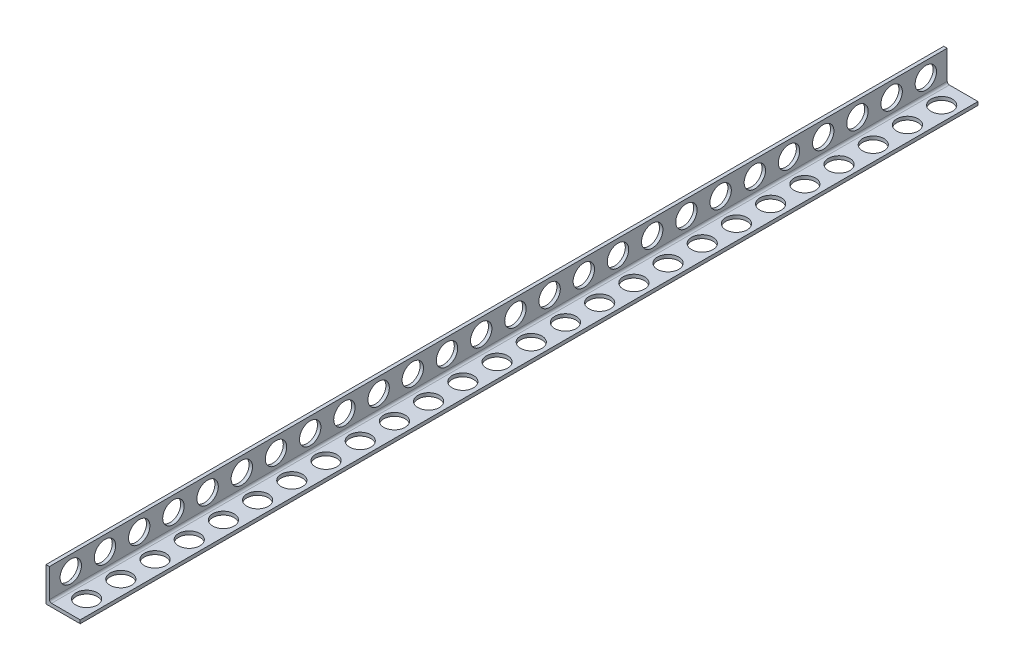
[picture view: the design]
ISO-10303-21;
HEADER;
FILE_DESCRIPTION(('STEP AP214'),'2;1');
FILE_NAME('part.step','',(''),(''),'','','');
FILE_SCHEMA(('AUTOMOTIVE_DESIGN { 1 0 10303 214 1 1 1 1 }'));
ENDSEC;
DATA;
#1=APPLICATION_CONTEXT('core data for automotive mechanical design processes');
#2=APPLICATION_PROTOCOL_DEFINITION('international standard','automotive_design',2000,#1);
#3=PRODUCT_CONTEXT('',#1,'mechanical');
#4=PRODUCT('Part','Part','',(#3));
#5=PRODUCT_RELATED_PRODUCT_CATEGORY('part','',(#4));
#6=PRODUCT_DEFINITION_FORMATION('','',#4);
#7=PRODUCT_DEFINITION_CONTEXT('part definition',#1,'design');
#8=PRODUCT_DEFINITION('design','',#6,#7);
#9=PRODUCT_DEFINITION_SHAPE('','',#8);
#10=(LENGTH_UNIT() NAMED_UNIT(*) SI_UNIT(.MILLI.,.METRE.));
#11=(NAMED_UNIT(*) PLANE_ANGLE_UNIT() SI_UNIT($,.RADIAN.));
#12=(NAMED_UNIT(*) SI_UNIT($,.STERADIAN.) SOLID_ANGLE_UNIT());
#13=UNCERTAINTY_MEASURE_WITH_UNIT(LENGTH_MEASURE(1.E-05),#10,'distance_accuracy_value','');
#14=(GEOMETRIC_REPRESENTATION_CONTEXT(3) GLOBAL_UNCERTAINTY_ASSIGNED_CONTEXT((#13)) GLOBAL_UNIT_ASSIGNED_CONTEXT((#10,
#11,#12)) REPRESENTATION_CONTEXT('',''));
#15=CARTESIAN_POINT('',(0.,0.,0.));
#16=DIRECTION('',(0.,0.,1.));
#17=DIRECTION('',(1.,0.,0.));
#18=AXIS2_PLACEMENT_3D('',#15,#16,#17);
#19=CARTESIAN_POINT('',(-40.,80.,2100.));
#20=DIRECTION('',(1.,0.,0.));
#21=DIRECTION('',(0.,1.,0.));
#22=AXIS2_PLACEMENT_3D('',#19,#20,#21);
#23=PLANE('',#22);
#24=CARTESIAN_POINT('',(-40.,45.,130.));
#25=DIRECTION('',(-1.,0.,0.));
#26=DIRECTION('',(0.,-1.,0.));
#27=AXIS2_PLACEMENT_3D('',#24,#25,#26);
#28=CIRCLE('',#27,25.);
#29=CARTESIAN_POINT('',(-40.,20.,130.));
#30=VERTEX_POINT('',#29);
#31=EDGE_CURVE('E457',#30,#30,#28,.T.);
#32=ORIENTED_EDGE('',*,*,#31,.F.);
#33=EDGE_LOOP('',(#32));
#34=FACE_BOUND('',#33,.T.);
#35=CARTESIAN_POINT('',(-40.,45.,50.));
#36=DIRECTION('',(-1.,0.,0.));
#37=DIRECTION('',(0.,-1.,0.));
#38=AXIS2_PLACEMENT_3D('',#35,#36,#37);
#39=CIRCLE('',#38,25.);
#40=CARTESIAN_POINT('',(-40.,20.,50.));
#41=VERTEX_POINT('',#40);
#42=EDGE_CURVE('E135',#41,#41,#39,.T.);
#43=ORIENTED_EDGE('',*,*,#42,.F.);
#44=EDGE_LOOP('',(#43));
#45=FACE_BOUND('',#44,.T.);
#46=DIRECTION('',(0.,-1.,0.));
#47=VECTOR('',#46,1.);
#48=CARTESIAN_POINT('',(-40.,80.,0.));
#49=LINE('',#48,#47);
#50=CARTESIAN_POINT('',(-40.,80.,0.));
#51=VERTEX_POINT('',#50);
#52=CARTESIAN_POINT('',(-40.,0.,0.));
#53=VERTEX_POINT('',#52);
#54=EDGE_CURVE('E118',#51,#53,#49,.T.);
#55=ORIENTED_EDGE('',*,*,#54,.T.);
#56=DIRECTION('',(0.,0.,-1.));
#57=VECTOR('',#56,1.);
#58=CARTESIAN_POINT('',(-40.,0.,2100.));
#59=LINE('',#58,#57);
#60=CARTESIAN_POINT('',(-40.,0.,2100.));
#61=VERTEX_POINT('',#60);
#62=EDGE_CURVE('E98',#61,#53,#59,.T.);
#63=ORIENTED_EDGE('',*,*,#62,.F.);
#64=DIRECTION('',(0.,-1.,0.));
#65=VECTOR('',#64,1.);
#66=CARTESIAN_POINT('',(-40.,80.,2100.));
#67=LINE('',#66,#65);
#68=CARTESIAN_POINT('',(-40.,80.,2100.));
#69=VERTEX_POINT('',#68);
#70=EDGE_CURVE('E105',#69,#61,#67,.T.);
#71=ORIENTED_EDGE('',*,*,#70,.F.);
#72=DIRECTION('',(0.,0.,-1.));
#73=VECTOR('',#72,1.);
#74=CARTESIAN_POINT('',(-40.,80.,2100.));
#75=LINE('',#74,#73);
#76=EDGE_CURVE('E433',#69,#51,#75,.T.);
#77=ORIENTED_EDGE('',*,*,#76,.T.);
#78=EDGE_LOOP('',(#55,#63,#71,#77));
#79=FACE_BOUND('',#78,.T.);
#80=CARTESIAN_POINT('',(-40.,45.,210.));
#81=DIRECTION('',(-1.,0.,0.));
#82=DIRECTION('',(0.,-1.,0.));
#83=AXIS2_PLACEMENT_3D('',#80,#81,#82);
#84=CIRCLE('',#83,25.);
#85=CARTESIAN_POINT('',(-40.,20.,210.));
#86=VERTEX_POINT('',#85);
#87=EDGE_CURVE('E131',#86,#86,#84,.T.);
#88=ORIENTED_EDGE('',*,*,#87,.F.);
#89=EDGE_LOOP('',(#88));
#90=FACE_BOUND('',#89,.T.);
#91=CARTESIAN_POINT('',(-40.,45.,290.));
#92=DIRECTION('',(-1.,0.,0.));
#93=DIRECTION('',(0.,-1.,0.));
#94=AXIS2_PLACEMENT_3D('',#91,#92,#93);
#95=CIRCLE('',#94,25.);
#96=CARTESIAN_POINT('',(-40.,20.,290.));
#97=VERTEX_POINT('',#96);
#98=EDGE_CURVE('E141',#97,#97,#95,.T.);
#99=ORIENTED_EDGE('',*,*,#98,.F.);
#100=EDGE_LOOP('',(#99));
#101=FACE_BOUND('',#100,.T.);
#102=CARTESIAN_POINT('',(-40.,45.,370.));
#103=DIRECTION('',(-1.,0.,0.));
#104=DIRECTION('',(0.,-1.,0.));
#105=AXIS2_PLACEMENT_3D('',#102,#103,#104);
#106=CIRCLE('',#105,25.);
#107=CARTESIAN_POINT('',(-40.,20.,370.));
#108=VERTEX_POINT('',#107);
#109=EDGE_CURVE('E147',#108,#108,#106,.T.);
#110=ORIENTED_EDGE('',*,*,#109,.F.);
#111=EDGE_LOOP('',(#110));
#112=FACE_BOUND('',#111,.T.);
#113=CARTESIAN_POINT('',(-40.,45.,450.));
#114=DIRECTION('',(-1.,0.,0.));
#115=DIRECTION('',(0.,-1.,0.));
#116=AXIS2_PLACEMENT_3D('',#113,#114,#115);
#117=CIRCLE('',#116,25.);
#118=CARTESIAN_POINT('',(-40.,20.,450.));
#119=VERTEX_POINT('',#118);
#120=EDGE_CURVE('E153',#119,#119,#117,.T.);
#121=ORIENTED_EDGE('',*,*,#120,.F.);
#122=EDGE_LOOP('',(#121));
#123=FACE_BOUND('',#122,.T.);
#124=CARTESIAN_POINT('',(-40.,45.,530.));
#125=DIRECTION('',(-1.,0.,0.));
#126=DIRECTION('',(0.,-1.,0.));
#127=AXIS2_PLACEMENT_3D('',#124,#125,#126);
#128=CIRCLE('',#127,25.);
#129=CARTESIAN_POINT('',(-40.,20.,530.));
#130=VERTEX_POINT('',#129);
#131=EDGE_CURVE('E159',#130,#130,#128,.T.);
#132=ORIENTED_EDGE('',*,*,#131,.F.);
#133=EDGE_LOOP('',(#132));
#134=FACE_BOUND('',#133,.T.);
#135=CARTESIAN_POINT('',(-40.,45.,610.));
#136=DIRECTION('',(-1.,0.,0.));
#137=DIRECTION('',(0.,-1.,0.));
#138=AXIS2_PLACEMENT_3D('',#135,#136,#137);
#139=CIRCLE('',#138,25.);
#140=CARTESIAN_POINT('',(-40.,20.,610.));
#141=VERTEX_POINT('',#140);
#142=EDGE_CURVE('E165',#141,#141,#139,.T.);
#143=ORIENTED_EDGE('',*,*,#142,.F.);
#144=EDGE_LOOP('',(#143));
#145=FACE_BOUND('',#144,.T.);
#146=CARTESIAN_POINT('',(-40.,45.,690.));
#147=DIRECTION('',(-1.,0.,0.));
#148=DIRECTION('',(0.,-1.,0.));
#149=AXIS2_PLACEMENT_3D('',#146,#147,#148);
#150=CIRCLE('',#149,25.);
#151=CARTESIAN_POINT('',(-40.,20.,690.));
#152=VERTEX_POINT('',#151);
#153=EDGE_CURVE('E171',#152,#152,#150,.T.);
#154=ORIENTED_EDGE('',*,*,#153,.F.);
#155=EDGE_LOOP('',(#154));
#156=FACE_BOUND('',#155,.T.);
#157=CARTESIAN_POINT('',(-40.,45.,770.));
#158=DIRECTION('',(-1.,0.,0.));
#159=DIRECTION('',(0.,-1.,0.));
#160=AXIS2_PLACEMENT_3D('',#157,#158,#159);
#161=CIRCLE('',#160,25.);
#162=CARTESIAN_POINT('',(-40.,20.,770.));
#163=VERTEX_POINT('',#162);
#164=EDGE_CURVE('E177',#163,#163,#161,.T.);
#165=ORIENTED_EDGE('',*,*,#164,.F.);
#166=EDGE_LOOP('',(#165));
#167=FACE_BOUND('',#166,.T.);
#168=CARTESIAN_POINT('',(-40.,45.,850.));
#169=DIRECTION('',(-1.,0.,0.));
#170=DIRECTION('',(0.,-1.,0.));
#171=AXIS2_PLACEMENT_3D('',#168,#169,#170);
#172=CIRCLE('',#171,25.);
#173=CARTESIAN_POINT('',(-40.,20.,850.));
#174=VERTEX_POINT('',#173);
#175=EDGE_CURVE('E183',#174,#174,#172,.T.);
#176=ORIENTED_EDGE('',*,*,#175,.F.);
#177=EDGE_LOOP('',(#176));
#178=FACE_BOUND('',#177,.T.);
#179=CARTESIAN_POINT('',(-40.,45.,930.));
#180=DIRECTION('',(-1.,0.,0.));
#181=DIRECTION('',(0.,-1.,0.));
#182=AXIS2_PLACEMENT_3D('',#179,#180,#181);
#183=CIRCLE('',#182,25.);
#184=CARTESIAN_POINT('',(-40.,20.,930.));
#185=VERTEX_POINT('',#184);
#186=EDGE_CURVE('E189',#185,#185,#183,.T.);
#187=ORIENTED_EDGE('',*,*,#186,.F.);
#188=EDGE_LOOP('',(#187));
#189=FACE_BOUND('',#188,.T.);
#190=CARTESIAN_POINT('',(-40.,45.,1010.));
#191=DIRECTION('',(-1.,0.,0.));
#192=DIRECTION('',(0.,-1.,0.));
#193=AXIS2_PLACEMENT_3D('',#190,#191,#192);
#194=CIRCLE('',#193,25.);
#195=CARTESIAN_POINT('',(-40.,20.,1010.));
#196=VERTEX_POINT('',#195);
#197=EDGE_CURVE('E195',#196,#196,#194,.T.);
#198=ORIENTED_EDGE('',*,*,#197,.F.);
#199=EDGE_LOOP('',(#198));
#200=FACE_BOUND('',#199,.T.);
#201=CARTESIAN_POINT('',(-40.,45.,1090.));
#202=DIRECTION('',(-1.,0.,0.));
#203=DIRECTION('',(0.,-1.,0.));
#204=AXIS2_PLACEMENT_3D('',#201,#202,#203);
#205=CIRCLE('',#204,25.);
#206=CARTESIAN_POINT('',(-40.,20.,1090.));
#207=VERTEX_POINT('',#206);
#208=EDGE_CURVE('E201',#207,#207,#205,.T.);
#209=ORIENTED_EDGE('',*,*,#208,.F.);
#210=EDGE_LOOP('',(#209));
#211=FACE_BOUND('',#210,.T.);
#212=CARTESIAN_POINT('',(-40.,45.,1170.));
#213=DIRECTION('',(-1.,0.,0.));
#214=DIRECTION('',(0.,-1.,0.));
#215=AXIS2_PLACEMENT_3D('',#212,#213,#214);
#216=CIRCLE('',#215,25.);
#217=CARTESIAN_POINT('',(-40.,20.,1170.));
#218=VERTEX_POINT('',#217);
#219=EDGE_CURVE('E207',#218,#218,#216,.T.);
#220=ORIENTED_EDGE('',*,*,#219,.F.);
#221=EDGE_LOOP('',(#220));
#222=FACE_BOUND('',#221,.T.);
#223=CARTESIAN_POINT('',(-40.,45.,1250.));
#224=DIRECTION('',(-1.,0.,0.));
#225=DIRECTION('',(0.,-1.,0.));
#226=AXIS2_PLACEMENT_3D('',#223,#224,#225);
#227=CIRCLE('',#226,25.);
#228=CARTESIAN_POINT('',(-40.,20.,1250.));
#229=VERTEX_POINT('',#228);
#230=EDGE_CURVE('E213',#229,#229,#227,.T.);
#231=ORIENTED_EDGE('',*,*,#230,.F.);
#232=EDGE_LOOP('',(#231));
#233=FACE_BOUND('',#232,.T.);
#234=CARTESIAN_POINT('',(-40.,45.,1330.));
#235=DIRECTION('',(-1.,0.,0.));
#236=DIRECTION('',(0.,-1.,0.));
#237=AXIS2_PLACEMENT_3D('',#234,#235,#236);
#238=CIRCLE('',#237,25.);
#239=CARTESIAN_POINT('',(-40.,20.,1330.));
#240=VERTEX_POINT('',#239);
#241=EDGE_CURVE('E219',#240,#240,#238,.T.);
#242=ORIENTED_EDGE('',*,*,#241,.F.);
#243=EDGE_LOOP('',(#242));
#244=FACE_BOUND('',#243,.T.);
#245=CARTESIAN_POINT('',(-40.,45.,1410.));
#246=DIRECTION('',(-1.,0.,0.));
#247=DIRECTION('',(0.,-1.,0.));
#248=AXIS2_PLACEMENT_3D('',#245,#246,#247);
#249=CIRCLE('',#248,25.);
#250=CARTESIAN_POINT('',(-40.,20.,1410.));
#251=VERTEX_POINT('',#250);
#252=EDGE_CURVE('E225',#251,#251,#249,.T.);
#253=ORIENTED_EDGE('',*,*,#252,.F.);
#254=EDGE_LOOP('',(#253));
#255=FACE_BOUND('',#254,.T.);
#256=CARTESIAN_POINT('',(-40.,45.,1490.));
#257=DIRECTION('',(-1.,0.,0.));
#258=DIRECTION('',(0.,-1.,0.));
#259=AXIS2_PLACEMENT_3D('',#256,#257,#258);
#260=CIRCLE('',#259,25.);
#261=CARTESIAN_POINT('',(-40.,20.,1490.));
#262=VERTEX_POINT('',#261);
#263=EDGE_CURVE('E231',#262,#262,#260,.T.);
#264=ORIENTED_EDGE('',*,*,#263,.F.);
#265=EDGE_LOOP('',(#264));
#266=FACE_BOUND('',#265,.T.);
#267=CARTESIAN_POINT('',(-40.,45.,1570.));
#268=DIRECTION('',(-1.,0.,0.));
#269=DIRECTION('',(0.,-1.,0.));
#270=AXIS2_PLACEMENT_3D('',#267,#268,#269);
#271=CIRCLE('',#270,25.);
#272=CARTESIAN_POINT('',(-40.,20.,1570.));
#273=VERTEX_POINT('',#272);
#274=EDGE_CURVE('E237',#273,#273,#271,.T.);
#275=ORIENTED_EDGE('',*,*,#274,.F.);
#276=EDGE_LOOP('',(#275));
#277=FACE_BOUND('',#276,.T.);
#278=CARTESIAN_POINT('',(-40.,45.,1650.));
#279=DIRECTION('',(-1.,0.,0.));
#280=DIRECTION('',(0.,-1.,0.));
#281=AXIS2_PLACEMENT_3D('',#278,#279,#280);
#282=CIRCLE('',#281,25.);
#283=CARTESIAN_POINT('',(-40.,20.,1650.));
#284=VERTEX_POINT('',#283);
#285=EDGE_CURVE('E243',#284,#284,#282,.T.);
#286=ORIENTED_EDGE('',*,*,#285,.F.);
#287=EDGE_LOOP('',(#286));
#288=FACE_BOUND('',#287,.T.);
#289=CARTESIAN_POINT('',(-40.,45.,1730.));
#290=DIRECTION('',(-1.,0.,0.));
#291=DIRECTION('',(0.,-1.,0.));
#292=AXIS2_PLACEMENT_3D('',#289,#290,#291);
#293=CIRCLE('',#292,25.);
#294=CARTESIAN_POINT('',(-40.,20.,1730.));
#295=VERTEX_POINT('',#294);
#296=EDGE_CURVE('E249',#295,#295,#293,.T.);
#297=ORIENTED_EDGE('',*,*,#296,.F.);
#298=EDGE_LOOP('',(#297));
#299=FACE_BOUND('',#298,.T.);
#300=CARTESIAN_POINT('',(-40.,45.,1810.));
#301=DIRECTION('',(-1.,0.,0.));
#302=DIRECTION('',(0.,-1.,0.));
#303=AXIS2_PLACEMENT_3D('',#300,#301,#302);
#304=CIRCLE('',#303,25.);
#305=CARTESIAN_POINT('',(-40.,20.,1810.));
#306=VERTEX_POINT('',#305);
#307=EDGE_CURVE('E255',#306,#306,#304,.T.);
#308=ORIENTED_EDGE('',*,*,#307,.F.);
#309=EDGE_LOOP('',(#308));
#310=FACE_BOUND('',#309,.T.);
#311=CARTESIAN_POINT('',(-40.,45.,1890.));
#312=DIRECTION('',(-1.,0.,0.));
#313=DIRECTION('',(0.,-1.,0.));
#314=AXIS2_PLACEMENT_3D('',#311,#312,#313);
#315=CIRCLE('',#314,25.);
#316=CARTESIAN_POINT('',(-40.,20.,1890.));
#317=VERTEX_POINT('',#316);
#318=EDGE_CURVE('E261',#317,#317,#315,.T.);
#319=ORIENTED_EDGE('',*,*,#318,.F.);
#320=EDGE_LOOP('',(#319));
#321=FACE_BOUND('',#320,.T.);
#322=CARTESIAN_POINT('',(-40.,45.,1970.));
#323=DIRECTION('',(-1.,0.,0.));
#324=DIRECTION('',(0.,-1.,0.));
#325=AXIS2_PLACEMENT_3D('',#322,#323,#324);
#326=CIRCLE('',#325,25.);
#327=CARTESIAN_POINT('',(-40.,20.,1970.));
#328=VERTEX_POINT('',#327);
#329=EDGE_CURVE('E267',#328,#328,#326,.T.);
#330=ORIENTED_EDGE('',*,*,#329,.F.);
#331=EDGE_LOOP('',(#330));
#332=FACE_BOUND('',#331,.T.);
#333=CARTESIAN_POINT('',(-40.,45.,2050.));
#334=DIRECTION('',(-1.,0.,0.));
#335=DIRECTION('',(0.,-1.,0.));
#336=AXIS2_PLACEMENT_3D('',#333,#334,#335);
#337=CIRCLE('',#336,25.);
#338=CARTESIAN_POINT('',(-40.,20.,2050.));
#339=VERTEX_POINT('',#338);
#340=EDGE_CURVE('E41',#339,#339,#337,.T.);
#341=ORIENTED_EDGE('',*,*,#340,.F.);
#342=EDGE_LOOP('',(#341));
#343=FACE_BOUND('',#342,.T.);
#344=ADVANCED_FACE('F33',(#34,#45,#79,#90,#101,#112,#123,#134,#145,#156,#167,#178,#189,#200,
#211,#222,#233,#244,#255,#266,#277,#288,#299,#310,#321,#332,#343),#23,.F.);
#345=CARTESIAN_POINT('',(-40.,0.,2100.));
#346=DIRECTION('',(0.,1.,0.));
#347=DIRECTION('',(0.,0.,1.));
#348=AXIS2_PLACEMENT_3D('',#345,#346,#347);
#349=PLANE('',#348);
#350=CARTESIAN_POINT('',(5.00000000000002,0.,2050.));
#351=DIRECTION('',(0.,1.,0.));
#352=DIRECTION('',(0.,0.,1.));
#353=AXIS2_PLACEMENT_3D('',#350,#351,#352);
#354=CIRCLE('',#353,25.);
#355=CARTESIAN_POINT('',(5.00000000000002,0.,2075.));
#356=VERTEX_POINT('',#355);
#357=EDGE_CURVE('E602',#356,#356,#354,.T.);
#358=ORIENTED_EDGE('',*,*,#357,.T.);
#359=EDGE_LOOP('',(#358));
#360=FACE_BOUND('',#359,.T.);
#361=CARTESIAN_POINT('',(5.00000000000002,0.,1970.));
#362=DIRECTION('',(0.,1.,0.));
#363=DIRECTION('',(0.,0.,1.));
#364=AXIS2_PLACEMENT_3D('',#361,#362,#363);
#365=CIRCLE('',#364,25.);
#366=CARTESIAN_POINT('',(5.00000000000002,0.,1995.));
#367=VERTEX_POINT('',#366);
#368=EDGE_CURVE('E596',#367,#367,#365,.T.);
#369=ORIENTED_EDGE('',*,*,#368,.T.);
#370=EDGE_LOOP('',(#369));
#371=FACE_BOUND('',#370,.T.);
#372=CARTESIAN_POINT('',(5.00000000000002,0.,1890.));
#373=DIRECTION('',(0.,1.,0.));
#374=DIRECTION('',(0.,0.,1.));
#375=AXIS2_PLACEMENT_3D('',#372,#373,#374);
#376=CIRCLE('',#375,25.);
#377=CARTESIAN_POINT('',(5.00000000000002,0.,1915.));
#378=VERTEX_POINT('',#377);
#379=EDGE_CURVE('E590',#378,#378,#376,.T.);
#380=ORIENTED_EDGE('',*,*,#379,.T.);
#381=EDGE_LOOP('',(#380));
#382=FACE_BOUND('',#381,.T.);
#383=CARTESIAN_POINT('',(5.00000000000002,0.,1810.));
#384=DIRECTION('',(0.,1.,0.));
#385=DIRECTION('',(0.,0.,1.));
#386=AXIS2_PLACEMENT_3D('',#383,#384,#385);
#387=CIRCLE('',#386,25.);
#388=CARTESIAN_POINT('',(5.00000000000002,0.,1835.));
#389=VERTEX_POINT('',#388);
#390=EDGE_CURVE('E584',#389,#389,#387,.T.);
#391=ORIENTED_EDGE('',*,*,#390,.T.);
#392=EDGE_LOOP('',(#391));
#393=FACE_BOUND('',#392,.T.);
#394=CARTESIAN_POINT('',(5.00000000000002,0.,1730.));
#395=DIRECTION('',(0.,1.,0.));
#396=DIRECTION('',(0.,0.,1.));
#397=AXIS2_PLACEMENT_3D('',#394,#395,#396);
#398=CIRCLE('',#397,25.);
#399=CARTESIAN_POINT('',(5.00000000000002,0.,1755.));
#400=VERTEX_POINT('',#399);
#401=EDGE_CURVE('E578',#400,#400,#398,.T.);
#402=ORIENTED_EDGE('',*,*,#401,.T.);
#403=EDGE_LOOP('',(#402));
#404=FACE_BOUND('',#403,.T.);
#405=CARTESIAN_POINT('',(5.00000000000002,0.,1650.));
#406=DIRECTION('',(0.,1.,0.));
#407=DIRECTION('',(0.,0.,1.));
#408=AXIS2_PLACEMENT_3D('',#405,#406,#407);
#409=CIRCLE('',#408,25.);
#410=CARTESIAN_POINT('',(5.00000000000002,0.,1675.));
#411=VERTEX_POINT('',#410);
#412=EDGE_CURVE('E572',#411,#411,#409,.T.);
#413=ORIENTED_EDGE('',*,*,#412,.T.);
#414=EDGE_LOOP('',(#413));
#415=FACE_BOUND('',#414,.T.);
#416=CARTESIAN_POINT('',(5.00000000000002,0.,1570.));
#417=DIRECTION('',(0.,1.,0.));
#418=DIRECTION('',(0.,0.,1.));
#419=AXIS2_PLACEMENT_3D('',#416,#417,#418);
#420=CIRCLE('',#419,25.);
#421=CARTESIAN_POINT('',(5.00000000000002,0.,1595.));
#422=VERTEX_POINT('',#421);
#423=EDGE_CURVE('E566',#422,#422,#420,.T.);
#424=ORIENTED_EDGE('',*,*,#423,.T.);
#425=EDGE_LOOP('',(#424));
#426=FACE_BOUND('',#425,.T.);
#427=CARTESIAN_POINT('',(5.00000000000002,0.,1490.));
#428=DIRECTION('',(0.,1.,0.));
#429=DIRECTION('',(0.,0.,1.));
#430=AXIS2_PLACEMENT_3D('',#427,#428,#429);
#431=CIRCLE('',#430,25.);
#432=CARTESIAN_POINT('',(5.00000000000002,0.,1515.));
#433=VERTEX_POINT('',#432);
#434=EDGE_CURVE('E560',#433,#433,#431,.T.);
#435=ORIENTED_EDGE('',*,*,#434,.T.);
#436=EDGE_LOOP('',(#435));
#437=FACE_BOUND('',#436,.T.);
#438=CARTESIAN_POINT('',(5.00000000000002,0.,1410.));
#439=DIRECTION('',(0.,1.,0.));
#440=DIRECTION('',(0.,0.,1.));
#441=AXIS2_PLACEMENT_3D('',#438,#439,#440);
#442=CIRCLE('',#441,25.);
#443=CARTESIAN_POINT('',(5.00000000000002,0.,1435.));
#444=VERTEX_POINT('',#443);
#445=EDGE_CURVE('E554',#444,#444,#442,.T.);
#446=ORIENTED_EDGE('',*,*,#445,.T.);
#447=EDGE_LOOP('',(#446));
#448=FACE_BOUND('',#447,.T.);
#449=CARTESIAN_POINT('',(5.00000000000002,0.,1330.));
#450=DIRECTION('',(0.,1.,0.));
#451=DIRECTION('',(0.,0.,1.));
#452=AXIS2_PLACEMENT_3D('',#449,#450,#451);
#453=CIRCLE('',#452,25.);
#454=CARTESIAN_POINT('',(5.00000000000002,0.,1355.));
#455=VERTEX_POINT('',#454);
#456=EDGE_CURVE('E548',#455,#455,#453,.T.);
#457=ORIENTED_EDGE('',*,*,#456,.T.);
#458=EDGE_LOOP('',(#457));
#459=FACE_BOUND('',#458,.T.);
#460=CARTESIAN_POINT('',(5.00000000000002,0.,1250.));
#461=DIRECTION('',(0.,1.,0.));
#462=DIRECTION('',(0.,0.,1.));
#463=AXIS2_PLACEMENT_3D('',#460,#461,#462);
#464=CIRCLE('',#463,25.);
#465=CARTESIAN_POINT('',(5.00000000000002,0.,1275.));
#466=VERTEX_POINT('',#465);
#467=EDGE_CURVE('E542',#466,#466,#464,.T.);
#468=ORIENTED_EDGE('',*,*,#467,.T.);
#469=EDGE_LOOP('',(#468));
#470=FACE_BOUND('',#469,.T.);
#471=CARTESIAN_POINT('',(5.00000000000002,0.,1170.));
#472=DIRECTION('',(0.,1.,0.));
#473=DIRECTION('',(0.,0.,1.));
#474=AXIS2_PLACEMENT_3D('',#471,#472,#473);
#475=CIRCLE('',#474,25.);
#476=CARTESIAN_POINT('',(5.00000000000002,0.,1195.));
#477=VERTEX_POINT('',#476);
#478=EDGE_CURVE('E536',#477,#477,#475,.T.);
#479=ORIENTED_EDGE('',*,*,#478,.T.);
#480=EDGE_LOOP('',(#479));
#481=FACE_BOUND('',#480,.T.);
#482=CARTESIAN_POINT('',(5.00000000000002,0.,1090.));
#483=DIRECTION('',(0.,1.,0.));
#484=DIRECTION('',(0.,0.,1.));
#485=AXIS2_PLACEMENT_3D('',#482,#483,#484);
#486=CIRCLE('',#485,25.);
#487=CARTESIAN_POINT('',(5.00000000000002,0.,1115.));
#488=VERTEX_POINT('',#487);
#489=EDGE_CURVE('E530',#488,#488,#486,.T.);
#490=ORIENTED_EDGE('',*,*,#489,.T.);
#491=EDGE_LOOP('',(#490));
#492=FACE_BOUND('',#491,.T.);
#493=CARTESIAN_POINT('',(5.00000000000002,0.,1010.));
#494=DIRECTION('',(0.,1.,0.));
#495=DIRECTION('',(0.,0.,1.));
#496=AXIS2_PLACEMENT_3D('',#493,#494,#495);
#497=CIRCLE('',#496,25.);
#498=CARTESIAN_POINT('',(5.00000000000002,0.,1035.));
#499=VERTEX_POINT('',#498);
#500=EDGE_CURVE('E524',#499,#499,#497,.T.);
#501=ORIENTED_EDGE('',*,*,#500,.T.);
#502=EDGE_LOOP('',(#501));
#503=FACE_BOUND('',#502,.T.);
#504=CARTESIAN_POINT('',(5.00000000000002,0.,930.));
#505=DIRECTION('',(0.,1.,0.));
#506=DIRECTION('',(0.,0.,1.));
#507=AXIS2_PLACEMENT_3D('',#504,#505,#506);
#508=CIRCLE('',#507,25.);
#509=CARTESIAN_POINT('',(5.00000000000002,0.,955.));
#510=VERTEX_POINT('',#509);
#511=EDGE_CURVE('E518',#510,#510,#508,.T.);
#512=ORIENTED_EDGE('',*,*,#511,.T.);
#513=EDGE_LOOP('',(#512));
#514=FACE_BOUND('',#513,.T.);
#515=CARTESIAN_POINT('',(5.00000000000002,0.,850.));
#516=DIRECTION('',(0.,1.,0.));
#517=DIRECTION('',(0.,0.,1.));
#518=AXIS2_PLACEMENT_3D('',#515,#516,#517);
#519=CIRCLE('',#518,25.);
#520=CARTESIAN_POINT('',(5.00000000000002,0.,875.));
#521=VERTEX_POINT('',#520);
#522=EDGE_CURVE('E512',#521,#521,#519,.T.);
#523=ORIENTED_EDGE('',*,*,#522,.T.);
#524=EDGE_LOOP('',(#523));
#525=FACE_BOUND('',#524,.T.);
#526=CARTESIAN_POINT('',(5.00000000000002,0.,770.));
#527=DIRECTION('',(0.,1.,0.));
#528=DIRECTION('',(0.,0.,1.));
#529=AXIS2_PLACEMENT_3D('',#526,#527,#528);
#530=CIRCLE('',#529,25.);
#531=CARTESIAN_POINT('',(5.00000000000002,0.,795.));
#532=VERTEX_POINT('',#531);
#533=EDGE_CURVE('E506',#532,#532,#530,.T.);
#534=ORIENTED_EDGE('',*,*,#533,.T.);
#535=EDGE_LOOP('',(#534));
#536=FACE_BOUND('',#535,.T.);
#537=CARTESIAN_POINT('',(5.00000000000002,0.,690.));
#538=DIRECTION('',(0.,1.,0.));
#539=DIRECTION('',(0.,0.,1.));
#540=AXIS2_PLACEMENT_3D('',#537,#538,#539);
#541=CIRCLE('',#540,25.);
#542=CARTESIAN_POINT('',(5.00000000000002,0.,715.));
#543=VERTEX_POINT('',#542);
#544=EDGE_CURVE('E500',#543,#543,#541,.T.);
#545=ORIENTED_EDGE('',*,*,#544,.T.);
#546=EDGE_LOOP('',(#545));
#547=FACE_BOUND('',#546,.T.);
#548=CARTESIAN_POINT('',(5.00000000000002,0.,610.));
#549=DIRECTION('',(0.,1.,0.));
#550=DIRECTION('',(0.,0.,1.));
#551=AXIS2_PLACEMENT_3D('',#548,#549,#550);
#552=CIRCLE('',#551,25.);
#553=CARTESIAN_POINT('',(5.00000000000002,0.,635.));
#554=VERTEX_POINT('',#553);
#555=EDGE_CURVE('E494',#554,#554,#552,.T.);
#556=ORIENTED_EDGE('',*,*,#555,.T.);
#557=EDGE_LOOP('',(#556));
#558=FACE_BOUND('',#557,.T.);
#559=CARTESIAN_POINT('',(5.00000000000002,0.,530.));
#560=DIRECTION('',(0.,1.,0.));
#561=DIRECTION('',(0.,0.,1.));
#562=AXIS2_PLACEMENT_3D('',#559,#560,#561);
#563=CIRCLE('',#562,25.);
#564=CARTESIAN_POINT('',(5.00000000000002,0.,555.));
#565=VERTEX_POINT('',#564);
#566=EDGE_CURVE('E488',#565,#565,#563,.T.);
#567=ORIENTED_EDGE('',*,*,#566,.T.);
#568=EDGE_LOOP('',(#567));
#569=FACE_BOUND('',#568,.T.);
#570=CARTESIAN_POINT('',(5.00000000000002,0.,450.));
#571=DIRECTION('',(0.,1.,0.));
#572=DIRECTION('',(0.,0.,1.));
#573=AXIS2_PLACEMENT_3D('',#570,#571,#572);
#574=CIRCLE('',#573,25.);
#575=CARTESIAN_POINT('',(5.00000000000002,0.,475.));
#576=VERTEX_POINT('',#575);
#577=EDGE_CURVE('E482',#576,#576,#574,.T.);
#578=ORIENTED_EDGE('',*,*,#577,.T.);
#579=EDGE_LOOP('',(#578));
#580=FACE_BOUND('',#579,.T.);
#581=CARTESIAN_POINT('',(5.00000000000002,0.,370.));
#582=DIRECTION('',(0.,1.,0.));
#583=DIRECTION('',(0.,0.,1.));
#584=AXIS2_PLACEMENT_3D('',#581,#582,#583);
#585=CIRCLE('',#584,25.);
#586=CARTESIAN_POINT('',(5.00000000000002,0.,395.));
#587=VERTEX_POINT('',#586);
#588=EDGE_CURVE('E476',#587,#587,#585,.T.);
#589=ORIENTED_EDGE('',*,*,#588,.T.);
#590=EDGE_LOOP('',(#589));
#591=FACE_BOUND('',#590,.T.);
#592=CARTESIAN_POINT('',(5.00000000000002,0.,290.));
#593=DIRECTION('',(0.,1.,0.));
#594=DIRECTION('',(0.,0.,1.));
#595=AXIS2_PLACEMENT_3D('',#592,#593,#594);
#596=CIRCLE('',#595,25.);
#597=CARTESIAN_POINT('',(5.00000000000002,0.,315.));
#598=VERTEX_POINT('',#597);
#599=EDGE_CURVE('E470',#598,#598,#596,.T.);
#600=ORIENTED_EDGE('',*,*,#599,.T.);
#601=EDGE_LOOP('',(#600));
#602=FACE_BOUND('',#601,.T.);
#603=CARTESIAN_POINT('',(5.00000000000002,0.,210.));
#604=DIRECTION('',(0.,1.,0.));
#605=DIRECTION('',(0.,0.,1.));
#606=AXIS2_PLACEMENT_3D('',#603,#604,#605);
#607=CIRCLE('',#606,25.);
#608=CARTESIAN_POINT('',(5.00000000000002,0.,235.));
#609=VERTEX_POINT('',#608);
#610=EDGE_CURVE('E464',#609,#609,#607,.T.);
#611=ORIENTED_EDGE('',*,*,#610,.T.);
#612=EDGE_LOOP('',(#611));
#613=FACE_BOUND('',#612,.T.);
#614=CARTESIAN_POINT('',(5.00000000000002,0.,130.));
#615=DIRECTION('',(0.,1.,0.));
#616=DIRECTION('',(0.,0.,1.));
#617=AXIS2_PLACEMENT_3D('',#614,#615,#616);
#618=CIRCLE('',#617,25.);
#619=CARTESIAN_POINT('',(5.00000000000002,0.,155.));
#620=VERTEX_POINT('',#619);
#621=EDGE_CURVE('E460',#620,#620,#618,.T.);
#622=ORIENTED_EDGE('',*,*,#621,.T.);
#623=EDGE_LOOP('',(#622));
#624=FACE_BOUND('',#623,.T.);
#625=CARTESIAN_POINT('',(5.00000000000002,0.,50.));
#626=DIRECTION('',(0.,1.,0.));
#627=DIRECTION('',(0.,0.,1.));
#628=AXIS2_PLACEMENT_3D('',#625,#626,#627);
#629=CIRCLE('',#628,25.);
#630=CARTESIAN_POINT('',(5.00000000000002,0.,75.));
#631=VERTEX_POINT('',#630);
#632=EDGE_CURVE('E449',#631,#631,#629,.T.);
#633=ORIENTED_EDGE('',*,*,#632,.T.);
#634=EDGE_LOOP('',(#633));
#635=FACE_BOUND('',#634,.T.);
#636=DIRECTION('',(1.,0.,0.));
#637=VECTOR('',#636,1.);
#638=CARTESIAN_POINT('',(-40.,0.,0.));
#639=LINE('',#638,#637);
#640=CARTESIAN_POINT('',(40.,0.,0.));
#641=VERTEX_POINT('',#640);
#642=EDGE_CURVE('E423',#53,#641,#639,.T.);
#643=ORIENTED_EDGE('',*,*,#642,.T.);
#644=DIRECTION('',(0.,0.,-1.));
#645=VECTOR('',#644,1.);
#646=CARTESIAN_POINT('',(40.,0.,2100.));
#647=LINE('',#646,#645);
#648=CARTESIAN_POINT('',(40.,0.,2100.));
#649=VERTEX_POINT('',#648);
#650=EDGE_CURVE('E101',#649,#641,#647,.T.);
#651=ORIENTED_EDGE('',*,*,#650,.F.);
#652=DIRECTION('',(1.,0.,0.));
#653=VECTOR('',#652,1.);
#654=CARTESIAN_POINT('',(-40.,0.,2100.));
#655=LINE('',#654,#653);
#656=EDGE_CURVE('E94',#61,#649,#655,.T.);
#657=ORIENTED_EDGE('',*,*,#656,.F.);
#658=ORIENTED_EDGE('',*,*,#62,.T.);
#659=EDGE_LOOP('',(#643,#651,#657,#658));
#660=FACE_BOUND('',#659,.T.);
#661=ADVANCED_FACE('F96',(#360,#371,#382,#393,#404,#415,#426,#437,#448,#459,#470,#481,#492,#503,
#514,#525,#536,#547,#558,#569,#580,#591,#602,#613,#624,#635,#660),#349,.F.);
#662=CARTESIAN_POINT('',(40.,8.,2100.));
#663=DIRECTION('',(-1.,0.,0.));
#664=DIRECTION('',(0.,-1.,0.));
#665=AXIS2_PLACEMENT_3D('',#662,#663,#664);
#666=PLANE('',#665);
#667=DIRECTION('',(0.,1.,0.));
#668=VECTOR('',#667,1.);
#669=CARTESIAN_POINT('',(40.,8.,0.));
#670=LINE('',#669,#668);
#671=CARTESIAN_POINT('',(40.,8.,0.));
#672=VERTEX_POINT('',#671);
#673=EDGE_CURVE('E420',#641,#672,#670,.T.);
#674=ORIENTED_EDGE('',*,*,#673,.T.);
#675=DIRECTION('',(0.,0.,-1.));
#676=VECTOR('',#675,1.);
#677=CARTESIAN_POINT('',(40.,8.,2100.));
#678=LINE('',#677,#676);
#679=CARTESIAN_POINT('',(40.,8.,2100.));
#680=VERTEX_POINT('',#679);
#681=EDGE_CURVE('E123',#680,#672,#678,.T.);
#682=ORIENTED_EDGE('',*,*,#681,.F.);
#683=DIRECTION('',(0.,1.,0.));
#684=VECTOR('',#683,1.);
#685=CARTESIAN_POINT('',(40.,8.,2100.));
#686=LINE('',#685,#684);
#687=EDGE_CURVE('E104',#649,#680,#686,.T.);
#688=ORIENTED_EDGE('',*,*,#687,.F.);
#689=ORIENTED_EDGE('',*,*,#650,.T.);
#690=EDGE_LOOP('',(#674,#682,#688,#689));
#691=FACE_BOUND('',#690,.T.);
#692=ADVANCED_FACE('F283',(#691),#666,.F.);
#693=CARTESIAN_POINT('',(-32.,8.,2100.));
#694=DIRECTION('',(0.,-1.,0.));
#695=DIRECTION('',(0.,0.,-1.));
#696=AXIS2_PLACEMENT_3D('',#693,#694,#695);
#697=PLANE('',#696);
#698=CARTESIAN_POINT('',(5.00000000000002,8.,2050.));
#699=DIRECTION('',(0.,1.,0.));
#700=DIRECTION('',(0.,0.,1.));
#701=AXIS2_PLACEMENT_3D('',#698,#699,#700);
#702=CIRCLE('',#701,25.);
#703=CARTESIAN_POINT('',(5.00000000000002,8.,2075.));
#704=VERTEX_POINT('',#703);
#705=EDGE_CURVE('E605',#704,#704,#702,.T.);
#706=ORIENTED_EDGE('',*,*,#705,.F.);
#707=EDGE_LOOP('',(#706));
#708=FACE_BOUND('',#707,.T.);
#709=CARTESIAN_POINT('',(5.00000000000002,8.,1970.));
#710=DIRECTION('',(0.,1.,0.));
#711=DIRECTION('',(0.,0.,1.));
#712=AXIS2_PLACEMENT_3D('',#709,#710,#711);
#713=CIRCLE('',#712,25.);
#714=CARTESIAN_POINT('',(5.00000000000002,8.,1995.));
#715=VERTEX_POINT('',#714);
#716=EDGE_CURVE('E599',#715,#715,#713,.T.);
#717=ORIENTED_EDGE('',*,*,#716,.F.);
#718=EDGE_LOOP('',(#717));
#719=FACE_BOUND('',#718,.T.);
#720=CARTESIAN_POINT('',(5.00000000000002,8.,1890.));
#721=DIRECTION('',(0.,1.,0.));
#722=DIRECTION('',(0.,0.,1.));
#723=AXIS2_PLACEMENT_3D('',#720,#721,#722);
#724=CIRCLE('',#723,25.);
#725=CARTESIAN_POINT('',(5.00000000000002,8.,1915.));
#726=VERTEX_POINT('',#725);
#727=EDGE_CURVE('E593',#726,#726,#724,.T.);
#728=ORIENTED_EDGE('',*,*,#727,.F.);
#729=EDGE_LOOP('',(#728));
#730=FACE_BOUND('',#729,.T.);
#731=CARTESIAN_POINT('',(5.00000000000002,8.,1810.));
#732=DIRECTION('',(0.,1.,0.));
#733=DIRECTION('',(0.,0.,1.));
#734=AXIS2_PLACEMENT_3D('',#731,#732,#733);
#735=CIRCLE('',#734,25.);
#736=CARTESIAN_POINT('',(5.00000000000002,8.,1835.));
#737=VERTEX_POINT('',#736);
#738=EDGE_CURVE('E587',#737,#737,#735,.T.);
#739=ORIENTED_EDGE('',*,*,#738,.F.);
#740=EDGE_LOOP('',(#739));
#741=FACE_BOUND('',#740,.T.);
#742=CARTESIAN_POINT('',(5.00000000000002,8.,1730.));
#743=DIRECTION('',(0.,1.,0.));
#744=DIRECTION('',(0.,0.,1.));
#745=AXIS2_PLACEMENT_3D('',#742,#743,#744);
#746=CIRCLE('',#745,25.);
#747=CARTESIAN_POINT('',(5.00000000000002,8.,1755.));
#748=VERTEX_POINT('',#747);
#749=EDGE_CURVE('E581',#748,#748,#746,.T.);
#750=ORIENTED_EDGE('',*,*,#749,.F.);
#751=EDGE_LOOP('',(#750));
#752=FACE_BOUND('',#751,.T.);
#753=CARTESIAN_POINT('',(5.00000000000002,8.,1650.));
#754=DIRECTION('',(0.,1.,0.));
#755=DIRECTION('',(0.,0.,1.));
#756=AXIS2_PLACEMENT_3D('',#753,#754,#755);
#757=CIRCLE('',#756,25.);
#758=CARTESIAN_POINT('',(5.00000000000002,8.,1675.));
#759=VERTEX_POINT('',#758);
#760=EDGE_CURVE('E575',#759,#759,#757,.T.);
#761=ORIENTED_EDGE('',*,*,#760,.F.);
#762=EDGE_LOOP('',(#761));
#763=FACE_BOUND('',#762,.T.);
#764=CARTESIAN_POINT('',(5.00000000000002,8.,1570.));
#765=DIRECTION('',(0.,1.,0.));
#766=DIRECTION('',(0.,0.,1.));
#767=AXIS2_PLACEMENT_3D('',#764,#765,#766);
#768=CIRCLE('',#767,25.);
#769=CARTESIAN_POINT('',(5.00000000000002,8.,1595.));
#770=VERTEX_POINT('',#769);
#771=EDGE_CURVE('E569',#770,#770,#768,.T.);
#772=ORIENTED_EDGE('',*,*,#771,.F.);
#773=EDGE_LOOP('',(#772));
#774=FACE_BOUND('',#773,.T.);
#775=CARTESIAN_POINT('',(5.00000000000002,8.,1490.));
#776=DIRECTION('',(0.,1.,0.));
#777=DIRECTION('',(0.,0.,1.));
#778=AXIS2_PLACEMENT_3D('',#775,#776,#777);
#779=CIRCLE('',#778,25.);
#780=CARTESIAN_POINT('',(5.00000000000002,8.,1515.));
#781=VERTEX_POINT('',#780);
#782=EDGE_CURVE('E563',#781,#781,#779,.T.);
#783=ORIENTED_EDGE('',*,*,#782,.F.);
#784=EDGE_LOOP('',(#783));
#785=FACE_BOUND('',#784,.T.);
#786=CARTESIAN_POINT('',(5.00000000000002,8.,1410.));
#787=DIRECTION('',(0.,1.,0.));
#788=DIRECTION('',(0.,0.,1.));
#789=AXIS2_PLACEMENT_3D('',#786,#787,#788);
#790=CIRCLE('',#789,25.);
#791=CARTESIAN_POINT('',(5.00000000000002,8.,1435.));
#792=VERTEX_POINT('',#791);
#793=EDGE_CURVE('E557',#792,#792,#790,.T.);
#794=ORIENTED_EDGE('',*,*,#793,.F.);
#795=EDGE_LOOP('',(#794));
#796=FACE_BOUND('',#795,.T.);
#797=CARTESIAN_POINT('',(5.00000000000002,8.,1330.));
#798=DIRECTION('',(0.,1.,0.));
#799=DIRECTION('',(0.,0.,1.));
#800=AXIS2_PLACEMENT_3D('',#797,#798,#799);
#801=CIRCLE('',#800,25.);
#802=CARTESIAN_POINT('',(5.00000000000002,8.,1355.));
#803=VERTEX_POINT('',#802);
#804=EDGE_CURVE('E551',#803,#803,#801,.T.);
#805=ORIENTED_EDGE('',*,*,#804,.F.);
#806=EDGE_LOOP('',(#805));
#807=FACE_BOUND('',#806,.T.);
#808=CARTESIAN_POINT('',(5.00000000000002,8.,1250.));
#809=DIRECTION('',(0.,1.,0.));
#810=DIRECTION('',(0.,0.,1.));
#811=AXIS2_PLACEMENT_3D('',#808,#809,#810);
#812=CIRCLE('',#811,25.);
#813=CARTESIAN_POINT('',(5.00000000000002,8.,1275.));
#814=VERTEX_POINT('',#813);
#815=EDGE_CURVE('E545',#814,#814,#812,.T.);
#816=ORIENTED_EDGE('',*,*,#815,.F.);
#817=EDGE_LOOP('',(#816));
#818=FACE_BOUND('',#817,.T.);
#819=CARTESIAN_POINT('',(5.00000000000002,8.,1170.));
#820=DIRECTION('',(0.,1.,0.));
#821=DIRECTION('',(0.,0.,1.));
#822=AXIS2_PLACEMENT_3D('',#819,#820,#821);
#823=CIRCLE('',#822,25.);
#824=CARTESIAN_POINT('',(5.00000000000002,8.,1195.));
#825=VERTEX_POINT('',#824);
#826=EDGE_CURVE('E539',#825,#825,#823,.T.);
#827=ORIENTED_EDGE('',*,*,#826,.F.);
#828=EDGE_LOOP('',(#827));
#829=FACE_BOUND('',#828,.T.);
#830=CARTESIAN_POINT('',(5.00000000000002,8.,1090.));
#831=DIRECTION('',(0.,1.,0.));
#832=DIRECTION('',(0.,0.,1.));
#833=AXIS2_PLACEMENT_3D('',#830,#831,#832);
#834=CIRCLE('',#833,25.);
#835=CARTESIAN_POINT('',(5.00000000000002,8.,1115.));
#836=VERTEX_POINT('',#835);
#837=EDGE_CURVE('E533',#836,#836,#834,.T.);
#838=ORIENTED_EDGE('',*,*,#837,.F.);
#839=EDGE_LOOP('',(#838));
#840=FACE_BOUND('',#839,.T.);
#841=CARTESIAN_POINT('',(5.00000000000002,8.,1010.));
#842=DIRECTION('',(0.,1.,0.));
#843=DIRECTION('',(0.,0.,1.));
#844=AXIS2_PLACEMENT_3D('',#841,#842,#843);
#845=CIRCLE('',#844,25.);
#846=CARTESIAN_POINT('',(5.00000000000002,8.,1035.));
#847=VERTEX_POINT('',#846);
#848=EDGE_CURVE('E527',#847,#847,#845,.T.);
#849=ORIENTED_EDGE('',*,*,#848,.F.);
#850=EDGE_LOOP('',(#849));
#851=FACE_BOUND('',#850,.T.);
#852=CARTESIAN_POINT('',(5.00000000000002,8.,930.));
#853=DIRECTION('',(0.,1.,0.));
#854=DIRECTION('',(0.,0.,1.));
#855=AXIS2_PLACEMENT_3D('',#852,#853,#854);
#856=CIRCLE('',#855,25.);
#857=CARTESIAN_POINT('',(5.00000000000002,8.,955.));
#858=VERTEX_POINT('',#857);
#859=EDGE_CURVE('E521',#858,#858,#856,.T.);
#860=ORIENTED_EDGE('',*,*,#859,.F.);
#861=EDGE_LOOP('',(#860));
#862=FACE_BOUND('',#861,.T.);
#863=CARTESIAN_POINT('',(5.00000000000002,8.,850.));
#864=DIRECTION('',(0.,1.,0.));
#865=DIRECTION('',(0.,0.,1.));
#866=AXIS2_PLACEMENT_3D('',#863,#864,#865);
#867=CIRCLE('',#866,25.);
#868=CARTESIAN_POINT('',(5.00000000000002,8.,875.));
#869=VERTEX_POINT('',#868);
#870=EDGE_CURVE('E515',#869,#869,#867,.T.);
#871=ORIENTED_EDGE('',*,*,#870,.F.);
#872=EDGE_LOOP('',(#871));
#873=FACE_BOUND('',#872,.T.);
#874=CARTESIAN_POINT('',(5.00000000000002,8.,770.));
#875=DIRECTION('',(0.,1.,0.));
#876=DIRECTION('',(0.,0.,1.));
#877=AXIS2_PLACEMENT_3D('',#874,#875,#876);
#878=CIRCLE('',#877,25.);
#879=CARTESIAN_POINT('',(5.00000000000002,8.,795.));
#880=VERTEX_POINT('',#879);
#881=EDGE_CURVE('E509',#880,#880,#878,.T.);
#882=ORIENTED_EDGE('',*,*,#881,.F.);
#883=EDGE_LOOP('',(#882));
#884=FACE_BOUND('',#883,.T.);
#885=CARTESIAN_POINT('',(5.00000000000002,8.,690.));
#886=DIRECTION('',(0.,1.,0.));
#887=DIRECTION('',(0.,0.,1.));
#888=AXIS2_PLACEMENT_3D('',#885,#886,#887);
#889=CIRCLE('',#888,25.);
#890=CARTESIAN_POINT('',(5.00000000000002,8.,715.));
#891=VERTEX_POINT('',#890);
#892=EDGE_CURVE('E503',#891,#891,#889,.T.);
#893=ORIENTED_EDGE('',*,*,#892,.F.);
#894=EDGE_LOOP('',(#893));
#895=FACE_BOUND('',#894,.T.);
#896=CARTESIAN_POINT('',(5.00000000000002,8.,610.));
#897=DIRECTION('',(0.,1.,0.));
#898=DIRECTION('',(0.,0.,1.));
#899=AXIS2_PLACEMENT_3D('',#896,#897,#898);
#900=CIRCLE('',#899,25.);
#901=CARTESIAN_POINT('',(5.00000000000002,8.,635.));
#902=VERTEX_POINT('',#901);
#903=EDGE_CURVE('E497',#902,#902,#900,.T.);
#904=ORIENTED_EDGE('',*,*,#903,.F.);
#905=EDGE_LOOP('',(#904));
#906=FACE_BOUND('',#905,.T.);
#907=CARTESIAN_POINT('',(5.00000000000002,8.,530.));
#908=DIRECTION('',(0.,1.,0.));
#909=DIRECTION('',(0.,0.,1.));
#910=AXIS2_PLACEMENT_3D('',#907,#908,#909);
#911=CIRCLE('',#910,25.);
#912=CARTESIAN_POINT('',(5.00000000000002,8.,555.));
#913=VERTEX_POINT('',#912);
#914=EDGE_CURVE('E491',#913,#913,#911,.T.);
#915=ORIENTED_EDGE('',*,*,#914,.F.);
#916=EDGE_LOOP('',(#915));
#917=FACE_BOUND('',#916,.T.);
#918=CARTESIAN_POINT('',(5.00000000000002,8.,450.));
#919=DIRECTION('',(0.,1.,0.));
#920=DIRECTION('',(0.,0.,1.));
#921=AXIS2_PLACEMENT_3D('',#918,#919,#920);
#922=CIRCLE('',#921,25.);
#923=CARTESIAN_POINT('',(5.00000000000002,8.,475.));
#924=VERTEX_POINT('',#923);
#925=EDGE_CURVE('E485',#924,#924,#922,.T.);
#926=ORIENTED_EDGE('',*,*,#925,.F.);
#927=EDGE_LOOP('',(#926));
#928=FACE_BOUND('',#927,.T.);
#929=CARTESIAN_POINT('',(5.00000000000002,8.,370.));
#930=DIRECTION('',(0.,1.,0.));
#931=DIRECTION('',(0.,0.,1.));
#932=AXIS2_PLACEMENT_3D('',#929,#930,#931);
#933=CIRCLE('',#932,25.);
#934=CARTESIAN_POINT('',(5.00000000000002,8.,395.));
#935=VERTEX_POINT('',#934);
#936=EDGE_CURVE('E479',#935,#935,#933,.T.);
#937=ORIENTED_EDGE('',*,*,#936,.F.);
#938=EDGE_LOOP('',(#937));
#939=FACE_BOUND('',#938,.T.);
#940=CARTESIAN_POINT('',(5.00000000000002,8.,290.));
#941=DIRECTION('',(0.,1.,0.));
#942=DIRECTION('',(0.,0.,1.));
#943=AXIS2_PLACEMENT_3D('',#940,#941,#942);
#944=CIRCLE('',#943,25.);
#945=CARTESIAN_POINT('',(5.00000000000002,8.,315.));
#946=VERTEX_POINT('',#945);
#947=EDGE_CURVE('E473',#946,#946,#944,.T.);
#948=ORIENTED_EDGE('',*,*,#947,.F.);
#949=EDGE_LOOP('',(#948));
#950=FACE_BOUND('',#949,.T.);
#951=CARTESIAN_POINT('',(5.00000000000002,8.,210.));
#952=DIRECTION('',(0.,1.,0.));
#953=DIRECTION('',(0.,0.,1.));
#954=AXIS2_PLACEMENT_3D('',#951,#952,#953);
#955=CIRCLE('',#954,25.);
#956=CARTESIAN_POINT('',(5.00000000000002,8.,235.));
#957=VERTEX_POINT('',#956);
#958=EDGE_CURVE('E467',#957,#957,#955,.T.);
#959=ORIENTED_EDGE('',*,*,#958,.F.);
#960=EDGE_LOOP('',(#959));
#961=FACE_BOUND('',#960,.T.);
#962=CARTESIAN_POINT('',(5.00000000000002,8.,130.));
#963=DIRECTION('',(0.,1.,0.));
#964=DIRECTION('',(0.,0.,1.));
#965=AXIS2_PLACEMENT_3D('',#962,#963,#964);
#966=CIRCLE('',#965,25.);
#967=CARTESIAN_POINT('',(5.00000000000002,8.,155.));
#968=VERTEX_POINT('',#967);
#969=EDGE_CURVE('E461',#968,#968,#966,.T.);
#970=ORIENTED_EDGE('',*,*,#969,.F.);
#971=EDGE_LOOP('',(#970));
#972=FACE_BOUND('',#971,.T.);
#973=CARTESIAN_POINT('',(5.00000000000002,8.,50.));
#974=DIRECTION('',(0.,1.,0.));
#975=DIRECTION('',(0.,0.,1.));
#976=AXIS2_PLACEMENT_3D('',#973,#974,#975);
#977=CIRCLE('',#976,25.);
#978=CARTESIAN_POINT('',(5.00000000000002,8.,75.));
#979=VERTEX_POINT('',#978);
#980=EDGE_CURVE('E450',#979,#979,#977,.T.);
#981=ORIENTED_EDGE('',*,*,#980,.F.);
#982=EDGE_LOOP('',(#981));
#983=FACE_BOUND('',#982,.T.);
#984=DIRECTION('',(-1.,0.,0.));
#985=VECTOR('',#984,1.);
#986=CARTESIAN_POINT('',(-32.,8.,0.));
#987=LINE('',#986,#985);
#988=CARTESIAN_POINT('',(-27.,8.,0.));
#989=VERTEX_POINT('',#988);
#990=EDGE_CURVE('E422',#672,#989,#987,.T.);
#991=ORIENTED_EDGE('',*,*,#990,.T.);
#992=DIRECTION('',(0.,0.,-1.));
#993=VECTOR('',#992,1.);
#994=CARTESIAN_POINT('',(-27.,8.,2100.));
#995=LINE('',#994,#993);
#996=CARTESIAN_POINT('',(-27.,8.,2100.));
#997=VERTEX_POINT('',#996);
#998=EDGE_CURVE('E48',#989,#997,#995,.F.);
#999=ORIENTED_EDGE('',*,*,#998,.T.);
#1000=DIRECTION('',(-1.,0.,0.));
#1001=VECTOR('',#1000,1.);
#1002=CARTESIAN_POINT('',(-32.,8.,2100.));
#1003=LINE('',#1002,#1001);
#1004=EDGE_CURVE('E425',#680,#997,#1003,.T.);
#1005=ORIENTED_EDGE('',*,*,#1004,.F.);
#1006=ORIENTED_EDGE('',*,*,#681,.T.);
#1007=EDGE_LOOP('',(#991,#999,#1005,#1006));
#1008=FACE_BOUND('',#1007,.T.);
#1009=ADVANCED_FACE('F399',(#708,#719,#730,#741,#752,#763,#774,#785,#796,#807,#818,#829,#840,
#851,#862,#873,#884,#895,#906,#917,#928,#939,#950,#961,#972,#983,#1008),#697,.F.);
#1010=CARTESIAN_POINT('',(-32.,80.,2100.));
#1011=DIRECTION('',(-1.,0.,0.));
#1012=DIRECTION('',(0.,-1.,0.));
#1013=AXIS2_PLACEMENT_3D('',#1010,#1011,#1012);
#1014=PLANE('',#1013);
#1015=CARTESIAN_POINT('',(-32.,45.,130.));
#1016=DIRECTION('',(-1.,0.,0.));
#1017=DIRECTION('',(0.,-1.,0.));
#1018=AXIS2_PLACEMENT_3D('',#1015,#1016,#1017);
#1019=CIRCLE('',#1018,25.);
#1020=CARTESIAN_POINT('',(-32.,20.,130.));
#1021=VERTEX_POINT('',#1020);
#1022=EDGE_CURVE('E453',#1021,#1021,#1019,.T.);
#1023=ORIENTED_EDGE('',*,*,#1022,.T.);
#1024=EDGE_LOOP('',(#1023));
#1025=FACE_BOUND('',#1024,.T.);
#1026=CARTESIAN_POINT('',(-32.,45.,50.));
#1027=DIRECTION('',(-1.,0.,0.));
#1028=DIRECTION('',(0.,-1.,0.));
#1029=AXIS2_PLACEMENT_3D('',#1026,#1027,#1028);
#1030=CIRCLE('',#1029,25.);
#1031=CARTESIAN_POINT('',(-32.,20.,50.));
#1032=VERTEX_POINT('',#1031);
#1033=EDGE_CURVE('E132',#1032,#1032,#1030,.T.);
#1034=ORIENTED_EDGE('',*,*,#1033,.T.);
#1035=EDGE_LOOP('',(#1034));
#1036=FACE_BOUND('',#1035,.T.);
#1037=DIRECTION('',(0.,1.,0.));
#1038=VECTOR('',#1037,1.);
#1039=CARTESIAN_POINT('',(-32.,80.,2100.));
#1040=LINE('',#1039,#1038);
#1041=CARTESIAN_POINT('',(-32.,13.,2100.));
#1042=VERTEX_POINT('',#1041);
#1043=CARTESIAN_POINT('',(-32.,80.,2100.));
#1044=VERTEX_POINT('',#1043);
#1045=EDGE_CURVE('E443',#1042,#1044,#1040,.T.);
#1046=ORIENTED_EDGE('',*,*,#1045,.F.);
#1047=DIRECTION('',(0.,0.,-1.));
#1048=VECTOR('',#1047,1.);
#1049=CARTESIAN_POINT('',(-32.,13.,0.));
#1050=LINE('',#1049,#1048);
#1051=CARTESIAN_POINT('',(-32.,13.,0.));
#1052=VERTEX_POINT('',#1051);
#1053=EDGE_CURVE('E119',#1042,#1052,#1050,.T.);
#1054=ORIENTED_EDGE('',*,*,#1053,.T.);
#1055=DIRECTION('',(0.,1.,0.));
#1056=VECTOR('',#1055,1.);
#1057=CARTESIAN_POINT('',(-32.,80.,0.));
#1058=LINE('',#1057,#1056);
#1059=CARTESIAN_POINT('',(-32.,80.,0.));
#1060=VERTEX_POINT('',#1059);
#1061=EDGE_CURVE('E427',#1052,#1060,#1058,.T.);
#1062=ORIENTED_EDGE('',*,*,#1061,.T.);
#1063=DIRECTION('',(0.,0.,-1.));
#1064=VECTOR('',#1063,1.);
#1065=CARTESIAN_POINT('',(-32.,80.,2100.));
#1066=LINE('',#1065,#1064);
#1067=EDGE_CURVE('E426',#1044,#1060,#1066,.T.);
#1068=ORIENTED_EDGE('',*,*,#1067,.F.);
#1069=EDGE_LOOP('',(#1046,#1054,#1062,#1068));
#1070=FACE_BOUND('',#1069,.T.);
#1071=CARTESIAN_POINT('',(-32.,45.,210.));
#1072=DIRECTION('',(-1.,0.,0.));
#1073=DIRECTION('',(0.,-1.,0.));
#1074=AXIS2_PLACEMENT_3D('',#1071,#1072,#1073);
#1075=CIRCLE('',#1074,25.);
#1076=CARTESIAN_POINT('',(-32.,20.,210.));
#1077=VERTEX_POINT('',#1076);
#1078=EDGE_CURVE('E138',#1077,#1077,#1075,.T.);
#1079=ORIENTED_EDGE('',*,*,#1078,.T.);
#1080=EDGE_LOOP('',(#1079));
#1081=FACE_BOUND('',#1080,.T.);
#1082=CARTESIAN_POINT('',(-32.,45.,290.));
#1083=DIRECTION('',(-1.,0.,0.));
#1084=DIRECTION('',(0.,-1.,0.));
#1085=AXIS2_PLACEMENT_3D('',#1082,#1083,#1084);
#1086=CIRCLE('',#1085,25.);
#1087=CARTESIAN_POINT('',(-32.,20.,290.));
#1088=VERTEX_POINT('',#1087);
#1089=EDGE_CURVE('E144',#1088,#1088,#1086,.T.);
#1090=ORIENTED_EDGE('',*,*,#1089,.T.);
#1091=EDGE_LOOP('',(#1090));
#1092=FACE_BOUND('',#1091,.T.);
#1093=CARTESIAN_POINT('',(-32.,45.,370.));
#1094=DIRECTION('',(-1.,0.,0.));
#1095=DIRECTION('',(0.,-1.,0.));
#1096=AXIS2_PLACEMENT_3D('',#1093,#1094,#1095);
#1097=CIRCLE('',#1096,25.);
#1098=CARTESIAN_POINT('',(-32.,20.,370.));
#1099=VERTEX_POINT('',#1098);
#1100=EDGE_CURVE('E150',#1099,#1099,#1097,.T.);
#1101=ORIENTED_EDGE('',*,*,#1100,.T.);
#1102=EDGE_LOOP('',(#1101));
#1103=FACE_BOUND('',#1102,.T.);
#1104=CARTESIAN_POINT('',(-32.,45.,450.));
#1105=DIRECTION('',(-1.,0.,0.));
#1106=DIRECTION('',(0.,-1.,0.));
#1107=AXIS2_PLACEMENT_3D('',#1104,#1105,#1106);
#1108=CIRCLE('',#1107,25.);
#1109=CARTESIAN_POINT('',(-32.,20.,450.));
#1110=VERTEX_POINT('',#1109);
#1111=EDGE_CURVE('E156',#1110,#1110,#1108,.T.);
#1112=ORIENTED_EDGE('',*,*,#1111,.T.);
#1113=EDGE_LOOP('',(#1112));
#1114=FACE_BOUND('',#1113,.T.);
#1115=CARTESIAN_POINT('',(-32.,45.,530.));
#1116=DIRECTION('',(-1.,0.,0.));
#1117=DIRECTION('',(0.,-1.,0.));
#1118=AXIS2_PLACEMENT_3D('',#1115,#1116,#1117);
#1119=CIRCLE('',#1118,25.);
#1120=CARTESIAN_POINT('',(-32.,20.,530.));
#1121=VERTEX_POINT('',#1120);
#1122=EDGE_CURVE('E162',#1121,#1121,#1119,.T.);
#1123=ORIENTED_EDGE('',*,*,#1122,.T.);
#1124=EDGE_LOOP('',(#1123));
#1125=FACE_BOUND('',#1124,.T.);
#1126=CARTESIAN_POINT('',(-32.,45.,610.));
#1127=DIRECTION('',(-1.,0.,0.));
#1128=DIRECTION('',(0.,-1.,0.));
#1129=AXIS2_PLACEMENT_3D('',#1126,#1127,#1128);
#1130=CIRCLE('',#1129,25.);
#1131=CARTESIAN_POINT('',(-32.,20.,610.));
#1132=VERTEX_POINT('',#1131);
#1133=EDGE_CURVE('E168',#1132,#1132,#1130,.T.);
#1134=ORIENTED_EDGE('',*,*,#1133,.T.);
#1135=EDGE_LOOP('',(#1134));
#1136=FACE_BOUND('',#1135,.T.);
#1137=CARTESIAN_POINT('',(-32.,45.,690.));
#1138=DIRECTION('',(-1.,0.,0.));
#1139=DIRECTION('',(0.,-1.,0.));
#1140=AXIS2_PLACEMENT_3D('',#1137,#1138,#1139);
#1141=CIRCLE('',#1140,25.);
#1142=CARTESIAN_POINT('',(-32.,20.,690.));
#1143=VERTEX_POINT('',#1142);
#1144=EDGE_CURVE('E174',#1143,#1143,#1141,.T.);
#1145=ORIENTED_EDGE('',*,*,#1144,.T.);
#1146=EDGE_LOOP('',(#1145));
#1147=FACE_BOUND('',#1146,.T.);
#1148=CARTESIAN_POINT('',(-32.,45.,770.));
#1149=DIRECTION('',(-1.,0.,0.));
#1150=DIRECTION('',(0.,-1.,0.));
#1151=AXIS2_PLACEMENT_3D('',#1148,#1149,#1150);
#1152=CIRCLE('',#1151,25.);
#1153=CARTESIAN_POINT('',(-32.,20.,770.));
#1154=VERTEX_POINT('',#1153);
#1155=EDGE_CURVE('E180',#1154,#1154,#1152,.T.);
#1156=ORIENTED_EDGE('',*,*,#1155,.T.);
#1157=EDGE_LOOP('',(#1156));
#1158=FACE_BOUND('',#1157,.T.);
#1159=CARTESIAN_POINT('',(-32.,45.,850.));
#1160=DIRECTION('',(-1.,0.,0.));
#1161=DIRECTION('',(0.,-1.,0.));
#1162=AXIS2_PLACEMENT_3D('',#1159,#1160,#1161);
#1163=CIRCLE('',#1162,25.);
#1164=CARTESIAN_POINT('',(-32.,20.,850.));
#1165=VERTEX_POINT('',#1164);
#1166=EDGE_CURVE('E186',#1165,#1165,#1163,.T.);
#1167=ORIENTED_EDGE('',*,*,#1166,.T.);
#1168=EDGE_LOOP('',(#1167));
#1169=FACE_BOUND('',#1168,.T.);
#1170=CARTESIAN_POINT('',(-32.,45.,930.));
#1171=DIRECTION('',(-1.,0.,0.));
#1172=DIRECTION('',(0.,-1.,0.));
#1173=AXIS2_PLACEMENT_3D('',#1170,#1171,#1172);
#1174=CIRCLE('',#1173,25.);
#1175=CARTESIAN_POINT('',(-32.,20.,930.));
#1176=VERTEX_POINT('',#1175);
#1177=EDGE_CURVE('E192',#1176,#1176,#1174,.T.);
#1178=ORIENTED_EDGE('',*,*,#1177,.T.);
#1179=EDGE_LOOP('',(#1178));
#1180=FACE_BOUND('',#1179,.T.);
#1181=CARTESIAN_POINT('',(-32.,45.,1010.));
#1182=DIRECTION('',(-1.,0.,0.));
#1183=DIRECTION('',(0.,-1.,0.));
#1184=AXIS2_PLACEMENT_3D('',#1181,#1182,#1183);
#1185=CIRCLE('',#1184,25.);
#1186=CARTESIAN_POINT('',(-32.,20.,1010.));
#1187=VERTEX_POINT('',#1186);
#1188=EDGE_CURVE('E198',#1187,#1187,#1185,.T.);
#1189=ORIENTED_EDGE('',*,*,#1188,.T.);
#1190=EDGE_LOOP('',(#1189));
#1191=FACE_BOUND('',#1190,.T.);
#1192=CARTESIAN_POINT('',(-32.,45.,1090.));
#1193=DIRECTION('',(-1.,0.,0.));
#1194=DIRECTION('',(0.,-1.,0.));
#1195=AXIS2_PLACEMENT_3D('',#1192,#1193,#1194);
#1196=CIRCLE('',#1195,25.);
#1197=CARTESIAN_POINT('',(-32.,20.,1090.));
#1198=VERTEX_POINT('',#1197);
#1199=EDGE_CURVE('E204',#1198,#1198,#1196,.T.);
#1200=ORIENTED_EDGE('',*,*,#1199,.T.);
#1201=EDGE_LOOP('',(#1200));
#1202=FACE_BOUND('',#1201,.T.);
#1203=CARTESIAN_POINT('',(-32.,45.,1170.));
#1204=DIRECTION('',(-1.,0.,0.));
#1205=DIRECTION('',(0.,-1.,0.));
#1206=AXIS2_PLACEMENT_3D('',#1203,#1204,#1205);
#1207=CIRCLE('',#1206,25.);
#1208=CARTESIAN_POINT('',(-32.,20.,1170.));
#1209=VERTEX_POINT('',#1208);
#1210=EDGE_CURVE('E210',#1209,#1209,#1207,.T.);
#1211=ORIENTED_EDGE('',*,*,#1210,.T.);
#1212=EDGE_LOOP('',(#1211));
#1213=FACE_BOUND('',#1212,.T.);
#1214=CARTESIAN_POINT('',(-32.,45.,1250.));
#1215=DIRECTION('',(-1.,0.,0.));
#1216=DIRECTION('',(0.,-1.,0.));
#1217=AXIS2_PLACEMENT_3D('',#1214,#1215,#1216);
#1218=CIRCLE('',#1217,25.);
#1219=CARTESIAN_POINT('',(-32.,20.,1250.));
#1220=VERTEX_POINT('',#1219);
#1221=EDGE_CURVE('E216',#1220,#1220,#1218,.T.);
#1222=ORIENTED_EDGE('',*,*,#1221,.T.);
#1223=EDGE_LOOP('',(#1222));
#1224=FACE_BOUND('',#1223,.T.);
#1225=CARTESIAN_POINT('',(-32.,45.,1330.));
#1226=DIRECTION('',(-1.,0.,0.));
#1227=DIRECTION('',(0.,-1.,0.));
#1228=AXIS2_PLACEMENT_3D('',#1225,#1226,#1227);
#1229=CIRCLE('',#1228,25.);
#1230=CARTESIAN_POINT('',(-32.,20.,1330.));
#1231=VERTEX_POINT('',#1230);
#1232=EDGE_CURVE('E222',#1231,#1231,#1229,.T.);
#1233=ORIENTED_EDGE('',*,*,#1232,.T.);
#1234=EDGE_LOOP('',(#1233));
#1235=FACE_BOUND('',#1234,.T.);
#1236=CARTESIAN_POINT('',(-32.,45.,1410.));
#1237=DIRECTION('',(-1.,0.,0.));
#1238=DIRECTION('',(0.,-1.,0.));
#1239=AXIS2_PLACEMENT_3D('',#1236,#1237,#1238);
#1240=CIRCLE('',#1239,25.);
#1241=CARTESIAN_POINT('',(-32.,20.,1410.));
#1242=VERTEX_POINT('',#1241);
#1243=EDGE_CURVE('E228',#1242,#1242,#1240,.T.);
#1244=ORIENTED_EDGE('',*,*,#1243,.T.);
#1245=EDGE_LOOP('',(#1244));
#1246=FACE_BOUND('',#1245,.T.);
#1247=CARTESIAN_POINT('',(-32.,45.,1490.));
#1248=DIRECTION('',(-1.,0.,0.));
#1249=DIRECTION('',(0.,-1.,0.));
#1250=AXIS2_PLACEMENT_3D('',#1247,#1248,#1249);
#1251=CIRCLE('',#1250,25.);
#1252=CARTESIAN_POINT('',(-32.,20.,1490.));
#1253=VERTEX_POINT('',#1252);
#1254=EDGE_CURVE('E234',#1253,#1253,#1251,.T.);
#1255=ORIENTED_EDGE('',*,*,#1254,.T.);
#1256=EDGE_LOOP('',(#1255));
#1257=FACE_BOUND('',#1256,.T.);
#1258=CARTESIAN_POINT('',(-32.,45.,1570.));
#1259=DIRECTION('',(-1.,0.,0.));
#1260=DIRECTION('',(0.,-1.,0.));
#1261=AXIS2_PLACEMENT_3D('',#1258,#1259,#1260);
#1262=CIRCLE('',#1261,25.);
#1263=CARTESIAN_POINT('',(-32.,20.,1570.));
#1264=VERTEX_POINT('',#1263);
#1265=EDGE_CURVE('E240',#1264,#1264,#1262,.T.);
#1266=ORIENTED_EDGE('',*,*,#1265,.T.);
#1267=EDGE_LOOP('',(#1266));
#1268=FACE_BOUND('',#1267,.T.);
#1269=CARTESIAN_POINT('',(-32.,45.,1650.));
#1270=DIRECTION('',(-1.,0.,0.));
#1271=DIRECTION('',(0.,-1.,0.));
#1272=AXIS2_PLACEMENT_3D('',#1269,#1270,#1271);
#1273=CIRCLE('',#1272,25.);
#1274=CARTESIAN_POINT('',(-32.,20.,1650.));
#1275=VERTEX_POINT('',#1274);
#1276=EDGE_CURVE('E246',#1275,#1275,#1273,.T.);
#1277=ORIENTED_EDGE('',*,*,#1276,.T.);
#1278=EDGE_LOOP('',(#1277));
#1279=FACE_BOUND('',#1278,.T.);
#1280=CARTESIAN_POINT('',(-32.,45.,1730.));
#1281=DIRECTION('',(-1.,0.,0.));
#1282=DIRECTION('',(0.,-1.,0.));
#1283=AXIS2_PLACEMENT_3D('',#1280,#1281,#1282);
#1284=CIRCLE('',#1283,25.);
#1285=CARTESIAN_POINT('',(-32.,20.,1730.));
#1286=VERTEX_POINT('',#1285);
#1287=EDGE_CURVE('E252',#1286,#1286,#1284,.T.);
#1288=ORIENTED_EDGE('',*,*,#1287,.T.);
#1289=EDGE_LOOP('',(#1288));
#1290=FACE_BOUND('',#1289,.T.);
#1291=CARTESIAN_POINT('',(-32.,45.,1810.));
#1292=DIRECTION('',(-1.,0.,0.));
#1293=DIRECTION('',(0.,-1.,0.));
#1294=AXIS2_PLACEMENT_3D('',#1291,#1292,#1293);
#1295=CIRCLE('',#1294,25.);
#1296=CARTESIAN_POINT('',(-32.,20.,1810.));
#1297=VERTEX_POINT('',#1296);
#1298=EDGE_CURVE('E258',#1297,#1297,#1295,.T.);
#1299=ORIENTED_EDGE('',*,*,#1298,.T.);
#1300=EDGE_LOOP('',(#1299));
#1301=FACE_BOUND('',#1300,.T.);
#1302=CARTESIAN_POINT('',(-32.,45.,1890.));
#1303=DIRECTION('',(-1.,0.,0.));
#1304=DIRECTION('',(0.,-1.,0.));
#1305=AXIS2_PLACEMENT_3D('',#1302,#1303,#1304);
#1306=CIRCLE('',#1305,25.);
#1307=CARTESIAN_POINT('',(-32.,20.,1890.));
#1308=VERTEX_POINT('',#1307);
#1309=EDGE_CURVE('E264',#1308,#1308,#1306,.T.);
#1310=ORIENTED_EDGE('',*,*,#1309,.T.);
#1311=EDGE_LOOP('',(#1310));
#1312=FACE_BOUND('',#1311,.T.);
#1313=CARTESIAN_POINT('',(-32.,45.,1970.));
#1314=DIRECTION('',(-1.,0.,0.));
#1315=DIRECTION('',(0.,-1.,0.));
#1316=AXIS2_PLACEMENT_3D('',#1313,#1314,#1315);
#1317=CIRCLE('',#1316,25.);
#1318=CARTESIAN_POINT('',(-32.,20.,1970.));
#1319=VERTEX_POINT('',#1318);
#1320=EDGE_CURVE('E270',#1319,#1319,#1317,.T.);
#1321=ORIENTED_EDGE('',*,*,#1320,.T.);
#1322=EDGE_LOOP('',(#1321));
#1323=FACE_BOUND('',#1322,.T.);
#1324=CARTESIAN_POINT('',(-32.,45.,2050.));
#1325=DIRECTION('',(-1.,0.,0.));
#1326=DIRECTION('',(0.,-1.,0.));
#1327=AXIS2_PLACEMENT_3D('',#1324,#1325,#1326);
#1328=CIRCLE('',#1327,25.);
#1329=CARTESIAN_POINT('',(-32.,20.,2050.));
#1330=VERTEX_POINT('',#1329);
#1331=EDGE_CURVE('E11',#1330,#1330,#1328,.T.);
#1332=ORIENTED_EDGE('',*,*,#1331,.T.);
#1333=EDGE_LOOP('',(#1332));
#1334=FACE_BOUND('',#1333,.T.);
#1335=ADVANCED_FACE('F395',(#1025,#1036,#1070,#1081,#1092,#1103,#1114,#1125,#1136,#1147,#1158,
#1169,#1180,#1191,#1202,#1213,#1224,#1235,#1246,#1257,#1268,#1279,#1290,#1301,#1312,#1323,
#1334),#1014,.F.);
#1336=CARTESIAN_POINT('',(-40.,80.,2100.));
#1337=DIRECTION('',(0.,-1.,0.));
#1338=DIRECTION('',(0.,0.,-1.));
#1339=AXIS2_PLACEMENT_3D('',#1336,#1337,#1338);
#1340=PLANE('',#1339);
#1341=DIRECTION('',(-1.,0.,0.));
#1342=VECTOR('',#1341,1.);
#1343=CARTESIAN_POINT('',(-40.,80.,0.));
#1344=LINE('',#1343,#1342);
#1345=EDGE_CURVE('E114',#1060,#51,#1344,.T.);
#1346=ORIENTED_EDGE('',*,*,#1345,.T.);
#1347=ORIENTED_EDGE('',*,*,#76,.F.);
#1348=DIRECTION('',(-1.,0.,0.));
#1349=VECTOR('',#1348,1.);
#1350=CARTESIAN_POINT('',(-40.,80.,2100.));
#1351=LINE('',#1350,#1349);
#1352=EDGE_CURVE('E110',#1044,#69,#1351,.T.);
#1353=ORIENTED_EDGE('',*,*,#1352,.F.);
#1354=ORIENTED_EDGE('',*,*,#1067,.T.);
#1355=EDGE_LOOP('',(#1346,#1347,#1353,#1354));
#1356=FACE_BOUND('',#1355,.T.);
#1357=ADVANCED_FACE('F398',(#1356),#1340,.F.);
#1358=CARTESIAN_POINT('',(-40.,0.,2100.));
#1359=DIRECTION('',(0.,0.,1.));
#1360=DIRECTION('',(1.,0.,0.));
#1361=AXIS2_PLACEMENT_3D('',#1358,#1359,#1360);
#1362=PLANE('',#1361);
#1363=ORIENTED_EDGE('',*,*,#70,.T.);
#1364=ORIENTED_EDGE('',*,*,#656,.T.);
#1365=ORIENTED_EDGE('',*,*,#687,.T.);
#1366=ORIENTED_EDGE('',*,*,#1004,.T.);
#1367=CARTESIAN_POINT('',(-27.,13.,2100.));
#1368=DIRECTION('',(0.,0.,1.));
#1369=DIRECTION('',(1.,0.,0.));
#1370=AXIS2_PLACEMENT_3D('',#1367,#1368,#1369);
#1371=CIRCLE('',#1370,5.);
#1372=EDGE_CURVE('E129',#997,#1042,#1371,.F.);
#1373=ORIENTED_EDGE('',*,*,#1372,.T.);
#1374=ORIENTED_EDGE('',*,*,#1045,.T.);
#1375=ORIENTED_EDGE('',*,*,#1352,.T.);
#1376=EDGE_LOOP('',(#1363,#1364,#1365,#1366,#1373,#1374,#1375));
#1377=FACE_BOUND('',#1376,.T.);
#1378=ADVANCED_FACE('F108',(#1377),#1362,.T.);
#1379=CARTESIAN_POINT('',(-40.,0.,0.));
#1380=DIRECTION('',(0.,0.,1.));
#1381=DIRECTION('',(1.,0.,0.));
#1382=AXIS2_PLACEMENT_3D('',#1379,#1380,#1381);
#1383=PLANE('',#1382);
#1384=ORIENTED_EDGE('',*,*,#54,.F.);
#1385=ORIENTED_EDGE('',*,*,#1345,.F.);
#1386=ORIENTED_EDGE('',*,*,#1061,.F.);
#1387=CARTESIAN_POINT('',(-27.,13.,0.));
#1388=DIRECTION('',(0.,0.,1.));
#1389=DIRECTION('',(1.,0.,0.));
#1390=AXIS2_PLACEMENT_3D('',#1387,#1388,#1389);
#1391=CIRCLE('',#1390,5.);
#1392=EDGE_CURVE('E56',#1052,#989,#1391,.T.);
#1393=ORIENTED_EDGE('',*,*,#1392,.T.);
#1394=ORIENTED_EDGE('',*,*,#990,.F.);
#1395=ORIENTED_EDGE('',*,*,#673,.F.);
#1396=ORIENTED_EDGE('',*,*,#642,.F.);
#1397=EDGE_LOOP('',(#1384,#1385,#1386,#1393,#1394,#1395,#1396));
#1398=FACE_BOUND('',#1397,.T.);
#1399=ADVANCED_FACE('F294',(#1398),#1383,.F.);
#1400=CARTESIAN_POINT('',(-27.,13.,2100.));
#1401=DIRECTION('',(0.,0.,1.));
#1402=DIRECTION('',(1.,0.,0.));
#1403=AXIS2_PLACEMENT_3D('',#1400,#1401,#1402);
#1404=CYLINDRICAL_SURFACE('',#1403,5.);
#1405=ORIENTED_EDGE('',*,*,#1372,.F.);
#1406=ORIENTED_EDGE('',*,*,#998,.F.);
#1407=ORIENTED_EDGE('',*,*,#1392,.F.);
#1408=ORIENTED_EDGE('',*,*,#1053,.F.);
#1409=EDGE_LOOP('',(#1405,#1406,#1407,#1408));
#1410=FACE_BOUND('',#1409,.T.);
#1411=ADVANCED_FACE('F290',(#1410),#1404,.F.);
#1412=CARTESIAN_POINT('',(40.,45.,50.));
#1413=DIRECTION('',(-1.,0.,0.));
#1414=DIRECTION('',(0.,-1.,0.));
#1415=AXIS2_PLACEMENT_3D('',#1412,#1413,#1414);
#1416=CYLINDRICAL_SURFACE('',#1415,25.);
#1417=CARTESIAN_POINT('',(-40.,20.,50.));
#1418=CARTESIAN_POINT('',(-39.9166666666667,20.,50.));
#1419=CARTESIAN_POINT('',(-39.8333333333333,20.,50.));
#1420=CARTESIAN_POINT('',(-39.6666666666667,20.,50.));
#1421=CARTESIAN_POINT('',(-39.5833333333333,20.,50.));
#1422=CARTESIAN_POINT('',(-39.4166666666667,20.,50.));
#1423=CARTESIAN_POINT('',(-39.3333333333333,20.,50.));
#1424=CARTESIAN_POINT('',(-39.1666666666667,20.,50.));
#1425=CARTESIAN_POINT('',(-39.0833333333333,20.,50.));
#1426=CARTESIAN_POINT('',(-38.9166666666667,20.,50.));
#1427=CARTESIAN_POINT('',(-38.8333333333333,20.,50.));
#1428=CARTESIAN_POINT('',(-38.6666666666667,20.,50.));
#1429=CARTESIAN_POINT('',(-38.5833333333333,20.,50.));
#1430=CARTESIAN_POINT('',(-38.4166666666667,20.,50.));
#1431=CARTESIAN_POINT('',(-38.3333333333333,20.,50.));
#1432=CARTESIAN_POINT('',(-38.1666666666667,20.,50.));
#1433=CARTESIAN_POINT('',(-38.0833333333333,20.,50.));
#1434=CARTESIAN_POINT('',(-37.9166666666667,20.,50.));
#1435=CARTESIAN_POINT('',(-37.8333333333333,20.,50.));
#1436=CARTESIAN_POINT('',(-37.6666666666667,20.,50.));
#1437=CARTESIAN_POINT('',(-37.5833333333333,20.,50.));
#1438=CARTESIAN_POINT('',(-37.4166666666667,20.,50.));
#1439=CARTESIAN_POINT('',(-37.3333333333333,20.,50.));
#1440=CARTESIAN_POINT('',(-37.1666666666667,20.,50.));
#1441=CARTESIAN_POINT('',(-37.0833333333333,20.,50.));
#1442=CARTESIAN_POINT('',(-36.9166666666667,20.,50.));
#1443=CARTESIAN_POINT('',(-36.8333333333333,20.,50.));
#1444=CARTESIAN_POINT('',(-36.6666666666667,20.,50.));
#1445=CARTESIAN_POINT('',(-36.5833333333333,20.,50.));
#1446=CARTESIAN_POINT('',(-36.4166666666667,20.,50.));
#1447=CARTESIAN_POINT('',(-36.3333333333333,20.,50.));
#1448=CARTESIAN_POINT('',(-36.1666666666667,20.,50.));
#1449=CARTESIAN_POINT('',(-36.0833333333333,20.,50.));
#1450=CARTESIAN_POINT('',(-35.9166666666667,20.,50.));
#1451=CARTESIAN_POINT('',(-35.8333333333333,20.,50.));
#1452=CARTESIAN_POINT('',(-35.6666666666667,20.,50.));
#1453=CARTESIAN_POINT('',(-35.5833333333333,20.,50.));
#1454=CARTESIAN_POINT('',(-35.4166666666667,20.,50.));
#1455=CARTESIAN_POINT('',(-35.3333333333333,20.,50.));
#1456=CARTESIAN_POINT('',(-35.1666666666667,20.,50.));
#1457=CARTESIAN_POINT('',(-35.0833333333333,20.,50.));
#1458=CARTESIAN_POINT('',(-34.9166666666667,20.,50.));
#1459=CARTESIAN_POINT('',(-34.8333333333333,20.,50.));
#1460=CARTESIAN_POINT('',(-34.6666666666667,20.,50.));
#1461=CARTESIAN_POINT('',(-34.5833333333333,20.,50.));
#1462=CARTESIAN_POINT('',(-34.4166666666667,20.,50.));
#1463=CARTESIAN_POINT('',(-34.3333333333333,20.,50.));
#1464=CARTESIAN_POINT('',(-34.1666666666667,20.,50.));
#1465=CARTESIAN_POINT('',(-34.0833333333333,20.,50.));
#1466=CARTESIAN_POINT('',(-33.9166666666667,20.,50.));
#1467=CARTESIAN_POINT('',(-33.8333333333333,20.,50.));
#1468=CARTESIAN_POINT('',(-33.6666666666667,20.,50.));
#1469=CARTESIAN_POINT('',(-33.5833333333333,20.,50.));
#1470=CARTESIAN_POINT('',(-33.4166666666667,20.,50.));
#1471=CARTESIAN_POINT('',(-33.3333333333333,20.,50.));
#1472=CARTESIAN_POINT('',(-33.1666666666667,20.,50.));
#1473=CARTESIAN_POINT('',(-33.0833333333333,20.,50.));
#1474=CARTESIAN_POINT('',(-32.9166666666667,20.,50.));
#1475=CARTESIAN_POINT('',(-32.8333333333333,20.,50.));
#1476=CARTESIAN_POINT('',(-32.6666666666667,20.,50.));
#1477=CARTESIAN_POINT('',(-32.5833333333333,20.,50.));
#1478=CARTESIAN_POINT('',(-32.4166666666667,20.,50.));
#1479=CARTESIAN_POINT('',(-32.3333333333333,20.,50.));
#1480=CARTESIAN_POINT('',(-32.1666666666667,20.,50.));
#1481=CARTESIAN_POINT('',(-32.0833333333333,20.,50.));
#1482=CARTESIAN_POINT('',(-32.,20.,50.));
#1483=B_SPLINE_CURVE_WITH_KNOTS('',3,(#1417,#1418,#1419,#1420,#1421,#1422,#1423,#1424,#1425,
#1426,#1427,#1428,#1429,#1430,#1431,#1432,#1433,#1434,#1435,#1436,#1437,#1438,#1439,#1440,#1441,
#1442,#1443,#1444,#1445,#1446,#1447,#1448,#1449,#1450,#1451,#1452,#1453,#1454,#1455,#1456,#1457,
#1458,#1459,#1460,#1461,#1462,#1463,#1464,#1465,#1466,#1467,#1468,#1469,#1470,#1471,#1472,#1473,
#1474,#1475,#1476,#1477,#1478,#1479,#1480,#1481,#1482),.UNSPECIFIED.,.F.,.F.,(4,2,2,2,2,2,2,2,2,
2,2,2,2,2,2,2,2,2,2,2,2,2,2,2,2,2,2,2,2,2,2,2,4),(0.,0.25,0.5,0.750000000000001,1.,1.25,1.5,
1.75,2.,2.25,2.5,2.75,3.,3.25,3.5,3.75,4.,4.25,4.5,4.75,5.,5.25,5.50000000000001,
5.75000000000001,6.00000000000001,6.25000000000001,6.50000000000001,6.75000000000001,
7.00000000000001,7.25000000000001,7.50000000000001,7.75000000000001,8.00000000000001),.UNSPECIFIED.);
#1484=EDGE_CURVE('BSEAM293',#41,#1032,#1483,.T.);
#1485=ORIENTED_EDGE('',*,*,#42,.T.);
#1486=ORIENTED_EDGE('',*,*,#1033,.F.);
#1487=ORIENTED_EDGE('',*,*,#1484,.T.);
#1488=ORIENTED_EDGE('',*,*,#1484,.F.);
#1489=EDGE_LOOP('',(#1485,#1487,#1486,#1488));
#1490=FACE_BOUND('',#1489,.T.);
#1491=ADVANCED_FACE('F293',(#1490),#1416,.F.);
#1492=CARTESIAN_POINT('',(5.00000000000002,0.,50.));
#1493=DIRECTION('',(0.,1.,0.));
#1494=DIRECTION('',(0.,0.,1.));
#1495=AXIS2_PLACEMENT_3D('',#1492,#1493,#1494);
#1496=CYLINDRICAL_SURFACE('',#1495,25.);
#1497=ORIENTED_EDGE('',*,*,#632,.F.);
#1498=EDGE_LOOP('',(#1497));
#1499=FACE_BOUND('',#1498,.T.);
#1500=ORIENTED_EDGE('',*,*,#980,.T.);
#1501=EDGE_LOOP('',(#1500));
#1502=FACE_BOUND('',#1501,.T.);
#1503=ADVANCED_FACE('F669',(#1499,#1502),#1496,.F.);
#1504=CARTESIAN_POINT('',(40.,45.,130.));
#1505=DIRECTION('',(-1.,0.,0.));
#1506=DIRECTION('',(0.,-1.,0.));
#1507=AXIS2_PLACEMENT_3D('',#1504,#1505,#1506);
#1508=CYLINDRICAL_SURFACE('',#1507,25.);
#1509=CARTESIAN_POINT('',(-40.,20.,130.));
#1510=CARTESIAN_POINT('',(-39.9166666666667,20.,130.));
#1511=CARTESIAN_POINT('',(-39.8333333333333,20.,130.));
#1512=CARTESIAN_POINT('',(-39.6666666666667,20.,130.));
#1513=CARTESIAN_POINT('',(-39.5833333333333,20.,130.));
#1514=CARTESIAN_POINT('',(-39.4166666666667,20.,130.));
#1515=CARTESIAN_POINT('',(-39.3333333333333,20.,130.));
#1516=CARTESIAN_POINT('',(-39.1666666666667,20.,130.));
#1517=CARTESIAN_POINT('',(-39.0833333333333,20.,130.));
#1518=CARTESIAN_POINT('',(-38.9166666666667,20.,130.));
#1519=CARTESIAN_POINT('',(-38.8333333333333,20.,130.));
#1520=CARTESIAN_POINT('',(-38.6666666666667,20.,130.));
#1521=CARTESIAN_POINT('',(-38.5833333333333,20.,130.));
#1522=CARTESIAN_POINT('',(-38.4166666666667,20.,130.));
#1523=CARTESIAN_POINT('',(-38.3333333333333,20.,130.));
#1524=CARTESIAN_POINT('',(-38.1666666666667,20.,130.));
#1525=CARTESIAN_POINT('',(-38.0833333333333,20.,130.));
#1526=CARTESIAN_POINT('',(-37.9166666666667,20.,130.));
#1527=CARTESIAN_POINT('',(-37.8333333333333,20.,130.));
#1528=CARTESIAN_POINT('',(-37.6666666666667,20.,130.));
#1529=CARTESIAN_POINT('',(-37.5833333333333,20.,130.));
#1530=CARTESIAN_POINT('',(-37.4166666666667,20.,130.));
#1531=CARTESIAN_POINT('',(-37.3333333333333,20.,130.));
#1532=CARTESIAN_POINT('',(-37.1666666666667,20.,130.));
#1533=CARTESIAN_POINT('',(-37.0833333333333,20.,130.));
#1534=CARTESIAN_POINT('',(-36.9166666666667,20.,130.));
#1535=CARTESIAN_POINT('',(-36.8333333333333,20.,130.));
#1536=CARTESIAN_POINT('',(-36.6666666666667,20.,130.));
#1537=CARTESIAN_POINT('',(-36.5833333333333,20.,130.));
#1538=CARTESIAN_POINT('',(-36.4166666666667,20.,130.));
#1539=CARTESIAN_POINT('',(-36.3333333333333,20.,130.));
#1540=CARTESIAN_POINT('',(-36.1666666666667,20.,130.));
#1541=CARTESIAN_POINT('',(-36.0833333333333,20.,130.));
#1542=CARTESIAN_POINT('',(-35.9166666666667,20.,130.));
#1543=CARTESIAN_POINT('',(-35.8333333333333,20.,130.));
#1544=CARTESIAN_POINT('',(-35.6666666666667,20.,130.));
#1545=CARTESIAN_POINT('',(-35.5833333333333,20.,130.));
#1546=CARTESIAN_POINT('',(-35.4166666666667,20.,130.));
#1547=CARTESIAN_POINT('',(-35.3333333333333,20.,130.));
#1548=CARTESIAN_POINT('',(-35.1666666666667,20.,130.));
#1549=CARTESIAN_POINT('',(-35.0833333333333,20.,130.));
#1550=CARTESIAN_POINT('',(-34.9166666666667,20.,130.));
#1551=CARTESIAN_POINT('',(-34.8333333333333,20.,130.));
#1552=CARTESIAN_POINT('',(-34.6666666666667,20.,130.));
#1553=CARTESIAN_POINT('',(-34.5833333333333,20.,130.));
#1554=CARTESIAN_POINT('',(-34.4166666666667,20.,130.));
#1555=CARTESIAN_POINT('',(-34.3333333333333,20.,130.));
#1556=CARTESIAN_POINT('',(-34.1666666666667,20.,130.));
#1557=CARTESIAN_POINT('',(-34.0833333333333,20.,130.));
#1558=CARTESIAN_POINT('',(-33.9166666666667,20.,130.));
#1559=CARTESIAN_POINT('',(-33.8333333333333,20.,130.));
#1560=CARTESIAN_POINT('',(-33.6666666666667,20.,130.));
#1561=CARTESIAN_POINT('',(-33.5833333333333,20.,130.));
#1562=CARTESIAN_POINT('',(-33.4166666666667,20.,130.));
#1563=CARTESIAN_POINT('',(-33.3333333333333,20.,130.));
#1564=CARTESIAN_POINT('',(-33.1666666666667,20.,130.));
#1565=CARTESIAN_POINT('',(-33.0833333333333,20.,130.));
#1566=CARTESIAN_POINT('',(-32.9166666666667,20.,130.));
#1567=CARTESIAN_POINT('',(-32.8333333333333,20.,130.));
#1568=CARTESIAN_POINT('',(-32.6666666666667,20.,130.));
#1569=CARTESIAN_POINT('',(-32.5833333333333,20.,130.));
#1570=CARTESIAN_POINT('',(-32.4166666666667,20.,130.));
#1571=CARTESIAN_POINT('',(-32.3333333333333,20.,130.));
#1572=CARTESIAN_POINT('',(-32.1666666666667,20.,130.));
#1573=CARTESIAN_POINT('',(-32.0833333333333,20.,130.));
#1574=CARTESIAN_POINT('',(-32.,20.,130.));
#1575=B_SPLINE_CURVE_WITH_KNOTS('',3,(#1509,#1510,#1511,#1512,#1513,#1514,#1515,#1516,#1517,
#1518,#1519,#1520,#1521,#1522,#1523,#1524,#1525,#1526,#1527,#1528,#1529,#1530,#1531,#1532,#1533,
#1534,#1535,#1536,#1537,#1538,#1539,#1540,#1541,#1542,#1543,#1544,#1545,#1546,#1547,#1548,#1549,
#1550,#1551,#1552,#1553,#1554,#1555,#1556,#1557,#1558,#1559,#1560,#1561,#1562,#1563,#1564,#1565,
#1566,#1567,#1568,#1569,#1570,#1571,#1572,#1573,#1574),.UNSPECIFIED.,.F.,.F.,(4,2,2,2,2,2,2,2,2,
2,2,2,2,2,2,2,2,2,2,2,2,2,2,2,2,2,2,2,2,2,2,2,4),(0.,0.25,0.5,0.750000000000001,1.,1.25,1.5,
1.75,2.,2.25,2.5,2.75,3.,3.25,3.5,3.75,4.,4.25,4.5,4.75,5.,5.25,5.50000000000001,
5.75000000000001,6.00000000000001,6.25000000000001,6.50000000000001,6.75000000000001,
7.00000000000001,7.25000000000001,7.50000000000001,7.75000000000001,8.00000000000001),.UNSPECIFIED.);
#1576=EDGE_CURVE('BSEAM300',#30,#1021,#1575,.T.);
#1577=ORIENTED_EDGE('',*,*,#31,.T.);
#1578=ORIENTED_EDGE('',*,*,#1022,.F.);
#1579=ORIENTED_EDGE('',*,*,#1576,.T.);
#1580=ORIENTED_EDGE('',*,*,#1576,.F.);
#1581=EDGE_LOOP('',(#1577,#1579,#1578,#1580));
#1582=FACE_BOUND('',#1581,.T.);
#1583=ADVANCED_FACE('F300',(#1582),#1508,.F.);
#1584=CARTESIAN_POINT('',(40.,45.,210.));
#1585=DIRECTION('',(-1.,0.,0.));
#1586=DIRECTION('',(0.,-1.,0.));
#1587=AXIS2_PLACEMENT_3D('',#1584,#1585,#1586);
#1588=CYLINDRICAL_SURFACE('',#1587,25.);
#1589=CARTESIAN_POINT('',(-40.,20.,210.));
#1590=CARTESIAN_POINT('',(-39.9166666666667,20.,210.));
#1591=CARTESIAN_POINT('',(-39.8333333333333,20.,210.));
#1592=CARTESIAN_POINT('',(-39.6666666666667,20.,210.));
#1593=CARTESIAN_POINT('',(-39.5833333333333,20.,210.));
#1594=CARTESIAN_POINT('',(-39.4166666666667,20.,210.));
#1595=CARTESIAN_POINT('',(-39.3333333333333,20.,210.));
#1596=CARTESIAN_POINT('',(-39.1666666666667,20.,210.));
#1597=CARTESIAN_POINT('',(-39.0833333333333,20.,210.));
#1598=CARTESIAN_POINT('',(-38.9166666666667,20.,210.));
#1599=CARTESIAN_POINT('',(-38.8333333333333,20.,210.));
#1600=CARTESIAN_POINT('',(-38.6666666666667,20.,210.));
#1601=CARTESIAN_POINT('',(-38.5833333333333,20.,210.));
#1602=CARTESIAN_POINT('',(-38.4166666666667,20.,210.));
#1603=CARTESIAN_POINT('',(-38.3333333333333,20.,210.));
#1604=CARTESIAN_POINT('',(-38.1666666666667,20.,210.));
#1605=CARTESIAN_POINT('',(-38.0833333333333,20.,210.));
#1606=CARTESIAN_POINT('',(-37.9166666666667,20.,210.));
#1607=CARTESIAN_POINT('',(-37.8333333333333,20.,210.));
#1608=CARTESIAN_POINT('',(-37.6666666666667,20.,210.));
#1609=CARTESIAN_POINT('',(-37.5833333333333,20.,210.));
#1610=CARTESIAN_POINT('',(-37.4166666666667,20.,210.));
#1611=CARTESIAN_POINT('',(-37.3333333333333,20.,210.));
#1612=CARTESIAN_POINT('',(-37.1666666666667,20.,210.));
#1613=CARTESIAN_POINT('',(-37.0833333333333,20.,210.));
#1614=CARTESIAN_POINT('',(-36.9166666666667,20.,210.));
#1615=CARTESIAN_POINT('',(-36.8333333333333,20.,210.));
#1616=CARTESIAN_POINT('',(-36.6666666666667,20.,210.));
#1617=CARTESIAN_POINT('',(-36.5833333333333,20.,210.));
#1618=CARTESIAN_POINT('',(-36.4166666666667,20.,210.));
#1619=CARTESIAN_POINT('',(-36.3333333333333,20.,210.));
#1620=CARTESIAN_POINT('',(-36.1666666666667,20.,210.));
#1621=CARTESIAN_POINT('',(-36.0833333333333,20.,210.));
#1622=CARTESIAN_POINT('',(-35.9166666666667,20.,210.));
#1623=CARTESIAN_POINT('',(-35.8333333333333,20.,210.));
#1624=CARTESIAN_POINT('',(-35.6666666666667,20.,210.));
#1625=CARTESIAN_POINT('',(-35.5833333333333,20.,210.));
#1626=CARTESIAN_POINT('',(-35.4166666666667,20.,210.));
#1627=CARTESIAN_POINT('',(-35.3333333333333,20.,210.));
#1628=CARTESIAN_POINT('',(-35.1666666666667,20.,210.));
#1629=CARTESIAN_POINT('',(-35.0833333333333,20.,210.));
#1630=CARTESIAN_POINT('',(-34.9166666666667,20.,210.));
#1631=CARTESIAN_POINT('',(-34.8333333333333,20.,210.));
#1632=CARTESIAN_POINT('',(-34.6666666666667,20.,210.));
#1633=CARTESIAN_POINT('',(-34.5833333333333,20.,210.));
#1634=CARTESIAN_POINT('',(-34.4166666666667,20.,210.));
#1635=CARTESIAN_POINT('',(-34.3333333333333,20.,210.));
#1636=CARTESIAN_POINT('',(-34.1666666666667,20.,210.));
#1637=CARTESIAN_POINT('',(-34.0833333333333,20.,210.));
#1638=CARTESIAN_POINT('',(-33.9166666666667,20.,210.));
#1639=CARTESIAN_POINT('',(-33.8333333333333,20.,210.));
#1640=CARTESIAN_POINT('',(-33.6666666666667,20.,210.));
#1641=CARTESIAN_POINT('',(-33.5833333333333,20.,210.));
#1642=CARTESIAN_POINT('',(-33.4166666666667,20.,210.));
#1643=CARTESIAN_POINT('',(-33.3333333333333,20.,210.));
#1644=CARTESIAN_POINT('',(-33.1666666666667,20.,210.));
#1645=CARTESIAN_POINT('',(-33.0833333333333,20.,210.));
#1646=CARTESIAN_POINT('',(-32.9166666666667,20.,210.));
#1647=CARTESIAN_POINT('',(-32.8333333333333,20.,210.));
#1648=CARTESIAN_POINT('',(-32.6666666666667,20.,210.));
#1649=CARTESIAN_POINT('',(-32.5833333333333,20.,210.));
#1650=CARTESIAN_POINT('',(-32.4166666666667,20.,210.));
#1651=CARTESIAN_POINT('',(-32.3333333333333,20.,210.));
#1652=CARTESIAN_POINT('',(-32.1666666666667,20.,210.));
#1653=CARTESIAN_POINT('',(-32.0833333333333,20.,210.));
#1654=CARTESIAN_POINT('',(-32.,20.,210.));
#1655=B_SPLINE_CURVE_WITH_KNOTS('',3,(#1589,#1590,#1591,#1592,#1593,#1594,#1595,#1596,#1597,
#1598,#1599,#1600,#1601,#1602,#1603,#1604,#1605,#1606,#1607,#1608,#1609,#1610,#1611,#1612,#1613,
#1614,#1615,#1616,#1617,#1618,#1619,#1620,#1621,#1622,#1623,#1624,#1625,#1626,#1627,#1628,#1629,
#1630,#1631,#1632,#1633,#1634,#1635,#1636,#1637,#1638,#1639,#1640,#1641,#1642,#1643,#1644,#1645,
#1646,#1647,#1648,#1649,#1650,#1651,#1652,#1653,#1654),.UNSPECIFIED.,.F.,.F.,(4,2,2,2,2,2,2,2,2,
2,2,2,2,2,2,2,2,2,2,2,2,2,2,2,2,2,2,2,2,2,2,2,4),(0.,0.25,0.5,0.750000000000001,1.,1.25,1.5,
1.75,2.,2.25,2.5,2.75,3.,3.25,3.5,3.75,4.,4.25,4.5,4.75,5.,5.25,5.50000000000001,
5.75000000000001,6.00000000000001,6.25000000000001,6.50000000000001,6.75000000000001,
7.00000000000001,7.25000000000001,7.50000000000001,7.75000000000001,8.00000000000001),.UNSPECIFIED.);
#1656=EDGE_CURVE('BSEAM296',#86,#1077,#1655,.T.);
#1657=ORIENTED_EDGE('',*,*,#87,.T.);
#1658=ORIENTED_EDGE('',*,*,#1078,.F.);
#1659=ORIENTED_EDGE('',*,*,#1656,.T.);
#1660=ORIENTED_EDGE('',*,*,#1656,.F.);
#1661=EDGE_LOOP('',(#1657,#1659,#1658,#1660));
#1662=FACE_BOUND('',#1661,.T.);
#1663=ADVANCED_FACE('F296',(#1662),#1588,.F.);
#1664=CARTESIAN_POINT('',(40.,45.,290.));
#1665=DIRECTION('',(-1.,0.,0.));
#1666=DIRECTION('',(0.,-1.,0.));
#1667=AXIS2_PLACEMENT_3D('',#1664,#1665,#1666);
#1668=CYLINDRICAL_SURFACE('',#1667,25.);
#1669=CARTESIAN_POINT('',(-40.,20.,290.));
#1670=CARTESIAN_POINT('',(-39.9166666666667,20.,290.));
#1671=CARTESIAN_POINT('',(-39.8333333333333,20.,290.));
#1672=CARTESIAN_POINT('',(-39.6666666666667,20.,290.));
#1673=CARTESIAN_POINT('',(-39.5833333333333,20.,290.));
#1674=CARTESIAN_POINT('',(-39.4166666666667,20.,290.));
#1675=CARTESIAN_POINT('',(-39.3333333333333,20.,290.));
#1676=CARTESIAN_POINT('',(-39.1666666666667,20.,290.));
#1677=CARTESIAN_POINT('',(-39.0833333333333,20.,290.));
#1678=CARTESIAN_POINT('',(-38.9166666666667,20.,290.));
#1679=CARTESIAN_POINT('',(-38.8333333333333,20.,290.));
#1680=CARTESIAN_POINT('',(-38.6666666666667,20.,290.));
#1681=CARTESIAN_POINT('',(-38.5833333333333,20.,290.));
#1682=CARTESIAN_POINT('',(-38.4166666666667,20.,290.));
#1683=CARTESIAN_POINT('',(-38.3333333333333,20.,290.));
#1684=CARTESIAN_POINT('',(-38.1666666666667,20.,290.));
#1685=CARTESIAN_POINT('',(-38.0833333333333,20.,290.));
#1686=CARTESIAN_POINT('',(-37.9166666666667,20.,290.));
#1687=CARTESIAN_POINT('',(-37.8333333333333,20.,290.));
#1688=CARTESIAN_POINT('',(-37.6666666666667,20.,290.));
#1689=CARTESIAN_POINT('',(-37.5833333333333,20.,290.));
#1690=CARTESIAN_POINT('',(-37.4166666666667,20.,290.));
#1691=CARTESIAN_POINT('',(-37.3333333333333,20.,290.));
#1692=CARTESIAN_POINT('',(-37.1666666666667,20.,290.));
#1693=CARTESIAN_POINT('',(-37.0833333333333,20.,290.));
#1694=CARTESIAN_POINT('',(-36.9166666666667,20.,290.));
#1695=CARTESIAN_POINT('',(-36.8333333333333,20.,290.));
#1696=CARTESIAN_POINT('',(-36.6666666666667,20.,290.));
#1697=CARTESIAN_POINT('',(-36.5833333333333,20.,290.));
#1698=CARTESIAN_POINT('',(-36.4166666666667,20.,290.));
#1699=CARTESIAN_POINT('',(-36.3333333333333,20.,290.));
#1700=CARTESIAN_POINT('',(-36.1666666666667,20.,290.));
#1701=CARTESIAN_POINT('',(-36.0833333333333,20.,290.));
#1702=CARTESIAN_POINT('',(-35.9166666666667,20.,290.));
#1703=CARTESIAN_POINT('',(-35.8333333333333,20.,290.));
#1704=CARTESIAN_POINT('',(-35.6666666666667,20.,290.));
#1705=CARTESIAN_POINT('',(-35.5833333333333,20.,290.));
#1706=CARTESIAN_POINT('',(-35.4166666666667,20.,290.));
#1707=CARTESIAN_POINT('',(-35.3333333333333,20.,290.));
#1708=CARTESIAN_POINT('',(-35.1666666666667,20.,290.));
#1709=CARTESIAN_POINT('',(-35.0833333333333,20.,290.));
#1710=CARTESIAN_POINT('',(-34.9166666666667,20.,290.));
#1711=CARTESIAN_POINT('',(-34.8333333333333,20.,290.));
#1712=CARTESIAN_POINT('',(-34.6666666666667,20.,290.));
#1713=CARTESIAN_POINT('',(-34.5833333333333,20.,290.));
#1714=CARTESIAN_POINT('',(-34.4166666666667,20.,290.));
#1715=CARTESIAN_POINT('',(-34.3333333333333,20.,290.));
#1716=CARTESIAN_POINT('',(-34.1666666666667,20.,290.));
#1717=CARTESIAN_POINT('',(-34.0833333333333,20.,290.));
#1718=CARTESIAN_POINT('',(-33.9166666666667,20.,290.));
#1719=CARTESIAN_POINT('',(-33.8333333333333,20.,290.));
#1720=CARTESIAN_POINT('',(-33.6666666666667,20.,290.));
#1721=CARTESIAN_POINT('',(-33.5833333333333,20.,290.));
#1722=CARTESIAN_POINT('',(-33.4166666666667,20.,290.));
#1723=CARTESIAN_POINT('',(-33.3333333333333,20.,290.));
#1724=CARTESIAN_POINT('',(-33.1666666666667,20.,290.));
#1725=CARTESIAN_POINT('',(-33.0833333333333,20.,290.));
#1726=CARTESIAN_POINT('',(-32.9166666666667,20.,290.));
#1727=CARTESIAN_POINT('',(-32.8333333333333,20.,290.));
#1728=CARTESIAN_POINT('',(-32.6666666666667,20.,290.));
#1729=CARTESIAN_POINT('',(-32.5833333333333,20.,290.));
#1730=CARTESIAN_POINT('',(-32.4166666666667,20.,290.));
#1731=CARTESIAN_POINT('',(-32.3333333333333,20.,290.));
#1732=CARTESIAN_POINT('',(-32.1666666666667,20.,290.));
#1733=CARTESIAN_POINT('',(-32.0833333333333,20.,290.));
#1734=CARTESIAN_POINT('',(-32.,20.,290.));
#1735=B_SPLINE_CURVE_WITH_KNOTS('',3,(#1669,#1670,#1671,#1672,#1673,#1674,#1675,#1676,#1677,
#1678,#1679,#1680,#1681,#1682,#1683,#1684,#1685,#1686,#1687,#1688,#1689,#1690,#1691,#1692,#1693,
#1694,#1695,#1696,#1697,#1698,#1699,#1700,#1701,#1702,#1703,#1704,#1705,#1706,#1707,#1708,#1709,
#1710,#1711,#1712,#1713,#1714,#1715,#1716,#1717,#1718,#1719,#1720,#1721,#1722,#1723,#1724,#1725,
#1726,#1727,#1728,#1729,#1730,#1731,#1732,#1733,#1734),.UNSPECIFIED.,.F.,.F.,(4,2,2,2,2,2,2,2,2,
2,2,2,2,2,2,2,2,2,2,2,2,2,2,2,2,2,2,2,2,2,2,2,4),(0.,0.25,0.5,0.750000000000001,1.,1.25,1.5,
1.75,2.,2.25,2.5,2.75,3.,3.25,3.5,3.75,4.,4.25,4.5,4.75,5.,5.25,5.50000000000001,
5.75000000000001,6.00000000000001,6.25000000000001,6.50000000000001,6.75000000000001,
7.00000000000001,7.25000000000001,7.50000000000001,7.75000000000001,8.00000000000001),.UNSPECIFIED.);
#1736=EDGE_CURVE('BSEAM299',#97,#1088,#1735,.T.);
#1737=ORIENTED_EDGE('',*,*,#98,.T.);
#1738=ORIENTED_EDGE('',*,*,#1089,.F.);
#1739=ORIENTED_EDGE('',*,*,#1736,.T.);
#1740=ORIENTED_EDGE('',*,*,#1736,.F.);
#1741=EDGE_LOOP('',(#1737,#1739,#1738,#1740));
#1742=FACE_BOUND('',#1741,.T.);
#1743=ADVANCED_FACE('F299',(#1742),#1668,.F.);
#1744=CARTESIAN_POINT('',(40.,45.,370.));
#1745=DIRECTION('',(-1.,0.,0.));
#1746=DIRECTION('',(0.,-1.,0.));
#1747=AXIS2_PLACEMENT_3D('',#1744,#1745,#1746);
#1748=CYLINDRICAL_SURFACE('',#1747,25.);
#1749=CARTESIAN_POINT('',(-40.,20.,370.));
#1750=CARTESIAN_POINT('',(-39.9166666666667,20.,370.));
#1751=CARTESIAN_POINT('',(-39.8333333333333,20.,370.));
#1752=CARTESIAN_POINT('',(-39.6666666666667,20.,370.));
#1753=CARTESIAN_POINT('',(-39.5833333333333,20.,370.));
#1754=CARTESIAN_POINT('',(-39.4166666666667,20.,370.));
#1755=CARTESIAN_POINT('',(-39.3333333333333,20.,370.));
#1756=CARTESIAN_POINT('',(-39.1666666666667,20.,370.));
#1757=CARTESIAN_POINT('',(-39.0833333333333,20.,370.));
#1758=CARTESIAN_POINT('',(-38.9166666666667,20.,370.));
#1759=CARTESIAN_POINT('',(-38.8333333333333,20.,370.));
#1760=CARTESIAN_POINT('',(-38.6666666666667,20.,370.));
#1761=CARTESIAN_POINT('',(-38.5833333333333,20.,370.));
#1762=CARTESIAN_POINT('',(-38.4166666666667,20.,370.));
#1763=CARTESIAN_POINT('',(-38.3333333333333,20.,370.));
#1764=CARTESIAN_POINT('',(-38.1666666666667,20.,370.));
#1765=CARTESIAN_POINT('',(-38.0833333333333,20.,370.));
#1766=CARTESIAN_POINT('',(-37.9166666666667,20.,370.));
#1767=CARTESIAN_POINT('',(-37.8333333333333,20.,370.));
#1768=CARTESIAN_POINT('',(-37.6666666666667,20.,370.));
#1769=CARTESIAN_POINT('',(-37.5833333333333,20.,370.));
#1770=CARTESIAN_POINT('',(-37.4166666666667,20.,370.));
#1771=CARTESIAN_POINT('',(-37.3333333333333,20.,370.));
#1772=CARTESIAN_POINT('',(-37.1666666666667,20.,370.));
#1773=CARTESIAN_POINT('',(-37.0833333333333,20.,370.));
#1774=CARTESIAN_POINT('',(-36.9166666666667,20.,370.));
#1775=CARTESIAN_POINT('',(-36.8333333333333,20.,370.));
#1776=CARTESIAN_POINT('',(-36.6666666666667,20.,370.));
#1777=CARTESIAN_POINT('',(-36.5833333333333,20.,370.));
#1778=CARTESIAN_POINT('',(-36.4166666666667,20.,370.));
#1779=CARTESIAN_POINT('',(-36.3333333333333,20.,370.));
#1780=CARTESIAN_POINT('',(-36.1666666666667,20.,370.));
#1781=CARTESIAN_POINT('',(-36.0833333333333,20.,370.));
#1782=CARTESIAN_POINT('',(-35.9166666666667,20.,370.));
#1783=CARTESIAN_POINT('',(-35.8333333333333,20.,370.));
#1784=CARTESIAN_POINT('',(-35.6666666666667,20.,370.));
#1785=CARTESIAN_POINT('',(-35.5833333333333,20.,370.));
#1786=CARTESIAN_POINT('',(-35.4166666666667,20.,370.));
#1787=CARTESIAN_POINT('',(-35.3333333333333,20.,370.));
#1788=CARTESIAN_POINT('',(-35.1666666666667,20.,370.));
#1789=CARTESIAN_POINT('',(-35.0833333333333,20.,370.));
#1790=CARTESIAN_POINT('',(-34.9166666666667,20.,370.));
#1791=CARTESIAN_POINT('',(-34.8333333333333,20.,370.));
#1792=CARTESIAN_POINT('',(-34.6666666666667,20.,370.));
#1793=CARTESIAN_POINT('',(-34.5833333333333,20.,370.));
#1794=CARTESIAN_POINT('',(-34.4166666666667,20.,370.));
#1795=CARTESIAN_POINT('',(-34.3333333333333,20.,370.));
#1796=CARTESIAN_POINT('',(-34.1666666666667,20.,370.));
#1797=CARTESIAN_POINT('',(-34.0833333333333,20.,370.));
#1798=CARTESIAN_POINT('',(-33.9166666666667,20.,370.));
#1799=CARTESIAN_POINT('',(-33.8333333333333,20.,370.));
#1800=CARTESIAN_POINT('',(-33.6666666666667,20.,370.));
#1801=CARTESIAN_POINT('',(-33.5833333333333,20.,370.));
#1802=CARTESIAN_POINT('',(-33.4166666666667,20.,370.));
#1803=CARTESIAN_POINT('',(-33.3333333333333,20.,370.));
#1804=CARTESIAN_POINT('',(-33.1666666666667,20.,370.));
#1805=CARTESIAN_POINT('',(-33.0833333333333,20.,370.));
#1806=CARTESIAN_POINT('',(-32.9166666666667,20.,370.));
#1807=CARTESIAN_POINT('',(-32.8333333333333,20.,370.));
#1808=CARTESIAN_POINT('',(-32.6666666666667,20.,370.));
#1809=CARTESIAN_POINT('',(-32.5833333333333,20.,370.));
#1810=CARTESIAN_POINT('',(-32.4166666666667,20.,370.));
#1811=CARTESIAN_POINT('',(-32.3333333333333,20.,370.));
#1812=CARTESIAN_POINT('',(-32.1666666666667,20.,370.));
#1813=CARTESIAN_POINT('',(-32.0833333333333,20.,370.));
#1814=CARTESIAN_POINT('',(-32.,20.,370.));
#1815=B_SPLINE_CURVE_WITH_KNOTS('',3,(#1749,#1750,#1751,#1752,#1753,#1754,#1755,#1756,#1757,
#1758,#1759,#1760,#1761,#1762,#1763,#1764,#1765,#1766,#1767,#1768,#1769,#1770,#1771,#1772,#1773,
#1774,#1775,#1776,#1777,#1778,#1779,#1780,#1781,#1782,#1783,#1784,#1785,#1786,#1787,#1788,#1789,
#1790,#1791,#1792,#1793,#1794,#1795,#1796,#1797,#1798,#1799,#1800,#1801,#1802,#1803,#1804,#1805,
#1806,#1807,#1808,#1809,#1810,#1811,#1812,#1813,#1814),.UNSPECIFIED.,.F.,.F.,(4,2,2,2,2,2,2,2,2,
2,2,2,2,2,2,2,2,2,2,2,2,2,2,2,2,2,2,2,2,2,2,2,4),(0.,0.25,0.5,0.750000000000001,1.,1.25,1.5,
1.75,2.,2.25,2.5,2.75,3.,3.25,3.5,3.75,4.,4.25,4.5,4.75,5.,5.25,5.50000000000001,
5.75000000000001,6.00000000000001,6.25000000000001,6.50000000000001,6.75000000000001,
7.00000000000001,7.25000000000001,7.50000000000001,7.75000000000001,8.00000000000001),.UNSPECIFIED.);
#1816=EDGE_CURVE('BSEAM304',#108,#1099,#1815,.T.);
#1817=ORIENTED_EDGE('',*,*,#109,.T.);
#1818=ORIENTED_EDGE('',*,*,#1100,.F.);
#1819=ORIENTED_EDGE('',*,*,#1816,.T.);
#1820=ORIENTED_EDGE('',*,*,#1816,.F.);
#1821=EDGE_LOOP('',(#1817,#1819,#1818,#1820));
#1822=FACE_BOUND('',#1821,.T.);
#1823=ADVANCED_FACE('F304',(#1822),#1748,.F.);
#1824=CARTESIAN_POINT('',(40.,45.,450.));
#1825=DIRECTION('',(-1.,0.,0.));
#1826=DIRECTION('',(0.,-1.,0.));
#1827=AXIS2_PLACEMENT_3D('',#1824,#1825,#1826);
#1828=CYLINDRICAL_SURFACE('',#1827,25.);
#1829=CARTESIAN_POINT('',(-40.,20.,450.));
#1830=CARTESIAN_POINT('',(-39.9166666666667,20.,450.));
#1831=CARTESIAN_POINT('',(-39.8333333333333,20.,450.));
#1832=CARTESIAN_POINT('',(-39.6666666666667,20.,450.));
#1833=CARTESIAN_POINT('',(-39.5833333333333,20.,450.));
#1834=CARTESIAN_POINT('',(-39.4166666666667,20.,450.));
#1835=CARTESIAN_POINT('',(-39.3333333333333,20.,450.));
#1836=CARTESIAN_POINT('',(-39.1666666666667,20.,450.));
#1837=CARTESIAN_POINT('',(-39.0833333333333,20.,450.));
#1838=CARTESIAN_POINT('',(-38.9166666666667,20.,450.));
#1839=CARTESIAN_POINT('',(-38.8333333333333,20.,450.));
#1840=CARTESIAN_POINT('',(-38.6666666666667,20.,450.));
#1841=CARTESIAN_POINT('',(-38.5833333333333,20.,450.));
#1842=CARTESIAN_POINT('',(-38.4166666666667,20.,450.));
#1843=CARTESIAN_POINT('',(-38.3333333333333,20.,450.));
#1844=CARTESIAN_POINT('',(-38.1666666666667,20.,450.));
#1845=CARTESIAN_POINT('',(-38.0833333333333,20.,450.));
#1846=CARTESIAN_POINT('',(-37.9166666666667,20.,450.));
#1847=CARTESIAN_POINT('',(-37.8333333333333,20.,450.));
#1848=CARTESIAN_POINT('',(-37.6666666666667,20.,450.));
#1849=CARTESIAN_POINT('',(-37.5833333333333,20.,450.));
#1850=CARTESIAN_POINT('',(-37.4166666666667,20.,450.));
#1851=CARTESIAN_POINT('',(-37.3333333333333,20.,450.));
#1852=CARTESIAN_POINT('',(-37.1666666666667,20.,450.));
#1853=CARTESIAN_POINT('',(-37.0833333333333,20.,450.));
#1854=CARTESIAN_POINT('',(-36.9166666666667,20.,450.));
#1855=CARTESIAN_POINT('',(-36.8333333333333,20.,450.));
#1856=CARTESIAN_POINT('',(-36.6666666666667,20.,450.));
#1857=CARTESIAN_POINT('',(-36.5833333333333,20.,450.));
#1858=CARTESIAN_POINT('',(-36.4166666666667,20.,450.));
#1859=CARTESIAN_POINT('',(-36.3333333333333,20.,450.));
#1860=CARTESIAN_POINT('',(-36.1666666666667,20.,450.));
#1861=CARTESIAN_POINT('',(-36.0833333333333,20.,450.));
#1862=CARTESIAN_POINT('',(-35.9166666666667,20.,450.));
#1863=CARTESIAN_POINT('',(-35.8333333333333,20.,450.));
#1864=CARTESIAN_POINT('',(-35.6666666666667,20.,450.));
#1865=CARTESIAN_POINT('',(-35.5833333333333,20.,450.));
#1866=CARTESIAN_POINT('',(-35.4166666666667,20.,450.));
#1867=CARTESIAN_POINT('',(-35.3333333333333,20.,450.));
#1868=CARTESIAN_POINT('',(-35.1666666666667,20.,450.));
#1869=CARTESIAN_POINT('',(-35.0833333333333,20.,450.));
#1870=CARTESIAN_POINT('',(-34.9166666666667,20.,450.));
#1871=CARTESIAN_POINT('',(-34.8333333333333,20.,450.));
#1872=CARTESIAN_POINT('',(-34.6666666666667,20.,450.));
#1873=CARTESIAN_POINT('',(-34.5833333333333,20.,450.));
#1874=CARTESIAN_POINT('',(-34.4166666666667,20.,450.));
#1875=CARTESIAN_POINT('',(-34.3333333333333,20.,450.));
#1876=CARTESIAN_POINT('',(-34.1666666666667,20.,450.));
#1877=CARTESIAN_POINT('',(-34.0833333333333,20.,450.));
#1878=CARTESIAN_POINT('',(-33.9166666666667,20.,450.));
#1879=CARTESIAN_POINT('',(-33.8333333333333,20.,450.));
#1880=CARTESIAN_POINT('',(-33.6666666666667,20.,450.));
#1881=CARTESIAN_POINT('',(-33.5833333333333,20.,450.));
#1882=CARTESIAN_POINT('',(-33.4166666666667,20.,450.));
#1883=CARTESIAN_POINT('',(-33.3333333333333,20.,450.));
#1884=CARTESIAN_POINT('',(-33.1666666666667,20.,450.));
#1885=CARTESIAN_POINT('',(-33.0833333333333,20.,450.));
#1886=CARTESIAN_POINT('',(-32.9166666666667,20.,450.));
#1887=CARTESIAN_POINT('',(-32.8333333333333,20.,450.));
#1888=CARTESIAN_POINT('',(-32.6666666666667,20.,450.));
#1889=CARTESIAN_POINT('',(-32.5833333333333,20.,450.));
#1890=CARTESIAN_POINT('',(-32.4166666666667,20.,450.));
#1891=CARTESIAN_POINT('',(-32.3333333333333,20.,450.));
#1892=CARTESIAN_POINT('',(-32.1666666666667,20.,450.));
#1893=CARTESIAN_POINT('',(-32.0833333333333,20.,450.));
#1894=CARTESIAN_POINT('',(-32.,20.,450.));
#1895=B_SPLINE_CURVE_WITH_KNOTS('',3,(#1829,#1830,#1831,#1832,#1833,#1834,#1835,#1836,#1837,
#1838,#1839,#1840,#1841,#1842,#1843,#1844,#1845,#1846,#1847,#1848,#1849,#1850,#1851,#1852,#1853,
#1854,#1855,#1856,#1857,#1858,#1859,#1860,#1861,#1862,#1863,#1864,#1865,#1866,#1867,#1868,#1869,
#1870,#1871,#1872,#1873,#1874,#1875,#1876,#1877,#1878,#1879,#1880,#1881,#1882,#1883,#1884,#1885,
#1886,#1887,#1888,#1889,#1890,#1891,#1892,#1893,#1894),.UNSPECIFIED.,.F.,.F.,(4,2,2,2,2,2,2,2,2,
2,2,2,2,2,2,2,2,2,2,2,2,2,2,2,2,2,2,2,2,2,2,2,4),(0.,0.25,0.5,0.750000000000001,1.,1.25,1.5,
1.75,2.,2.25,2.5,2.75,3.,3.25,3.5,3.75,4.,4.25,4.5,4.75,5.,5.25,5.50000000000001,
5.75000000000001,6.00000000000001,6.25000000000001,6.50000000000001,6.75000000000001,
7.00000000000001,7.25000000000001,7.50000000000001,7.75000000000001,8.00000000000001),.UNSPECIFIED.);
#1896=EDGE_CURVE('BSEAM308',#119,#1110,#1895,.T.);
#1897=ORIENTED_EDGE('',*,*,#120,.T.);
#1898=ORIENTED_EDGE('',*,*,#1111,.F.);
#1899=ORIENTED_EDGE('',*,*,#1896,.T.);
#1900=ORIENTED_EDGE('',*,*,#1896,.F.);
#1901=EDGE_LOOP('',(#1897,#1899,#1898,#1900));
#1902=FACE_BOUND('',#1901,.T.);
#1903=ADVANCED_FACE('F308',(#1902),#1828,.F.);
#1904=CARTESIAN_POINT('',(40.,45.,530.));
#1905=DIRECTION('',(-1.,0.,0.));
#1906=DIRECTION('',(0.,-1.,0.));
#1907=AXIS2_PLACEMENT_3D('',#1904,#1905,#1906);
#1908=CYLINDRICAL_SURFACE('',#1907,25.);
#1909=CARTESIAN_POINT('',(-40.,20.,530.));
#1910=CARTESIAN_POINT('',(-39.9166666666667,20.,530.));
#1911=CARTESIAN_POINT('',(-39.8333333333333,20.,530.));
#1912=CARTESIAN_POINT('',(-39.6666666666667,20.,530.));
#1913=CARTESIAN_POINT('',(-39.5833333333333,20.,530.));
#1914=CARTESIAN_POINT('',(-39.4166666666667,20.,530.));
#1915=CARTESIAN_POINT('',(-39.3333333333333,20.,530.));
#1916=CARTESIAN_POINT('',(-39.1666666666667,20.,530.));
#1917=CARTESIAN_POINT('',(-39.0833333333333,20.,530.));
#1918=CARTESIAN_POINT('',(-38.9166666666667,20.,530.));
#1919=CARTESIAN_POINT('',(-38.8333333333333,20.,530.));
#1920=CARTESIAN_POINT('',(-38.6666666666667,20.,530.));
#1921=CARTESIAN_POINT('',(-38.5833333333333,20.,530.));
#1922=CARTESIAN_POINT('',(-38.4166666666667,20.,530.));
#1923=CARTESIAN_POINT('',(-38.3333333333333,20.,530.));
#1924=CARTESIAN_POINT('',(-38.1666666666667,20.,530.));
#1925=CARTESIAN_POINT('',(-38.0833333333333,20.,530.));
#1926=CARTESIAN_POINT('',(-37.9166666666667,20.,530.));
#1927=CARTESIAN_POINT('',(-37.8333333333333,20.,530.));
#1928=CARTESIAN_POINT('',(-37.6666666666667,20.,530.));
#1929=CARTESIAN_POINT('',(-37.5833333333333,20.,530.));
#1930=CARTESIAN_POINT('',(-37.4166666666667,20.,530.));
#1931=CARTESIAN_POINT('',(-37.3333333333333,20.,530.));
#1932=CARTESIAN_POINT('',(-37.1666666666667,20.,530.));
#1933=CARTESIAN_POINT('',(-37.0833333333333,20.,530.));
#1934=CARTESIAN_POINT('',(-36.9166666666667,20.,530.));
#1935=CARTESIAN_POINT('',(-36.8333333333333,20.,530.));
#1936=CARTESIAN_POINT('',(-36.6666666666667,20.,530.));
#1937=CARTESIAN_POINT('',(-36.5833333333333,20.,530.));
#1938=CARTESIAN_POINT('',(-36.4166666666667,20.,530.));
#1939=CARTESIAN_POINT('',(-36.3333333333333,20.,530.));
#1940=CARTESIAN_POINT('',(-36.1666666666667,20.,530.));
#1941=CARTESIAN_POINT('',(-36.0833333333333,20.,530.));
#1942=CARTESIAN_POINT('',(-35.9166666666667,20.,530.));
#1943=CARTESIAN_POINT('',(-35.8333333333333,20.,530.));
#1944=CARTESIAN_POINT('',(-35.6666666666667,20.,530.));
#1945=CARTESIAN_POINT('',(-35.5833333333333,20.,530.));
#1946=CARTESIAN_POINT('',(-35.4166666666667,20.,530.));
#1947=CARTESIAN_POINT('',(-35.3333333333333,20.,530.));
#1948=CARTESIAN_POINT('',(-35.1666666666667,20.,530.));
#1949=CARTESIAN_POINT('',(-35.0833333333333,20.,530.));
#1950=CARTESIAN_POINT('',(-34.9166666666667,20.,530.));
#1951=CARTESIAN_POINT('',(-34.8333333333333,20.,530.));
#1952=CARTESIAN_POINT('',(-34.6666666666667,20.,530.));
#1953=CARTESIAN_POINT('',(-34.5833333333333,20.,530.));
#1954=CARTESIAN_POINT('',(-34.4166666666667,20.,530.));
#1955=CARTESIAN_POINT('',(-34.3333333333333,20.,530.));
#1956=CARTESIAN_POINT('',(-34.1666666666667,20.,530.));
#1957=CARTESIAN_POINT('',(-34.0833333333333,20.,530.));
#1958=CARTESIAN_POINT('',(-33.9166666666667,20.,530.));
#1959=CARTESIAN_POINT('',(-33.8333333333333,20.,530.));
#1960=CARTESIAN_POINT('',(-33.6666666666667,20.,530.));
#1961=CARTESIAN_POINT('',(-33.5833333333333,20.,530.));
#1962=CARTESIAN_POINT('',(-33.4166666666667,20.,530.));
#1963=CARTESIAN_POINT('',(-33.3333333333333,20.,530.));
#1964=CARTESIAN_POINT('',(-33.1666666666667,20.,530.));
#1965=CARTESIAN_POINT('',(-33.0833333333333,20.,530.));
#1966=CARTESIAN_POINT('',(-32.9166666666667,20.,530.));
#1967=CARTESIAN_POINT('',(-32.8333333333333,20.,530.));
#1968=CARTESIAN_POINT('',(-32.6666666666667,20.,530.));
#1969=CARTESIAN_POINT('',(-32.5833333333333,20.,530.));
#1970=CARTESIAN_POINT('',(-32.4166666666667,20.,530.));
#1971=CARTESIAN_POINT('',(-32.3333333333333,20.,530.));
#1972=CARTESIAN_POINT('',(-32.1666666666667,20.,530.));
#1973=CARTESIAN_POINT('',(-32.0833333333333,20.,530.));
#1974=CARTESIAN_POINT('',(-32.,20.,530.));
#1975=B_SPLINE_CURVE_WITH_KNOTS('',3,(#1909,#1910,#1911,#1912,#1913,#1914,#1915,#1916,#1917,
#1918,#1919,#1920,#1921,#1922,#1923,#1924,#1925,#1926,#1927,#1928,#1929,#1930,#1931,#1932,#1933,
#1934,#1935,#1936,#1937,#1938,#1939,#1940,#1941,#1942,#1943,#1944,#1945,#1946,#1947,#1948,#1949,
#1950,#1951,#1952,#1953,#1954,#1955,#1956,#1957,#1958,#1959,#1960,#1961,#1962,#1963,#1964,#1965,
#1966,#1967,#1968,#1969,#1970,#1971,#1972,#1973,#1974),.UNSPECIFIED.,.F.,.F.,(4,2,2,2,2,2,2,2,2,
2,2,2,2,2,2,2,2,2,2,2,2,2,2,2,2,2,2,2,2,2,2,2,4),(0.,0.25,0.5,0.750000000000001,1.,1.25,1.5,
1.75,2.,2.25,2.5,2.75,3.,3.25,3.5,3.75,4.,4.25,4.5,4.75,5.,5.25,5.50000000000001,
5.75000000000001,6.00000000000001,6.25000000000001,6.50000000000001,6.75000000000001,
7.00000000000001,7.25000000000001,7.50000000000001,7.75000000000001,8.00000000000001),.UNSPECIFIED.);
#1976=EDGE_CURVE('BSEAM312',#130,#1121,#1975,.T.);
#1977=ORIENTED_EDGE('',*,*,#131,.T.);
#1978=ORIENTED_EDGE('',*,*,#1122,.F.);
#1979=ORIENTED_EDGE('',*,*,#1976,.T.);
#1980=ORIENTED_EDGE('',*,*,#1976,.F.);
#1981=EDGE_LOOP('',(#1977,#1979,#1978,#1980));
#1982=FACE_BOUND('',#1981,.T.);
#1983=ADVANCED_FACE('F312',(#1982),#1908,.F.);
#1984=CARTESIAN_POINT('',(40.,45.,610.));
#1985=DIRECTION('',(-1.,0.,0.));
#1986=DIRECTION('',(0.,-1.,0.));
#1987=AXIS2_PLACEMENT_3D('',#1984,#1985,#1986);
#1988=CYLINDRICAL_SURFACE('',#1987,25.);
#1989=CARTESIAN_POINT('',(-40.,20.,610.));
#1990=CARTESIAN_POINT('',(-39.9166666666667,20.,610.));
#1991=CARTESIAN_POINT('',(-39.8333333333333,20.,610.));
#1992=CARTESIAN_POINT('',(-39.6666666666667,20.,610.));
#1993=CARTESIAN_POINT('',(-39.5833333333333,20.,610.));
#1994=CARTESIAN_POINT('',(-39.4166666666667,20.,610.));
#1995=CARTESIAN_POINT('',(-39.3333333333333,20.,610.));
#1996=CARTESIAN_POINT('',(-39.1666666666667,20.,610.));
#1997=CARTESIAN_POINT('',(-39.0833333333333,20.,610.));
#1998=CARTESIAN_POINT('',(-38.9166666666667,20.,610.));
#1999=CARTESIAN_POINT('',(-38.8333333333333,20.,610.));
#2000=CARTESIAN_POINT('',(-38.6666666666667,20.,610.));
#2001=CARTESIAN_POINT('',(-38.5833333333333,20.,610.));
#2002=CARTESIAN_POINT('',(-38.4166666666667,20.,610.));
#2003=CARTESIAN_POINT('',(-38.3333333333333,20.,610.));
#2004=CARTESIAN_POINT('',(-38.1666666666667,20.,610.));
#2005=CARTESIAN_POINT('',(-38.0833333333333,20.,610.));
#2006=CARTESIAN_POINT('',(-37.9166666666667,20.,610.));
#2007=CARTESIAN_POINT('',(-37.8333333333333,20.,610.));
#2008=CARTESIAN_POINT('',(-37.6666666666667,20.,610.));
#2009=CARTESIAN_POINT('',(-37.5833333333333,20.,610.));
#2010=CARTESIAN_POINT('',(-37.4166666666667,20.,610.));
#2011=CARTESIAN_POINT('',(-37.3333333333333,20.,610.));
#2012=CARTESIAN_POINT('',(-37.1666666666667,20.,610.));
#2013=CARTESIAN_POINT('',(-37.0833333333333,20.,610.));
#2014=CARTESIAN_POINT('',(-36.9166666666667,20.,610.));
#2015=CARTESIAN_POINT('',(-36.8333333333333,20.,610.));
#2016=CARTESIAN_POINT('',(-36.6666666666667,20.,610.));
#2017=CARTESIAN_POINT('',(-36.5833333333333,20.,610.));
#2018=CARTESIAN_POINT('',(-36.4166666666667,20.,610.));
#2019=CARTESIAN_POINT('',(-36.3333333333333,20.,610.));
#2020=CARTESIAN_POINT('',(-36.1666666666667,20.,610.));
#2021=CARTESIAN_POINT('',(-36.0833333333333,20.,610.));
#2022=CARTESIAN_POINT('',(-35.9166666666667,20.,610.));
#2023=CARTESIAN_POINT('',(-35.8333333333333,20.,610.));
#2024=CARTESIAN_POINT('',(-35.6666666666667,20.,610.));
#2025=CARTESIAN_POINT('',(-35.5833333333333,20.,610.));
#2026=CARTESIAN_POINT('',(-35.4166666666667,20.,610.));
#2027=CARTESIAN_POINT('',(-35.3333333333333,20.,610.));
#2028=CARTESIAN_POINT('',(-35.1666666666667,20.,610.));
#2029=CARTESIAN_POINT('',(-35.0833333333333,20.,610.));
#2030=CARTESIAN_POINT('',(-34.9166666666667,20.,610.));
#2031=CARTESIAN_POINT('',(-34.8333333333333,20.,610.));
#2032=CARTESIAN_POINT('',(-34.6666666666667,20.,610.));
#2033=CARTESIAN_POINT('',(-34.5833333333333,20.,610.));
#2034=CARTESIAN_POINT('',(-34.4166666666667,20.,610.));
#2035=CARTESIAN_POINT('',(-34.3333333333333,20.,610.));
#2036=CARTESIAN_POINT('',(-34.1666666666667,20.,610.));
#2037=CARTESIAN_POINT('',(-34.0833333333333,20.,610.));
#2038=CARTESIAN_POINT('',(-33.9166666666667,20.,610.));
#2039=CARTESIAN_POINT('',(-33.8333333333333,20.,610.));
#2040=CARTESIAN_POINT('',(-33.6666666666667,20.,610.));
#2041=CARTESIAN_POINT('',(-33.5833333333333,20.,610.));
#2042=CARTESIAN_POINT('',(-33.4166666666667,20.,610.));
#2043=CARTESIAN_POINT('',(-33.3333333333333,20.,610.));
#2044=CARTESIAN_POINT('',(-33.1666666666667,20.,610.));
#2045=CARTESIAN_POINT('',(-33.0833333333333,20.,610.));
#2046=CARTESIAN_POINT('',(-32.9166666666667,20.,610.));
#2047=CARTESIAN_POINT('',(-32.8333333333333,20.,610.));
#2048=CARTESIAN_POINT('',(-32.6666666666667,20.,610.));
#2049=CARTESIAN_POINT('',(-32.5833333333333,20.,610.));
#2050=CARTESIAN_POINT('',(-32.4166666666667,20.,610.));
#2051=CARTESIAN_POINT('',(-32.3333333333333,20.,610.));
#2052=CARTESIAN_POINT('',(-32.1666666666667,20.,610.));
#2053=CARTESIAN_POINT('',(-32.0833333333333,20.,610.));
#2054=CARTESIAN_POINT('',(-32.,20.,610.));
#2055=B_SPLINE_CURVE_WITH_KNOTS('',3,(#1989,#1990,#1991,#1992,#1993,#1994,#1995,#1996,#1997,
#1998,#1999,#2000,#2001,#2002,#2003,#2004,#2005,#2006,#2007,#2008,#2009,#2010,#2011,#2012,#2013,
#2014,#2015,#2016,#2017,#2018,#2019,#2020,#2021,#2022,#2023,#2024,#2025,#2026,#2027,#2028,#2029,
#2030,#2031,#2032,#2033,#2034,#2035,#2036,#2037,#2038,#2039,#2040,#2041,#2042,#2043,#2044,#2045,
#2046,#2047,#2048,#2049,#2050,#2051,#2052,#2053,#2054),.UNSPECIFIED.,.F.,.F.,(4,2,2,2,2,2,2,2,2,
2,2,2,2,2,2,2,2,2,2,2,2,2,2,2,2,2,2,2,2,2,2,2,4),(0.,0.25,0.5,0.750000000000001,1.,1.25,1.5,
1.75,2.,2.25,2.5,2.75,3.,3.25,3.5,3.75,4.,4.25,4.5,4.75,5.,5.25,5.50000000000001,
5.75000000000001,6.00000000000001,6.25000000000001,6.50000000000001,6.75000000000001,
7.00000000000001,7.25000000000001,7.50000000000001,7.75000000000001,8.00000000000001),.UNSPECIFIED.);
#2056=EDGE_CURVE('BSEAM316',#141,#1132,#2055,.T.);
#2057=ORIENTED_EDGE('',*,*,#142,.T.);
#2058=ORIENTED_EDGE('',*,*,#1133,.F.);
#2059=ORIENTED_EDGE('',*,*,#2056,.T.);
#2060=ORIENTED_EDGE('',*,*,#2056,.F.);
#2061=EDGE_LOOP('',(#2057,#2059,#2058,#2060));
#2062=FACE_BOUND('',#2061,.T.);
#2063=ADVANCED_FACE('F316',(#2062),#1988,.F.);
#2064=CARTESIAN_POINT('',(40.,45.,690.));
#2065=DIRECTION('',(-1.,0.,0.));
#2066=DIRECTION('',(0.,-1.,0.));
#2067=AXIS2_PLACEMENT_3D('',#2064,#2065,#2066);
#2068=CYLINDRICAL_SURFACE('',#2067,25.);
#2069=CARTESIAN_POINT('',(-40.,20.,690.));
#2070=CARTESIAN_POINT('',(-39.9166666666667,20.,690.));
#2071=CARTESIAN_POINT('',(-39.8333333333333,20.,690.));
#2072=CARTESIAN_POINT('',(-39.6666666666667,20.,690.));
#2073=CARTESIAN_POINT('',(-39.5833333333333,20.,690.));
#2074=CARTESIAN_POINT('',(-39.4166666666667,20.,690.));
#2075=CARTESIAN_POINT('',(-39.3333333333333,20.,690.));
#2076=CARTESIAN_POINT('',(-39.1666666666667,20.,690.));
#2077=CARTESIAN_POINT('',(-39.0833333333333,20.,690.));
#2078=CARTESIAN_POINT('',(-38.9166666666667,20.,690.));
#2079=CARTESIAN_POINT('',(-38.8333333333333,20.,690.));
#2080=CARTESIAN_POINT('',(-38.6666666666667,20.,690.));
#2081=CARTESIAN_POINT('',(-38.5833333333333,20.,690.));
#2082=CARTESIAN_POINT('',(-38.4166666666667,20.,690.));
#2083=CARTESIAN_POINT('',(-38.3333333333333,20.,690.));
#2084=CARTESIAN_POINT('',(-38.1666666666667,20.,690.));
#2085=CARTESIAN_POINT('',(-38.0833333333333,20.,690.));
#2086=CARTESIAN_POINT('',(-37.9166666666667,20.,690.));
#2087=CARTESIAN_POINT('',(-37.8333333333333,20.,690.));
#2088=CARTESIAN_POINT('',(-37.6666666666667,20.,690.));
#2089=CARTESIAN_POINT('',(-37.5833333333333,20.,690.));
#2090=CARTESIAN_POINT('',(-37.4166666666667,20.,690.));
#2091=CARTESIAN_POINT('',(-37.3333333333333,20.,690.));
#2092=CARTESIAN_POINT('',(-37.1666666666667,20.,690.));
#2093=CARTESIAN_POINT('',(-37.0833333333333,20.,690.));
#2094=CARTESIAN_POINT('',(-36.9166666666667,20.,690.));
#2095=CARTESIAN_POINT('',(-36.8333333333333,20.,690.));
#2096=CARTESIAN_POINT('',(-36.6666666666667,20.,690.));
#2097=CARTESIAN_POINT('',(-36.5833333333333,20.,690.));
#2098=CARTESIAN_POINT('',(-36.4166666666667,20.,690.));
#2099=CARTESIAN_POINT('',(-36.3333333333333,20.,690.));
#2100=CARTESIAN_POINT('',(-36.1666666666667,20.,690.));
#2101=CARTESIAN_POINT('',(-36.0833333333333,20.,690.));
#2102=CARTESIAN_POINT('',(-35.9166666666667,20.,690.));
#2103=CARTESIAN_POINT('',(-35.8333333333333,20.,690.));
#2104=CARTESIAN_POINT('',(-35.6666666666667,20.,690.));
#2105=CARTESIAN_POINT('',(-35.5833333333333,20.,690.));
#2106=CARTESIAN_POINT('',(-35.4166666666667,20.,690.));
#2107=CARTESIAN_POINT('',(-35.3333333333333,20.,690.));
#2108=CARTESIAN_POINT('',(-35.1666666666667,20.,690.));
#2109=CARTESIAN_POINT('',(-35.0833333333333,20.,690.));
#2110=CARTESIAN_POINT('',(-34.9166666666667,20.,690.));
#2111=CARTESIAN_POINT('',(-34.8333333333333,20.,690.));
#2112=CARTESIAN_POINT('',(-34.6666666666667,20.,690.));
#2113=CARTESIAN_POINT('',(-34.5833333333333,20.,690.));
#2114=CARTESIAN_POINT('',(-34.4166666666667,20.,690.));
#2115=CARTESIAN_POINT('',(-34.3333333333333,20.,690.));
#2116=CARTESIAN_POINT('',(-34.1666666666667,20.,690.));
#2117=CARTESIAN_POINT('',(-34.0833333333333,20.,690.));
#2118=CARTESIAN_POINT('',(-33.9166666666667,20.,690.));
#2119=CARTESIAN_POINT('',(-33.8333333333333,20.,690.));
#2120=CARTESIAN_POINT('',(-33.6666666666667,20.,690.));
#2121=CARTESIAN_POINT('',(-33.5833333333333,20.,690.));
#2122=CARTESIAN_POINT('',(-33.4166666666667,20.,690.));
#2123=CARTESIAN_POINT('',(-33.3333333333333,20.,690.));
#2124=CARTESIAN_POINT('',(-33.1666666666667,20.,690.));
#2125=CARTESIAN_POINT('',(-33.0833333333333,20.,690.));
#2126=CARTESIAN_POINT('',(-32.9166666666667,20.,690.));
#2127=CARTESIAN_POINT('',(-32.8333333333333,20.,690.));
#2128=CARTESIAN_POINT('',(-32.6666666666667,20.,690.));
#2129=CARTESIAN_POINT('',(-32.5833333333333,20.,690.));
#2130=CARTESIAN_POINT('',(-32.4166666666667,20.,690.));
#2131=CARTESIAN_POINT('',(-32.3333333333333,20.,690.));
#2132=CARTESIAN_POINT('',(-32.1666666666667,20.,690.));
#2133=CARTESIAN_POINT('',(-32.0833333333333,20.,690.));
#2134=CARTESIAN_POINT('',(-32.,20.,690.));
#2135=B_SPLINE_CURVE_WITH_KNOTS('',3,(#2069,#2070,#2071,#2072,#2073,#2074,#2075,#2076,#2077,
#2078,#2079,#2080,#2081,#2082,#2083,#2084,#2085,#2086,#2087,#2088,#2089,#2090,#2091,#2092,#2093,
#2094,#2095,#2096,#2097,#2098,#2099,#2100,#2101,#2102,#2103,#2104,#2105,#2106,#2107,#2108,#2109,
#2110,#2111,#2112,#2113,#2114,#2115,#2116,#2117,#2118,#2119,#2120,#2121,#2122,#2123,#2124,#2125,
#2126,#2127,#2128,#2129,#2130,#2131,#2132,#2133,#2134),.UNSPECIFIED.,.F.,.F.,(4,2,2,2,2,2,2,2,2,
2,2,2,2,2,2,2,2,2,2,2,2,2,2,2,2,2,2,2,2,2,2,2,4),(0.,0.25,0.5,0.750000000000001,1.,1.25,1.5,
1.75,2.,2.25,2.5,2.75,3.,3.25,3.5,3.75,4.,4.25,4.5,4.75,5.,5.25,5.50000000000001,
5.75000000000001,6.00000000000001,6.25000000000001,6.50000000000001,6.75000000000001,
7.00000000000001,7.25000000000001,7.50000000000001,7.75000000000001,8.00000000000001),.UNSPECIFIED.);
#2136=EDGE_CURVE('BSEAM320',#152,#1143,#2135,.T.);
#2137=ORIENTED_EDGE('',*,*,#153,.T.);
#2138=ORIENTED_EDGE('',*,*,#1144,.F.);
#2139=ORIENTED_EDGE('',*,*,#2136,.T.);
#2140=ORIENTED_EDGE('',*,*,#2136,.F.);
#2141=EDGE_LOOP('',(#2137,#2139,#2138,#2140));
#2142=FACE_BOUND('',#2141,.T.);
#2143=ADVANCED_FACE('F320',(#2142),#2068,.F.);
#2144=CARTESIAN_POINT('',(40.,45.,770.));
#2145=DIRECTION('',(-1.,0.,0.));
#2146=DIRECTION('',(0.,-1.,0.));
#2147=AXIS2_PLACEMENT_3D('',#2144,#2145,#2146);
#2148=CYLINDRICAL_SURFACE('',#2147,25.);
#2149=CARTESIAN_POINT('',(-40.,20.,770.));
#2150=CARTESIAN_POINT('',(-39.9166666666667,20.,770.));
#2151=CARTESIAN_POINT('',(-39.8333333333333,20.,770.));
#2152=CARTESIAN_POINT('',(-39.6666666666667,20.,770.));
#2153=CARTESIAN_POINT('',(-39.5833333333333,20.,770.));
#2154=CARTESIAN_POINT('',(-39.4166666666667,20.,770.));
#2155=CARTESIAN_POINT('',(-39.3333333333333,20.,770.));
#2156=CARTESIAN_POINT('',(-39.1666666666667,20.,770.));
#2157=CARTESIAN_POINT('',(-39.0833333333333,20.,770.));
#2158=CARTESIAN_POINT('',(-38.9166666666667,20.,770.));
#2159=CARTESIAN_POINT('',(-38.8333333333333,20.,770.));
#2160=CARTESIAN_POINT('',(-38.6666666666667,20.,770.));
#2161=CARTESIAN_POINT('',(-38.5833333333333,20.,770.));
#2162=CARTESIAN_POINT('',(-38.4166666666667,20.,770.));
#2163=CARTESIAN_POINT('',(-38.3333333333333,20.,770.));
#2164=CARTESIAN_POINT('',(-38.1666666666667,20.,770.));
#2165=CARTESIAN_POINT('',(-38.0833333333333,20.,770.));
#2166=CARTESIAN_POINT('',(-37.9166666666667,20.,770.));
#2167=CARTESIAN_POINT('',(-37.8333333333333,20.,770.));
#2168=CARTESIAN_POINT('',(-37.6666666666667,20.,770.));
#2169=CARTESIAN_POINT('',(-37.5833333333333,20.,770.));
#2170=CARTESIAN_POINT('',(-37.4166666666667,20.,770.));
#2171=CARTESIAN_POINT('',(-37.3333333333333,20.,770.));
#2172=CARTESIAN_POINT('',(-37.1666666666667,20.,770.));
#2173=CARTESIAN_POINT('',(-37.0833333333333,20.,770.));
#2174=CARTESIAN_POINT('',(-36.9166666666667,20.,770.));
#2175=CARTESIAN_POINT('',(-36.8333333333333,20.,770.));
#2176=CARTESIAN_POINT('',(-36.6666666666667,20.,770.));
#2177=CARTESIAN_POINT('',(-36.5833333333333,20.,770.));
#2178=CARTESIAN_POINT('',(-36.4166666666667,20.,770.));
#2179=CARTESIAN_POINT('',(-36.3333333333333,20.,770.));
#2180=CARTESIAN_POINT('',(-36.1666666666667,20.,770.));
#2181=CARTESIAN_POINT('',(-36.0833333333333,20.,770.));
#2182=CARTESIAN_POINT('',(-35.9166666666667,20.,770.));
#2183=CARTESIAN_POINT('',(-35.8333333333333,20.,770.));
#2184=CARTESIAN_POINT('',(-35.6666666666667,20.,770.));
#2185=CARTESIAN_POINT('',(-35.5833333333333,20.,770.));
#2186=CARTESIAN_POINT('',(-35.4166666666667,20.,770.));
#2187=CARTESIAN_POINT('',(-35.3333333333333,20.,770.));
#2188=CARTESIAN_POINT('',(-35.1666666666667,20.,770.));
#2189=CARTESIAN_POINT('',(-35.0833333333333,20.,770.));
#2190=CARTESIAN_POINT('',(-34.9166666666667,20.,770.));
#2191=CARTESIAN_POINT('',(-34.8333333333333,20.,770.));
#2192=CARTESIAN_POINT('',(-34.6666666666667,20.,770.));
#2193=CARTESIAN_POINT('',(-34.5833333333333,20.,770.));
#2194=CARTESIAN_POINT('',(-34.4166666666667,20.,770.));
#2195=CARTESIAN_POINT('',(-34.3333333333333,20.,770.));
#2196=CARTESIAN_POINT('',(-34.1666666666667,20.,770.));
#2197=CARTESIAN_POINT('',(-34.0833333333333,20.,770.));
#2198=CARTESIAN_POINT('',(-33.9166666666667,20.,770.));
#2199=CARTESIAN_POINT('',(-33.8333333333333,20.,770.));
#2200=CARTESIAN_POINT('',(-33.6666666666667,20.,770.));
#2201=CARTESIAN_POINT('',(-33.5833333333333,20.,770.));
#2202=CARTESIAN_POINT('',(-33.4166666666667,20.,770.));
#2203=CARTESIAN_POINT('',(-33.3333333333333,20.,770.));
#2204=CARTESIAN_POINT('',(-33.1666666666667,20.,770.));
#2205=CARTESIAN_POINT('',(-33.0833333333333,20.,770.));
#2206=CARTESIAN_POINT('',(-32.9166666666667,20.,770.));
#2207=CARTESIAN_POINT('',(-32.8333333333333,20.,770.));
#2208=CARTESIAN_POINT('',(-32.6666666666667,20.,770.));
#2209=CARTESIAN_POINT('',(-32.5833333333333,20.,770.));
#2210=CARTESIAN_POINT('',(-32.4166666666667,20.,770.));
#2211=CARTESIAN_POINT('',(-32.3333333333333,20.,770.));
#2212=CARTESIAN_POINT('',(-32.1666666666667,20.,770.));
#2213=CARTESIAN_POINT('',(-32.0833333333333,20.,770.));
#2214=CARTESIAN_POINT('',(-32.,20.,770.));
#2215=B_SPLINE_CURVE_WITH_KNOTS('',3,(#2149,#2150,#2151,#2152,#2153,#2154,#2155,#2156,#2157,
#2158,#2159,#2160,#2161,#2162,#2163,#2164,#2165,#2166,#2167,#2168,#2169,#2170,#2171,#2172,#2173,
#2174,#2175,#2176,#2177,#2178,#2179,#2180,#2181,#2182,#2183,#2184,#2185,#2186,#2187,#2188,#2189,
#2190,#2191,#2192,#2193,#2194,#2195,#2196,#2197,#2198,#2199,#2200,#2201,#2202,#2203,#2204,#2205,
#2206,#2207,#2208,#2209,#2210,#2211,#2212,#2213,#2214),.UNSPECIFIED.,.F.,.F.,(4,2,2,2,2,2,2,2,2,
2,2,2,2,2,2,2,2,2,2,2,2,2,2,2,2,2,2,2,2,2,2,2,4),(0.,0.25,0.5,0.750000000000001,1.,1.25,1.5,
1.75,2.,2.25,2.5,2.75,3.,3.25,3.5,3.75,4.,4.25,4.5,4.75,5.,5.25,5.50000000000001,
5.75000000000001,6.00000000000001,6.25000000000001,6.50000000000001,6.75000000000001,
7.00000000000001,7.25000000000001,7.50000000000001,7.75000000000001,8.00000000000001),.UNSPECIFIED.);
#2216=EDGE_CURVE('BSEAM324',#163,#1154,#2215,.T.);
#2217=ORIENTED_EDGE('',*,*,#164,.T.);
#2218=ORIENTED_EDGE('',*,*,#1155,.F.);
#2219=ORIENTED_EDGE('',*,*,#2216,.T.);
#2220=ORIENTED_EDGE('',*,*,#2216,.F.);
#2221=EDGE_LOOP('',(#2217,#2219,#2218,#2220));
#2222=FACE_BOUND('',#2221,.T.);
#2223=ADVANCED_FACE('F324',(#2222),#2148,.F.);
#2224=CARTESIAN_POINT('',(40.,45.,850.));
#2225=DIRECTION('',(-1.,0.,0.));
#2226=DIRECTION('',(0.,-1.,0.));
#2227=AXIS2_PLACEMENT_3D('',#2224,#2225,#2226);
#2228=CYLINDRICAL_SURFACE('',#2227,25.);
#2229=CARTESIAN_POINT('',(-40.,20.,850.));
#2230=CARTESIAN_POINT('',(-39.9166666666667,20.,850.));
#2231=CARTESIAN_POINT('',(-39.8333333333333,20.,850.));
#2232=CARTESIAN_POINT('',(-39.6666666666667,20.,850.));
#2233=CARTESIAN_POINT('',(-39.5833333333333,20.,850.));
#2234=CARTESIAN_POINT('',(-39.4166666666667,20.,850.));
#2235=CARTESIAN_POINT('',(-39.3333333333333,20.,850.));
#2236=CARTESIAN_POINT('',(-39.1666666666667,20.,850.));
#2237=CARTESIAN_POINT('',(-39.0833333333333,20.,850.));
#2238=CARTESIAN_POINT('',(-38.9166666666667,20.,850.));
#2239=CARTESIAN_POINT('',(-38.8333333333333,20.,850.));
#2240=CARTESIAN_POINT('',(-38.6666666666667,20.,850.));
#2241=CARTESIAN_POINT('',(-38.5833333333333,20.,850.));
#2242=CARTESIAN_POINT('',(-38.4166666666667,20.,850.));
#2243=CARTESIAN_POINT('',(-38.3333333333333,20.,850.));
#2244=CARTESIAN_POINT('',(-38.1666666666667,20.,850.));
#2245=CARTESIAN_POINT('',(-38.0833333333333,20.,850.));
#2246=CARTESIAN_POINT('',(-37.9166666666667,20.,850.));
#2247=CARTESIAN_POINT('',(-37.8333333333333,20.,850.));
#2248=CARTESIAN_POINT('',(-37.6666666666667,20.,850.));
#2249=CARTESIAN_POINT('',(-37.5833333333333,20.,850.));
#2250=CARTESIAN_POINT('',(-37.4166666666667,20.,850.));
#2251=CARTESIAN_POINT('',(-37.3333333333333,20.,850.));
#2252=CARTESIAN_POINT('',(-37.1666666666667,20.,850.));
#2253=CARTESIAN_POINT('',(-37.0833333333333,20.,850.));
#2254=CARTESIAN_POINT('',(-36.9166666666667,20.,850.));
#2255=CARTESIAN_POINT('',(-36.8333333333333,20.,850.));
#2256=CARTESIAN_POINT('',(-36.6666666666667,20.,850.));
#2257=CARTESIAN_POINT('',(-36.5833333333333,20.,850.));
#2258=CARTESIAN_POINT('',(-36.4166666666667,20.,850.));
#2259=CARTESIAN_POINT('',(-36.3333333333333,20.,850.));
#2260=CARTESIAN_POINT('',(-36.1666666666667,20.,850.));
#2261=CARTESIAN_POINT('',(-36.0833333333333,20.,850.));
#2262=CARTESIAN_POINT('',(-35.9166666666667,20.,850.));
#2263=CARTESIAN_POINT('',(-35.8333333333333,20.,850.));
#2264=CARTESIAN_POINT('',(-35.6666666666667,20.,850.));
#2265=CARTESIAN_POINT('',(-35.5833333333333,20.,850.));
#2266=CARTESIAN_POINT('',(-35.4166666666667,20.,850.));
#2267=CARTESIAN_POINT('',(-35.3333333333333,20.,850.));
#2268=CARTESIAN_POINT('',(-35.1666666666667,20.,850.));
#2269=CARTESIAN_POINT('',(-35.0833333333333,20.,850.));
#2270=CARTESIAN_POINT('',(-34.9166666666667,20.,850.));
#2271=CARTESIAN_POINT('',(-34.8333333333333,20.,850.));
#2272=CARTESIAN_POINT('',(-34.6666666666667,20.,850.));
#2273=CARTESIAN_POINT('',(-34.5833333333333,20.,850.));
#2274=CARTESIAN_POINT('',(-34.4166666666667,20.,850.));
#2275=CARTESIAN_POINT('',(-34.3333333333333,20.,850.));
#2276=CARTESIAN_POINT('',(-34.1666666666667,20.,850.));
#2277=CARTESIAN_POINT('',(-34.0833333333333,20.,850.));
#2278=CARTESIAN_POINT('',(-33.9166666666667,20.,850.));
#2279=CARTESIAN_POINT('',(-33.8333333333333,20.,850.));
#2280=CARTESIAN_POINT('',(-33.6666666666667,20.,850.));
#2281=CARTESIAN_POINT('',(-33.5833333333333,20.,850.));
#2282=CARTESIAN_POINT('',(-33.4166666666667,20.,850.));
#2283=CARTESIAN_POINT('',(-33.3333333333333,20.,850.));
#2284=CARTESIAN_POINT('',(-33.1666666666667,20.,850.));
#2285=CARTESIAN_POINT('',(-33.0833333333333,20.,850.));
#2286=CARTESIAN_POINT('',(-32.9166666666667,20.,850.));
#2287=CARTESIAN_POINT('',(-32.8333333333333,20.,850.));
#2288=CARTESIAN_POINT('',(-32.6666666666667,20.,850.));
#2289=CARTESIAN_POINT('',(-32.5833333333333,20.,850.));
#2290=CARTESIAN_POINT('',(-32.4166666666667,20.,850.));
#2291=CARTESIAN_POINT('',(-32.3333333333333,20.,850.));
#2292=CARTESIAN_POINT('',(-32.1666666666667,20.,850.));
#2293=CARTESIAN_POINT('',(-32.0833333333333,20.,850.));
#2294=CARTESIAN_POINT('',(-32.,20.,850.));
#2295=B_SPLINE_CURVE_WITH_KNOTS('',3,(#2229,#2230,#2231,#2232,#2233,#2234,#2235,#2236,#2237,
#2238,#2239,#2240,#2241,#2242,#2243,#2244,#2245,#2246,#2247,#2248,#2249,#2250,#2251,#2252,#2253,
#2254,#2255,#2256,#2257,#2258,#2259,#2260,#2261,#2262,#2263,#2264,#2265,#2266,#2267,#2268,#2269,
#2270,#2271,#2272,#2273,#2274,#2275,#2276,#2277,#2278,#2279,#2280,#2281,#2282,#2283,#2284,#2285,
#2286,#2287,#2288,#2289,#2290,#2291,#2292,#2293,#2294),.UNSPECIFIED.,.F.,.F.,(4,2,2,2,2,2,2,2,2,
2,2,2,2,2,2,2,2,2,2,2,2,2,2,2,2,2,2,2,2,2,2,2,4),(0.,0.25,0.5,0.750000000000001,1.,1.25,1.5,
1.75,2.,2.25,2.5,2.75,3.,3.25,3.5,3.75,4.,4.25,4.5,4.75,5.,5.25,5.50000000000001,
5.75000000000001,6.00000000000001,6.25000000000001,6.50000000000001,6.75000000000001,
7.00000000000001,7.25000000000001,7.50000000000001,7.75000000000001,8.00000000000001),.UNSPECIFIED.);
#2296=EDGE_CURVE('BSEAM328',#174,#1165,#2295,.T.);
#2297=ORIENTED_EDGE('',*,*,#175,.T.);
#2298=ORIENTED_EDGE('',*,*,#1166,.F.);
#2299=ORIENTED_EDGE('',*,*,#2296,.T.);
#2300=ORIENTED_EDGE('',*,*,#2296,.F.);
#2301=EDGE_LOOP('',(#2297,#2299,#2298,#2300));
#2302=FACE_BOUND('',#2301,.T.);
#2303=ADVANCED_FACE('F328',(#2302),#2228,.F.);
#2304=CARTESIAN_POINT('',(40.,45.,930.));
#2305=DIRECTION('',(-1.,0.,0.));
#2306=DIRECTION('',(0.,-1.,0.));
#2307=AXIS2_PLACEMENT_3D('',#2304,#2305,#2306);
#2308=CYLINDRICAL_SURFACE('',#2307,25.);
#2309=CARTESIAN_POINT('',(-40.,20.,930.));
#2310=CARTESIAN_POINT('',(-39.9166666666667,20.,930.));
#2311=CARTESIAN_POINT('',(-39.8333333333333,20.,930.));
#2312=CARTESIAN_POINT('',(-39.6666666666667,20.,930.));
#2313=CARTESIAN_POINT('',(-39.5833333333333,20.,930.));
#2314=CARTESIAN_POINT('',(-39.4166666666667,20.,930.));
#2315=CARTESIAN_POINT('',(-39.3333333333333,20.,930.));
#2316=CARTESIAN_POINT('',(-39.1666666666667,20.,930.));
#2317=CARTESIAN_POINT('',(-39.0833333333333,20.,930.));
#2318=CARTESIAN_POINT('',(-38.9166666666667,20.,930.));
#2319=CARTESIAN_POINT('',(-38.8333333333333,20.,930.));
#2320=CARTESIAN_POINT('',(-38.6666666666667,20.,930.));
#2321=CARTESIAN_POINT('',(-38.5833333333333,20.,930.));
#2322=CARTESIAN_POINT('',(-38.4166666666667,20.,930.));
#2323=CARTESIAN_POINT('',(-38.3333333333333,20.,930.));
#2324=CARTESIAN_POINT('',(-38.1666666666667,20.,930.));
#2325=CARTESIAN_POINT('',(-38.0833333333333,20.,930.));
#2326=CARTESIAN_POINT('',(-37.9166666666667,20.,930.));
#2327=CARTESIAN_POINT('',(-37.8333333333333,20.,930.));
#2328=CARTESIAN_POINT('',(-37.6666666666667,20.,930.));
#2329=CARTESIAN_POINT('',(-37.5833333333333,20.,930.));
#2330=CARTESIAN_POINT('',(-37.4166666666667,20.,930.));
#2331=CARTESIAN_POINT('',(-37.3333333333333,20.,930.));
#2332=CARTESIAN_POINT('',(-37.1666666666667,20.,930.));
#2333=CARTESIAN_POINT('',(-37.0833333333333,20.,930.));
#2334=CARTESIAN_POINT('',(-36.9166666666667,20.,930.));
#2335=CARTESIAN_POINT('',(-36.8333333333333,20.,930.));
#2336=CARTESIAN_POINT('',(-36.6666666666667,20.,930.));
#2337=CARTESIAN_POINT('',(-36.5833333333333,20.,930.));
#2338=CARTESIAN_POINT('',(-36.4166666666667,20.,930.));
#2339=CARTESIAN_POINT('',(-36.3333333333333,20.,930.));
#2340=CARTESIAN_POINT('',(-36.1666666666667,20.,930.));
#2341=CARTESIAN_POINT('',(-36.0833333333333,20.,930.));
#2342=CARTESIAN_POINT('',(-35.9166666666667,20.,930.));
#2343=CARTESIAN_POINT('',(-35.8333333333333,20.,930.));
#2344=CARTESIAN_POINT('',(-35.6666666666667,20.,930.));
#2345=CARTESIAN_POINT('',(-35.5833333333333,20.,930.));
#2346=CARTESIAN_POINT('',(-35.4166666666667,20.,930.));
#2347=CARTESIAN_POINT('',(-35.3333333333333,20.,930.));
#2348=CARTESIAN_POINT('',(-35.1666666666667,20.,930.));
#2349=CARTESIAN_POINT('',(-35.0833333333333,20.,930.));
#2350=CARTESIAN_POINT('',(-34.9166666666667,20.,930.));
#2351=CARTESIAN_POINT('',(-34.8333333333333,20.,930.));
#2352=CARTESIAN_POINT('',(-34.6666666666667,20.,930.));
#2353=CARTESIAN_POINT('',(-34.5833333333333,20.,930.));
#2354=CARTESIAN_POINT('',(-34.4166666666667,20.,930.));
#2355=CARTESIAN_POINT('',(-34.3333333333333,20.,930.));
#2356=CARTESIAN_POINT('',(-34.1666666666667,20.,930.));
#2357=CARTESIAN_POINT('',(-34.0833333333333,20.,930.));
#2358=CARTESIAN_POINT('',(-33.9166666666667,20.,930.));
#2359=CARTESIAN_POINT('',(-33.8333333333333,20.,930.));
#2360=CARTESIAN_POINT('',(-33.6666666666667,20.,930.));
#2361=CARTESIAN_POINT('',(-33.5833333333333,20.,930.));
#2362=CARTESIAN_POINT('',(-33.4166666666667,20.,930.));
#2363=CARTESIAN_POINT('',(-33.3333333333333,20.,930.));
#2364=CARTESIAN_POINT('',(-33.1666666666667,20.,930.));
#2365=CARTESIAN_POINT('',(-33.0833333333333,20.,930.));
#2366=CARTESIAN_POINT('',(-32.9166666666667,20.,930.));
#2367=CARTESIAN_POINT('',(-32.8333333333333,20.,930.));
#2368=CARTESIAN_POINT('',(-32.6666666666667,20.,930.));
#2369=CARTESIAN_POINT('',(-32.5833333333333,20.,930.));
#2370=CARTESIAN_POINT('',(-32.4166666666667,20.,930.));
#2371=CARTESIAN_POINT('',(-32.3333333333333,20.,930.));
#2372=CARTESIAN_POINT('',(-32.1666666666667,20.,930.));
#2373=CARTESIAN_POINT('',(-32.0833333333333,20.,930.));
#2374=CARTESIAN_POINT('',(-32.,20.,930.));
#2375=B_SPLINE_CURVE_WITH_KNOTS('',3,(#2309,#2310,#2311,#2312,#2313,#2314,#2315,#2316,#2317,
#2318,#2319,#2320,#2321,#2322,#2323,#2324,#2325,#2326,#2327,#2328,#2329,#2330,#2331,#2332,#2333,
#2334,#2335,#2336,#2337,#2338,#2339,#2340,#2341,#2342,#2343,#2344,#2345,#2346,#2347,#2348,#2349,
#2350,#2351,#2352,#2353,#2354,#2355,#2356,#2357,#2358,#2359,#2360,#2361,#2362,#2363,#2364,#2365,
#2366,#2367,#2368,#2369,#2370,#2371,#2372,#2373,#2374),.UNSPECIFIED.,.F.,.F.,(4,2,2,2,2,2,2,2,2,
2,2,2,2,2,2,2,2,2,2,2,2,2,2,2,2,2,2,2,2,2,2,2,4),(0.,0.25,0.5,0.750000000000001,1.,1.25,1.5,
1.75,2.,2.25,2.5,2.75,3.,3.25,3.5,3.75,4.,4.25,4.5,4.75,5.,5.25,5.50000000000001,
5.75000000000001,6.00000000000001,6.25000000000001,6.50000000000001,6.75000000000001,
7.00000000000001,7.25000000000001,7.50000000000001,7.75000000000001,8.00000000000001),.UNSPECIFIED.);
#2376=EDGE_CURVE('BSEAM332',#185,#1176,#2375,.T.);
#2377=ORIENTED_EDGE('',*,*,#186,.T.);
#2378=ORIENTED_EDGE('',*,*,#1177,.F.);
#2379=ORIENTED_EDGE('',*,*,#2376,.T.);
#2380=ORIENTED_EDGE('',*,*,#2376,.F.);
#2381=EDGE_LOOP('',(#2377,#2379,#2378,#2380));
#2382=FACE_BOUND('',#2381,.T.);
#2383=ADVANCED_FACE('F332',(#2382),#2308,.F.);
#2384=CARTESIAN_POINT('',(40.,45.,1010.));
#2385=DIRECTION('',(-1.,0.,0.));
#2386=DIRECTION('',(0.,-1.,0.));
#2387=AXIS2_PLACEMENT_3D('',#2384,#2385,#2386);
#2388=CYLINDRICAL_SURFACE('',#2387,25.);
#2389=CARTESIAN_POINT('',(-40.,20.,1010.));
#2390=CARTESIAN_POINT('',(-39.9166666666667,20.,1010.));
#2391=CARTESIAN_POINT('',(-39.8333333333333,20.,1010.));
#2392=CARTESIAN_POINT('',(-39.6666666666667,20.,1010.));
#2393=CARTESIAN_POINT('',(-39.5833333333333,20.,1010.));
#2394=CARTESIAN_POINT('',(-39.4166666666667,20.,1010.));
#2395=CARTESIAN_POINT('',(-39.3333333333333,20.,1010.));
#2396=CARTESIAN_POINT('',(-39.1666666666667,20.,1010.));
#2397=CARTESIAN_POINT('',(-39.0833333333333,20.,1010.));
#2398=CARTESIAN_POINT('',(-38.9166666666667,20.,1010.));
#2399=CARTESIAN_POINT('',(-38.8333333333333,20.,1010.));
#2400=CARTESIAN_POINT('',(-38.6666666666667,20.,1010.));
#2401=CARTESIAN_POINT('',(-38.5833333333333,20.,1010.));
#2402=CARTESIAN_POINT('',(-38.4166666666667,20.,1010.));
#2403=CARTESIAN_POINT('',(-38.3333333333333,20.,1010.));
#2404=CARTESIAN_POINT('',(-38.1666666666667,20.,1010.));
#2405=CARTESIAN_POINT('',(-38.0833333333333,20.,1010.));
#2406=CARTESIAN_POINT('',(-37.9166666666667,20.,1010.));
#2407=CARTESIAN_POINT('',(-37.8333333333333,20.,1010.));
#2408=CARTESIAN_POINT('',(-37.6666666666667,20.,1010.));
#2409=CARTESIAN_POINT('',(-37.5833333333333,20.,1010.));
#2410=CARTESIAN_POINT('',(-37.4166666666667,20.,1010.));
#2411=CARTESIAN_POINT('',(-37.3333333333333,20.,1010.));
#2412=CARTESIAN_POINT('',(-37.1666666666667,20.,1010.));
#2413=CARTESIAN_POINT('',(-37.0833333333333,20.,1010.));
#2414=CARTESIAN_POINT('',(-36.9166666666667,20.,1010.));
#2415=CARTESIAN_POINT('',(-36.8333333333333,20.,1010.));
#2416=CARTESIAN_POINT('',(-36.6666666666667,20.,1010.));
#2417=CARTESIAN_POINT('',(-36.5833333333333,20.,1010.));
#2418=CARTESIAN_POINT('',(-36.4166666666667,20.,1010.));
#2419=CARTESIAN_POINT('',(-36.3333333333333,20.,1010.));
#2420=CARTESIAN_POINT('',(-36.1666666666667,20.,1010.));
#2421=CARTESIAN_POINT('',(-36.0833333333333,20.,1010.));
#2422=CARTESIAN_POINT('',(-35.9166666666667,20.,1010.));
#2423=CARTESIAN_POINT('',(-35.8333333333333,20.,1010.));
#2424=CARTESIAN_POINT('',(-35.6666666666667,20.,1010.));
#2425=CARTESIAN_POINT('',(-35.5833333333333,20.,1010.));
#2426=CARTESIAN_POINT('',(-35.4166666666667,20.,1010.));
#2427=CARTESIAN_POINT('',(-35.3333333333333,20.,1010.));
#2428=CARTESIAN_POINT('',(-35.1666666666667,20.,1010.));
#2429=CARTESIAN_POINT('',(-35.0833333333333,20.,1010.));
#2430=CARTESIAN_POINT('',(-34.9166666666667,20.,1010.));
#2431=CARTESIAN_POINT('',(-34.8333333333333,20.,1010.));
#2432=CARTESIAN_POINT('',(-34.6666666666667,20.,1010.));
#2433=CARTESIAN_POINT('',(-34.5833333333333,20.,1010.));
#2434=CARTESIAN_POINT('',(-34.4166666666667,20.,1010.));
#2435=CARTESIAN_POINT('',(-34.3333333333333,20.,1010.));
#2436=CARTESIAN_POINT('',(-34.1666666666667,20.,1010.));
#2437=CARTESIAN_POINT('',(-34.0833333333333,20.,1010.));
#2438=CARTESIAN_POINT('',(-33.9166666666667,20.,1010.));
#2439=CARTESIAN_POINT('',(-33.8333333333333,20.,1010.));
#2440=CARTESIAN_POINT('',(-33.6666666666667,20.,1010.));
#2441=CARTESIAN_POINT('',(-33.5833333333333,20.,1010.));
#2442=CARTESIAN_POINT('',(-33.4166666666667,20.,1010.));
#2443=CARTESIAN_POINT('',(-33.3333333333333,20.,1010.));
#2444=CARTESIAN_POINT('',(-33.1666666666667,20.,1010.));
#2445=CARTESIAN_POINT('',(-33.0833333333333,20.,1010.));
#2446=CARTESIAN_POINT('',(-32.9166666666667,20.,1010.));
#2447=CARTESIAN_POINT('',(-32.8333333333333,20.,1010.));
#2448=CARTESIAN_POINT('',(-32.6666666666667,20.,1010.));
#2449=CARTESIAN_POINT('',(-32.5833333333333,20.,1010.));
#2450=CARTESIAN_POINT('',(-32.4166666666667,20.,1010.));
#2451=CARTESIAN_POINT('',(-32.3333333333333,20.,1010.));
#2452=CARTESIAN_POINT('',(-32.1666666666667,20.,1010.));
#2453=CARTESIAN_POINT('',(-32.0833333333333,20.,1010.));
#2454=CARTESIAN_POINT('',(-32.,20.,1010.));
#2455=B_SPLINE_CURVE_WITH_KNOTS('',3,(#2389,#2390,#2391,#2392,#2393,#2394,#2395,#2396,#2397,
#2398,#2399,#2400,#2401,#2402,#2403,#2404,#2405,#2406,#2407,#2408,#2409,#2410,#2411,#2412,#2413,
#2414,#2415,#2416,#2417,#2418,#2419,#2420,#2421,#2422,#2423,#2424,#2425,#2426,#2427,#2428,#2429,
#2430,#2431,#2432,#2433,#2434,#2435,#2436,#2437,#2438,#2439,#2440,#2441,#2442,#2443,#2444,#2445,
#2446,#2447,#2448,#2449,#2450,#2451,#2452,#2453,#2454),.UNSPECIFIED.,.F.,.F.,(4,2,2,2,2,2,2,2,2,
2,2,2,2,2,2,2,2,2,2,2,2,2,2,2,2,2,2,2,2,2,2,2,4),(0.,0.25,0.5,0.750000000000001,1.,1.25,1.5,
1.75,2.,2.25,2.5,2.75,3.,3.25,3.5,3.75,4.,4.25,4.5,4.75,5.,5.25,5.50000000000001,
5.75000000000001,6.00000000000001,6.25000000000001,6.50000000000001,6.75000000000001,
7.00000000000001,7.25000000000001,7.50000000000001,7.75000000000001,8.00000000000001),.UNSPECIFIED.);
#2456=EDGE_CURVE('BSEAM336',#196,#1187,#2455,.T.);
#2457=ORIENTED_EDGE('',*,*,#197,.T.);
#2458=ORIENTED_EDGE('',*,*,#1188,.F.);
#2459=ORIENTED_EDGE('',*,*,#2456,.T.);
#2460=ORIENTED_EDGE('',*,*,#2456,.F.);
#2461=EDGE_LOOP('',(#2457,#2459,#2458,#2460));
#2462=FACE_BOUND('',#2461,.T.);
#2463=ADVANCED_FACE('F336',(#2462),#2388,.F.);
#2464=CARTESIAN_POINT('',(40.,45.,1090.));
#2465=DIRECTION('',(-1.,0.,0.));
#2466=DIRECTION('',(0.,-1.,0.));
#2467=AXIS2_PLACEMENT_3D('',#2464,#2465,#2466);
#2468=CYLINDRICAL_SURFACE('',#2467,25.);
#2469=CARTESIAN_POINT('',(-40.,20.,1090.));
#2470=CARTESIAN_POINT('',(-39.9166666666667,20.,1090.));
#2471=CARTESIAN_POINT('',(-39.8333333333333,20.,1090.));
#2472=CARTESIAN_POINT('',(-39.6666666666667,20.,1090.));
#2473=CARTESIAN_POINT('',(-39.5833333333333,20.,1090.));
#2474=CARTESIAN_POINT('',(-39.4166666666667,20.,1090.));
#2475=CARTESIAN_POINT('',(-39.3333333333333,20.,1090.));
#2476=CARTESIAN_POINT('',(-39.1666666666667,20.,1090.));
#2477=CARTESIAN_POINT('',(-39.0833333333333,20.,1090.));
#2478=CARTESIAN_POINT('',(-38.9166666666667,20.,1090.));
#2479=CARTESIAN_POINT('',(-38.8333333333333,20.,1090.));
#2480=CARTESIAN_POINT('',(-38.6666666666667,20.,1090.));
#2481=CARTESIAN_POINT('',(-38.5833333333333,20.,1090.));
#2482=CARTESIAN_POINT('',(-38.4166666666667,20.,1090.));
#2483=CARTESIAN_POINT('',(-38.3333333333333,20.,1090.));
#2484=CARTESIAN_POINT('',(-38.1666666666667,20.,1090.));
#2485=CARTESIAN_POINT('',(-38.0833333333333,20.,1090.));
#2486=CARTESIAN_POINT('',(-37.9166666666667,20.,1090.));
#2487=CARTESIAN_POINT('',(-37.8333333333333,20.,1090.));
#2488=CARTESIAN_POINT('',(-37.6666666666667,20.,1090.));
#2489=CARTESIAN_POINT('',(-37.5833333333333,20.,1090.));
#2490=CARTESIAN_POINT('',(-37.4166666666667,20.,1090.));
#2491=CARTESIAN_POINT('',(-37.3333333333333,20.,1090.));
#2492=CARTESIAN_POINT('',(-37.1666666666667,20.,1090.));
#2493=CARTESIAN_POINT('',(-37.0833333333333,20.,1090.));
#2494=CARTESIAN_POINT('',(-36.9166666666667,20.,1090.));
#2495=CARTESIAN_POINT('',(-36.8333333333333,20.,1090.));
#2496=CARTESIAN_POINT('',(-36.6666666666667,20.,1090.));
#2497=CARTESIAN_POINT('',(-36.5833333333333,20.,1090.));
#2498=CARTESIAN_POINT('',(-36.4166666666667,20.,1090.));
#2499=CARTESIAN_POINT('',(-36.3333333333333,20.,1090.));
#2500=CARTESIAN_POINT('',(-36.1666666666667,20.,1090.));
#2501=CARTESIAN_POINT('',(-36.0833333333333,20.,1090.));
#2502=CARTESIAN_POINT('',(-35.9166666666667,20.,1090.));
#2503=CARTESIAN_POINT('',(-35.8333333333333,20.,1090.));
#2504=CARTESIAN_POINT('',(-35.6666666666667,20.,1090.));
#2505=CARTESIAN_POINT('',(-35.5833333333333,20.,1090.));
#2506=CARTESIAN_POINT('',(-35.4166666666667,20.,1090.));
#2507=CARTESIAN_POINT('',(-35.3333333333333,20.,1090.));
#2508=CARTESIAN_POINT('',(-35.1666666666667,20.,1090.));
#2509=CARTESIAN_POINT('',(-35.0833333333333,20.,1090.));
#2510=CARTESIAN_POINT('',(-34.9166666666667,20.,1090.));
#2511=CARTESIAN_POINT('',(-34.8333333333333,20.,1090.));
#2512=CARTESIAN_POINT('',(-34.6666666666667,20.,1090.));
#2513=CARTESIAN_POINT('',(-34.5833333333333,20.,1090.));
#2514=CARTESIAN_POINT('',(-34.4166666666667,20.,1090.));
#2515=CARTESIAN_POINT('',(-34.3333333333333,20.,1090.));
#2516=CARTESIAN_POINT('',(-34.1666666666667,20.,1090.));
#2517=CARTESIAN_POINT('',(-34.0833333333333,20.,1090.));
#2518=CARTESIAN_POINT('',(-33.9166666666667,20.,1090.));
#2519=CARTESIAN_POINT('',(-33.8333333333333,20.,1090.));
#2520=CARTESIAN_POINT('',(-33.6666666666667,20.,1090.));
#2521=CARTESIAN_POINT('',(-33.5833333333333,20.,1090.));
#2522=CARTESIAN_POINT('',(-33.4166666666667,20.,1090.));
#2523=CARTESIAN_POINT('',(-33.3333333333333,20.,1090.));
#2524=CARTESIAN_POINT('',(-33.1666666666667,20.,1090.));
#2525=CARTESIAN_POINT('',(-33.0833333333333,20.,1090.));
#2526=CARTESIAN_POINT('',(-32.9166666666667,20.,1090.));
#2527=CARTESIAN_POINT('',(-32.8333333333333,20.,1090.));
#2528=CARTESIAN_POINT('',(-32.6666666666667,20.,1090.));
#2529=CARTESIAN_POINT('',(-32.5833333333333,20.,1090.));
#2530=CARTESIAN_POINT('',(-32.4166666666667,20.,1090.));
#2531=CARTESIAN_POINT('',(-32.3333333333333,20.,1090.));
#2532=CARTESIAN_POINT('',(-32.1666666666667,20.,1090.));
#2533=CARTESIAN_POINT('',(-32.0833333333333,20.,1090.));
#2534=CARTESIAN_POINT('',(-32.,20.,1090.));
#2535=B_SPLINE_CURVE_WITH_KNOTS('',3,(#2469,#2470,#2471,#2472,#2473,#2474,#2475,#2476,#2477,
#2478,#2479,#2480,#2481,#2482,#2483,#2484,#2485,#2486,#2487,#2488,#2489,#2490,#2491,#2492,#2493,
#2494,#2495,#2496,#2497,#2498,#2499,#2500,#2501,#2502,#2503,#2504,#2505,#2506,#2507,#2508,#2509,
#2510,#2511,#2512,#2513,#2514,#2515,#2516,#2517,#2518,#2519,#2520,#2521,#2522,#2523,#2524,#2525,
#2526,#2527,#2528,#2529,#2530,#2531,#2532,#2533,#2534),.UNSPECIFIED.,.F.,.F.,(4,2,2,2,2,2,2,2,2,
2,2,2,2,2,2,2,2,2,2,2,2,2,2,2,2,2,2,2,2,2,2,2,4),(0.,0.25,0.5,0.750000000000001,1.,1.25,1.5,
1.75,2.,2.25,2.5,2.75,3.,3.25,3.5,3.75,4.,4.25,4.5,4.75,5.,5.25,5.50000000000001,
5.75000000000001,6.00000000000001,6.25000000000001,6.50000000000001,6.75000000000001,
7.00000000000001,7.25000000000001,7.50000000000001,7.75000000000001,8.00000000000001),.UNSPECIFIED.);
#2536=EDGE_CURVE('BSEAM340',#207,#1198,#2535,.T.);
#2537=ORIENTED_EDGE('',*,*,#208,.T.);
#2538=ORIENTED_EDGE('',*,*,#1199,.F.);
#2539=ORIENTED_EDGE('',*,*,#2536,.T.);
#2540=ORIENTED_EDGE('',*,*,#2536,.F.);
#2541=EDGE_LOOP('',(#2537,#2539,#2538,#2540));
#2542=FACE_BOUND('',#2541,.T.);
#2543=ADVANCED_FACE('F340',(#2542),#2468,.F.);
#2544=CARTESIAN_POINT('',(40.,45.,1170.));
#2545=DIRECTION('',(-1.,0.,0.));
#2546=DIRECTION('',(0.,-1.,0.));
#2547=AXIS2_PLACEMENT_3D('',#2544,#2545,#2546);
#2548=CYLINDRICAL_SURFACE('',#2547,25.);
#2549=CARTESIAN_POINT('',(-40.,20.,1170.));
#2550=CARTESIAN_POINT('',(-39.9166666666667,20.,1170.));
#2551=CARTESIAN_POINT('',(-39.8333333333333,20.,1170.));
#2552=CARTESIAN_POINT('',(-39.6666666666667,20.,1170.));
#2553=CARTESIAN_POINT('',(-39.5833333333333,20.,1170.));
#2554=CARTESIAN_POINT('',(-39.4166666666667,20.,1170.));
#2555=CARTESIAN_POINT('',(-39.3333333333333,20.,1170.));
#2556=CARTESIAN_POINT('',(-39.1666666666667,20.,1170.));
#2557=CARTESIAN_POINT('',(-39.0833333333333,20.,1170.));
#2558=CARTESIAN_POINT('',(-38.9166666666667,20.,1170.));
#2559=CARTESIAN_POINT('',(-38.8333333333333,20.,1170.));
#2560=CARTESIAN_POINT('',(-38.6666666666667,20.,1170.));
#2561=CARTESIAN_POINT('',(-38.5833333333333,20.,1170.));
#2562=CARTESIAN_POINT('',(-38.4166666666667,20.,1170.));
#2563=CARTESIAN_POINT('',(-38.3333333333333,20.,1170.));
#2564=CARTESIAN_POINT('',(-38.1666666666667,20.,1170.));
#2565=CARTESIAN_POINT('',(-38.0833333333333,20.,1170.));
#2566=CARTESIAN_POINT('',(-37.9166666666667,20.,1170.));
#2567=CARTESIAN_POINT('',(-37.8333333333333,20.,1170.));
#2568=CARTESIAN_POINT('',(-37.6666666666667,20.,1170.));
#2569=CARTESIAN_POINT('',(-37.5833333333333,20.,1170.));
#2570=CARTESIAN_POINT('',(-37.4166666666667,20.,1170.));
#2571=CARTESIAN_POINT('',(-37.3333333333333,20.,1170.));
#2572=CARTESIAN_POINT('',(-37.1666666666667,20.,1170.));
#2573=CARTESIAN_POINT('',(-37.0833333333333,20.,1170.));
#2574=CARTESIAN_POINT('',(-36.9166666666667,20.,1170.));
#2575=CARTESIAN_POINT('',(-36.8333333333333,20.,1170.));
#2576=CARTESIAN_POINT('',(-36.6666666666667,20.,1170.));
#2577=CARTESIAN_POINT('',(-36.5833333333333,20.,1170.));
#2578=CARTESIAN_POINT('',(-36.4166666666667,20.,1170.));
#2579=CARTESIAN_POINT('',(-36.3333333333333,20.,1170.));
#2580=CARTESIAN_POINT('',(-36.1666666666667,20.,1170.));
#2581=CARTESIAN_POINT('',(-36.0833333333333,20.,1170.));
#2582=CARTESIAN_POINT('',(-35.9166666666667,20.,1170.));
#2583=CARTESIAN_POINT('',(-35.8333333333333,20.,1170.));
#2584=CARTESIAN_POINT('',(-35.6666666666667,20.,1170.));
#2585=CARTESIAN_POINT('',(-35.5833333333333,20.,1170.));
#2586=CARTESIAN_POINT('',(-35.4166666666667,20.,1170.));
#2587=CARTESIAN_POINT('',(-35.3333333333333,20.,1170.));
#2588=CARTESIAN_POINT('',(-35.1666666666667,20.,1170.));
#2589=CARTESIAN_POINT('',(-35.0833333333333,20.,1170.));
#2590=CARTESIAN_POINT('',(-34.9166666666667,20.,1170.));
#2591=CARTESIAN_POINT('',(-34.8333333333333,20.,1170.));
#2592=CARTESIAN_POINT('',(-34.6666666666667,20.,1170.));
#2593=CARTESIAN_POINT('',(-34.5833333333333,20.,1170.));
#2594=CARTESIAN_POINT('',(-34.4166666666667,20.,1170.));
#2595=CARTESIAN_POINT('',(-34.3333333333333,20.,1170.));
#2596=CARTESIAN_POINT('',(-34.1666666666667,20.,1170.));
#2597=CARTESIAN_POINT('',(-34.0833333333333,20.,1170.));
#2598=CARTESIAN_POINT('',(-33.9166666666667,20.,1170.));
#2599=CARTESIAN_POINT('',(-33.8333333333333,20.,1170.));
#2600=CARTESIAN_POINT('',(-33.6666666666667,20.,1170.));
#2601=CARTESIAN_POINT('',(-33.5833333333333,20.,1170.));
#2602=CARTESIAN_POINT('',(-33.4166666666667,20.,1170.));
#2603=CARTESIAN_POINT('',(-33.3333333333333,20.,1170.));
#2604=CARTESIAN_POINT('',(-33.1666666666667,20.,1170.));
#2605=CARTESIAN_POINT('',(-33.0833333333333,20.,1170.));
#2606=CARTESIAN_POINT('',(-32.9166666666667,20.,1170.));
#2607=CARTESIAN_POINT('',(-32.8333333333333,20.,1170.));
#2608=CARTESIAN_POINT('',(-32.6666666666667,20.,1170.));
#2609=CARTESIAN_POINT('',(-32.5833333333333,20.,1170.));
#2610=CARTESIAN_POINT('',(-32.4166666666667,20.,1170.));
#2611=CARTESIAN_POINT('',(-32.3333333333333,20.,1170.));
#2612=CARTESIAN_POINT('',(-32.1666666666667,20.,1170.));
#2613=CARTESIAN_POINT('',(-32.0833333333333,20.,1170.));
#2614=CARTESIAN_POINT('',(-32.,20.,1170.));
#2615=B_SPLINE_CURVE_WITH_KNOTS('',3,(#2549,#2550,#2551,#2552,#2553,#2554,#2555,#2556,#2557,
#2558,#2559,#2560,#2561,#2562,#2563,#2564,#2565,#2566,#2567,#2568,#2569,#2570,#2571,#2572,#2573,
#2574,#2575,#2576,#2577,#2578,#2579,#2580,#2581,#2582,#2583,#2584,#2585,#2586,#2587,#2588,#2589,
#2590,#2591,#2592,#2593,#2594,#2595,#2596,#2597,#2598,#2599,#2600,#2601,#2602,#2603,#2604,#2605,
#2606,#2607,#2608,#2609,#2610,#2611,#2612,#2613,#2614),.UNSPECIFIED.,.F.,.F.,(4,2,2,2,2,2,2,2,2,
2,2,2,2,2,2,2,2,2,2,2,2,2,2,2,2,2,2,2,2,2,2,2,4),(0.,0.25,0.5,0.750000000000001,1.,1.25,1.5,
1.75,2.,2.25,2.5,2.75,3.,3.25,3.5,3.75,4.,4.25,4.5,4.75,5.,5.25,5.50000000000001,
5.75000000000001,6.00000000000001,6.25000000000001,6.50000000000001,6.75000000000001,
7.00000000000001,7.25000000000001,7.50000000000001,7.75000000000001,8.00000000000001),.UNSPECIFIED.);
#2616=EDGE_CURVE('BSEAM344',#218,#1209,#2615,.T.);
#2617=ORIENTED_EDGE('',*,*,#219,.T.);
#2618=ORIENTED_EDGE('',*,*,#1210,.F.);
#2619=ORIENTED_EDGE('',*,*,#2616,.T.);
#2620=ORIENTED_EDGE('',*,*,#2616,.F.);
#2621=EDGE_LOOP('',(#2617,#2619,#2618,#2620));
#2622=FACE_BOUND('',#2621,.T.);
#2623=ADVANCED_FACE('F344',(#2622),#2548,.F.);
#2624=CARTESIAN_POINT('',(40.,45.,1250.));
#2625=DIRECTION('',(-1.,0.,0.));
#2626=DIRECTION('',(0.,-1.,0.));
#2627=AXIS2_PLACEMENT_3D('',#2624,#2625,#2626);
#2628=CYLINDRICAL_SURFACE('',#2627,25.);
#2629=CARTESIAN_POINT('',(-40.,20.,1250.));
#2630=CARTESIAN_POINT('',(-39.9166666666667,20.,1250.));
#2631=CARTESIAN_POINT('',(-39.8333333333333,20.,1250.));
#2632=CARTESIAN_POINT('',(-39.6666666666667,20.,1250.));
#2633=CARTESIAN_POINT('',(-39.5833333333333,20.,1250.));
#2634=CARTESIAN_POINT('',(-39.4166666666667,20.,1250.));
#2635=CARTESIAN_POINT('',(-39.3333333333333,20.,1250.));
#2636=CARTESIAN_POINT('',(-39.1666666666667,20.,1250.));
#2637=CARTESIAN_POINT('',(-39.0833333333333,20.,1250.));
#2638=CARTESIAN_POINT('',(-38.9166666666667,20.,1250.));
#2639=CARTESIAN_POINT('',(-38.8333333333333,20.,1250.));
#2640=CARTESIAN_POINT('',(-38.6666666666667,20.,1250.));
#2641=CARTESIAN_POINT('',(-38.5833333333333,20.,1250.));
#2642=CARTESIAN_POINT('',(-38.4166666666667,20.,1250.));
#2643=CARTESIAN_POINT('',(-38.3333333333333,20.,1250.));
#2644=CARTESIAN_POINT('',(-38.1666666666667,20.,1250.));
#2645=CARTESIAN_POINT('',(-38.0833333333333,20.,1250.));
#2646=CARTESIAN_POINT('',(-37.9166666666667,20.,1250.));
#2647=CARTESIAN_POINT('',(-37.8333333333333,20.,1250.));
#2648=CARTESIAN_POINT('',(-37.6666666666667,20.,1250.));
#2649=CARTESIAN_POINT('',(-37.5833333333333,20.,1250.));
#2650=CARTESIAN_POINT('',(-37.4166666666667,20.,1250.));
#2651=CARTESIAN_POINT('',(-37.3333333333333,20.,1250.));
#2652=CARTESIAN_POINT('',(-37.1666666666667,20.,1250.));
#2653=CARTESIAN_POINT('',(-37.0833333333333,20.,1250.));
#2654=CARTESIAN_POINT('',(-36.9166666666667,20.,1250.));
#2655=CARTESIAN_POINT('',(-36.8333333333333,20.,1250.));
#2656=CARTESIAN_POINT('',(-36.6666666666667,20.,1250.));
#2657=CARTESIAN_POINT('',(-36.5833333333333,20.,1250.));
#2658=CARTESIAN_POINT('',(-36.4166666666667,20.,1250.));
#2659=CARTESIAN_POINT('',(-36.3333333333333,20.,1250.));
#2660=CARTESIAN_POINT('',(-36.1666666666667,20.,1250.));
#2661=CARTESIAN_POINT('',(-36.0833333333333,20.,1250.));
#2662=CARTESIAN_POINT('',(-35.9166666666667,20.,1250.));
#2663=CARTESIAN_POINT('',(-35.8333333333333,20.,1250.));
#2664=CARTESIAN_POINT('',(-35.6666666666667,20.,1250.));
#2665=CARTESIAN_POINT('',(-35.5833333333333,20.,1250.));
#2666=CARTESIAN_POINT('',(-35.4166666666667,20.,1250.));
#2667=CARTESIAN_POINT('',(-35.3333333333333,20.,1250.));
#2668=CARTESIAN_POINT('',(-35.1666666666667,20.,1250.));
#2669=CARTESIAN_POINT('',(-35.0833333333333,20.,1250.));
#2670=CARTESIAN_POINT('',(-34.9166666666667,20.,1250.));
#2671=CARTESIAN_POINT('',(-34.8333333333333,20.,1250.));
#2672=CARTESIAN_POINT('',(-34.6666666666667,20.,1250.));
#2673=CARTESIAN_POINT('',(-34.5833333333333,20.,1250.));
#2674=CARTESIAN_POINT('',(-34.4166666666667,20.,1250.));
#2675=CARTESIAN_POINT('',(-34.3333333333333,20.,1250.));
#2676=CARTESIAN_POINT('',(-34.1666666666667,20.,1250.));
#2677=CARTESIAN_POINT('',(-34.0833333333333,20.,1250.));
#2678=CARTESIAN_POINT('',(-33.9166666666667,20.,1250.));
#2679=CARTESIAN_POINT('',(-33.8333333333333,20.,1250.));
#2680=CARTESIAN_POINT('',(-33.6666666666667,20.,1250.));
#2681=CARTESIAN_POINT('',(-33.5833333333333,20.,1250.));
#2682=CARTESIAN_POINT('',(-33.4166666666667,20.,1250.));
#2683=CARTESIAN_POINT('',(-33.3333333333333,20.,1250.));
#2684=CARTESIAN_POINT('',(-33.1666666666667,20.,1250.));
#2685=CARTESIAN_POINT('',(-33.0833333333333,20.,1250.));
#2686=CARTESIAN_POINT('',(-32.9166666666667,20.,1250.));
#2687=CARTESIAN_POINT('',(-32.8333333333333,20.,1250.));
#2688=CARTESIAN_POINT('',(-32.6666666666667,20.,1250.));
#2689=CARTESIAN_POINT('',(-32.5833333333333,20.,1250.));
#2690=CARTESIAN_POINT('',(-32.4166666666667,20.,1250.));
#2691=CARTESIAN_POINT('',(-32.3333333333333,20.,1250.));
#2692=CARTESIAN_POINT('',(-32.1666666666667,20.,1250.));
#2693=CARTESIAN_POINT('',(-32.0833333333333,20.,1250.));
#2694=CARTESIAN_POINT('',(-32.,20.,1250.));
#2695=B_SPLINE_CURVE_WITH_KNOTS('',3,(#2629,#2630,#2631,#2632,#2633,#2634,#2635,#2636,#2637,
#2638,#2639,#2640,#2641,#2642,#2643,#2644,#2645,#2646,#2647,#2648,#2649,#2650,#2651,#2652,#2653,
#2654,#2655,#2656,#2657,#2658,#2659,#2660,#2661,#2662,#2663,#2664,#2665,#2666,#2667,#2668,#2669,
#2670,#2671,#2672,#2673,#2674,#2675,#2676,#2677,#2678,#2679,#2680,#2681,#2682,#2683,#2684,#2685,
#2686,#2687,#2688,#2689,#2690,#2691,#2692,#2693,#2694),.UNSPECIFIED.,.F.,.F.,(4,2,2,2,2,2,2,2,2,
2,2,2,2,2,2,2,2,2,2,2,2,2,2,2,2,2,2,2,2,2,2,2,4),(0.,0.25,0.5,0.750000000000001,1.,1.25,1.5,
1.75,2.,2.25,2.5,2.75,3.,3.25,3.5,3.75,4.,4.25,4.5,4.75,5.,5.25,5.50000000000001,
5.75000000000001,6.00000000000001,6.25000000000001,6.50000000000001,6.75000000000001,
7.00000000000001,7.25000000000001,7.50000000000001,7.75000000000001,8.00000000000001),.UNSPECIFIED.);
#2696=EDGE_CURVE('BSEAM348',#229,#1220,#2695,.T.);
#2697=ORIENTED_EDGE('',*,*,#230,.T.);
#2698=ORIENTED_EDGE('',*,*,#1221,.F.);
#2699=ORIENTED_EDGE('',*,*,#2696,.T.);
#2700=ORIENTED_EDGE('',*,*,#2696,.F.);
#2701=EDGE_LOOP('',(#2697,#2699,#2698,#2700));
#2702=FACE_BOUND('',#2701,.T.);
#2703=ADVANCED_FACE('F348',(#2702),#2628,.F.);
#2704=CARTESIAN_POINT('',(40.,45.,1330.));
#2705=DIRECTION('',(-1.,0.,0.));
#2706=DIRECTION('',(0.,-1.,0.));
#2707=AXIS2_PLACEMENT_3D('',#2704,#2705,#2706);
#2708=CYLINDRICAL_SURFACE('',#2707,25.);
#2709=CARTESIAN_POINT('',(-40.,20.,1330.));
#2710=CARTESIAN_POINT('',(-39.9166666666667,20.,1330.));
#2711=CARTESIAN_POINT('',(-39.8333333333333,20.,1330.));
#2712=CARTESIAN_POINT('',(-39.6666666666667,20.,1330.));
#2713=CARTESIAN_POINT('',(-39.5833333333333,20.,1330.));
#2714=CARTESIAN_POINT('',(-39.4166666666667,20.,1330.));
#2715=CARTESIAN_POINT('',(-39.3333333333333,20.,1330.));
#2716=CARTESIAN_POINT('',(-39.1666666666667,20.,1330.));
#2717=CARTESIAN_POINT('',(-39.0833333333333,20.,1330.));
#2718=CARTESIAN_POINT('',(-38.9166666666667,20.,1330.));
#2719=CARTESIAN_POINT('',(-38.8333333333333,20.,1330.));
#2720=CARTESIAN_POINT('',(-38.6666666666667,20.,1330.));
#2721=CARTESIAN_POINT('',(-38.5833333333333,20.,1330.));
#2722=CARTESIAN_POINT('',(-38.4166666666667,20.,1330.));
#2723=CARTESIAN_POINT('',(-38.3333333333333,20.,1330.));
#2724=CARTESIAN_POINT('',(-38.1666666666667,20.,1330.));
#2725=CARTESIAN_POINT('',(-38.0833333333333,20.,1330.));
#2726=CARTESIAN_POINT('',(-37.9166666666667,20.,1330.));
#2727=CARTESIAN_POINT('',(-37.8333333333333,20.,1330.));
#2728=CARTESIAN_POINT('',(-37.6666666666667,20.,1330.));
#2729=CARTESIAN_POINT('',(-37.5833333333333,20.,1330.));
#2730=CARTESIAN_POINT('',(-37.4166666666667,20.,1330.));
#2731=CARTESIAN_POINT('',(-37.3333333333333,20.,1330.));
#2732=CARTESIAN_POINT('',(-37.1666666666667,20.,1330.));
#2733=CARTESIAN_POINT('',(-37.0833333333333,20.,1330.));
#2734=CARTESIAN_POINT('',(-36.9166666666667,20.,1330.));
#2735=CARTESIAN_POINT('',(-36.8333333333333,20.,1330.));
#2736=CARTESIAN_POINT('',(-36.6666666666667,20.,1330.));
#2737=CARTESIAN_POINT('',(-36.5833333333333,20.,1330.));
#2738=CARTESIAN_POINT('',(-36.4166666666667,20.,1330.));
#2739=CARTESIAN_POINT('',(-36.3333333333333,20.,1330.));
#2740=CARTESIAN_POINT('',(-36.1666666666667,20.,1330.));
#2741=CARTESIAN_POINT('',(-36.0833333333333,20.,1330.));
#2742=CARTESIAN_POINT('',(-35.9166666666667,20.,1330.));
#2743=CARTESIAN_POINT('',(-35.8333333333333,20.,1330.));
#2744=CARTESIAN_POINT('',(-35.6666666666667,20.,1330.));
#2745=CARTESIAN_POINT('',(-35.5833333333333,20.,1330.));
#2746=CARTESIAN_POINT('',(-35.4166666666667,20.,1330.));
#2747=CARTESIAN_POINT('',(-35.3333333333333,20.,1330.));
#2748=CARTESIAN_POINT('',(-35.1666666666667,20.,1330.));
#2749=CARTESIAN_POINT('',(-35.0833333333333,20.,1330.));
#2750=CARTESIAN_POINT('',(-34.9166666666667,20.,1330.));
#2751=CARTESIAN_POINT('',(-34.8333333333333,20.,1330.));
#2752=CARTESIAN_POINT('',(-34.6666666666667,20.,1330.));
#2753=CARTESIAN_POINT('',(-34.5833333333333,20.,1330.));
#2754=CARTESIAN_POINT('',(-34.4166666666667,20.,1330.));
#2755=CARTESIAN_POINT('',(-34.3333333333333,20.,1330.));
#2756=CARTESIAN_POINT('',(-34.1666666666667,20.,1330.));
#2757=CARTESIAN_POINT('',(-34.0833333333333,20.,1330.));
#2758=CARTESIAN_POINT('',(-33.9166666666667,20.,1330.));
#2759=CARTESIAN_POINT('',(-33.8333333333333,20.,1330.));
#2760=CARTESIAN_POINT('',(-33.6666666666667,20.,1330.));
#2761=CARTESIAN_POINT('',(-33.5833333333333,20.,1330.));
#2762=CARTESIAN_POINT('',(-33.4166666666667,20.,1330.));
#2763=CARTESIAN_POINT('',(-33.3333333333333,20.,1330.));
#2764=CARTESIAN_POINT('',(-33.1666666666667,20.,1330.));
#2765=CARTESIAN_POINT('',(-33.0833333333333,20.,1330.));
#2766=CARTESIAN_POINT('',(-32.9166666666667,20.,1330.));
#2767=CARTESIAN_POINT('',(-32.8333333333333,20.,1330.));
#2768=CARTESIAN_POINT('',(-32.6666666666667,20.,1330.));
#2769=CARTESIAN_POINT('',(-32.5833333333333,20.,1330.));
#2770=CARTESIAN_POINT('',(-32.4166666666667,20.,1330.));
#2771=CARTESIAN_POINT('',(-32.3333333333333,20.,1330.));
#2772=CARTESIAN_POINT('',(-32.1666666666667,20.,1330.));
#2773=CARTESIAN_POINT('',(-32.0833333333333,20.,1330.));
#2774=CARTESIAN_POINT('',(-32.,20.,1330.));
#2775=B_SPLINE_CURVE_WITH_KNOTS('',3,(#2709,#2710,#2711,#2712,#2713,#2714,#2715,#2716,#2717,
#2718,#2719,#2720,#2721,#2722,#2723,#2724,#2725,#2726,#2727,#2728,#2729,#2730,#2731,#2732,#2733,
#2734,#2735,#2736,#2737,#2738,#2739,#2740,#2741,#2742,#2743,#2744,#2745,#2746,#2747,#2748,#2749,
#2750,#2751,#2752,#2753,#2754,#2755,#2756,#2757,#2758,#2759,#2760,#2761,#2762,#2763,#2764,#2765,
#2766,#2767,#2768,#2769,#2770,#2771,#2772,#2773,#2774),.UNSPECIFIED.,.F.,.F.,(4,2,2,2,2,2,2,2,2,
2,2,2,2,2,2,2,2,2,2,2,2,2,2,2,2,2,2,2,2,2,2,2,4),(0.,0.25,0.5,0.750000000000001,1.,1.25,1.5,
1.75,2.,2.25,2.5,2.75,3.,3.25,3.5,3.75,4.,4.25,4.5,4.75,5.,5.25,5.50000000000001,
5.75000000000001,6.00000000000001,6.25000000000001,6.50000000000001,6.75000000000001,
7.00000000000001,7.25000000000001,7.50000000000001,7.75000000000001,8.00000000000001),.UNSPECIFIED.);
#2776=EDGE_CURVE('BSEAM352',#240,#1231,#2775,.T.);
#2777=ORIENTED_EDGE('',*,*,#241,.T.);
#2778=ORIENTED_EDGE('',*,*,#1232,.F.);
#2779=ORIENTED_EDGE('',*,*,#2776,.T.);
#2780=ORIENTED_EDGE('',*,*,#2776,.F.);
#2781=EDGE_LOOP('',(#2777,#2779,#2778,#2780));
#2782=FACE_BOUND('',#2781,.T.);
#2783=ADVANCED_FACE('F352',(#2782),#2708,.F.);
#2784=CARTESIAN_POINT('',(40.,45.,1410.));
#2785=DIRECTION('',(-1.,0.,0.));
#2786=DIRECTION('',(0.,-1.,0.));
#2787=AXIS2_PLACEMENT_3D('',#2784,#2785,#2786);
#2788=CYLINDRICAL_SURFACE('',#2787,25.);
#2789=CARTESIAN_POINT('',(-40.,20.,1410.));
#2790=CARTESIAN_POINT('',(-39.9166666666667,20.,1410.));
#2791=CARTESIAN_POINT('',(-39.8333333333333,20.,1410.));
#2792=CARTESIAN_POINT('',(-39.6666666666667,20.,1410.));
#2793=CARTESIAN_POINT('',(-39.5833333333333,20.,1410.));
#2794=CARTESIAN_POINT('',(-39.4166666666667,20.,1410.));
#2795=CARTESIAN_POINT('',(-39.3333333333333,20.,1410.));
#2796=CARTESIAN_POINT('',(-39.1666666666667,20.,1410.));
#2797=CARTESIAN_POINT('',(-39.0833333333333,20.,1410.));
#2798=CARTESIAN_POINT('',(-38.9166666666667,20.,1410.));
#2799=CARTESIAN_POINT('',(-38.8333333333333,20.,1410.));
#2800=CARTESIAN_POINT('',(-38.6666666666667,20.,1410.));
#2801=CARTESIAN_POINT('',(-38.5833333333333,20.,1410.));
#2802=CARTESIAN_POINT('',(-38.4166666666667,20.,1410.));
#2803=CARTESIAN_POINT('',(-38.3333333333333,20.,1410.));
#2804=CARTESIAN_POINT('',(-38.1666666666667,20.,1410.));
#2805=CARTESIAN_POINT('',(-38.0833333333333,20.,1410.));
#2806=CARTESIAN_POINT('',(-37.9166666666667,20.,1410.));
#2807=CARTESIAN_POINT('',(-37.8333333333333,20.,1410.));
#2808=CARTESIAN_POINT('',(-37.6666666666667,20.,1410.));
#2809=CARTESIAN_POINT('',(-37.5833333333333,20.,1410.));
#2810=CARTESIAN_POINT('',(-37.4166666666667,20.,1410.));
#2811=CARTESIAN_POINT('',(-37.3333333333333,20.,1410.));
#2812=CARTESIAN_POINT('',(-37.1666666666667,20.,1410.));
#2813=CARTESIAN_POINT('',(-37.0833333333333,20.,1410.));
#2814=CARTESIAN_POINT('',(-36.9166666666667,20.,1410.));
#2815=CARTESIAN_POINT('',(-36.8333333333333,20.,1410.));
#2816=CARTESIAN_POINT('',(-36.6666666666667,20.,1410.));
#2817=CARTESIAN_POINT('',(-36.5833333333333,20.,1410.));
#2818=CARTESIAN_POINT('',(-36.4166666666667,20.,1410.));
#2819=CARTESIAN_POINT('',(-36.3333333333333,20.,1410.));
#2820=CARTESIAN_POINT('',(-36.1666666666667,20.,1410.));
#2821=CARTESIAN_POINT('',(-36.0833333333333,20.,1410.));
#2822=CARTESIAN_POINT('',(-35.9166666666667,20.,1410.));
#2823=CARTESIAN_POINT('',(-35.8333333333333,20.,1410.));
#2824=CARTESIAN_POINT('',(-35.6666666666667,20.,1410.));
#2825=CARTESIAN_POINT('',(-35.5833333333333,20.,1410.));
#2826=CARTESIAN_POINT('',(-35.4166666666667,20.,1410.));
#2827=CARTESIAN_POINT('',(-35.3333333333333,20.,1410.));
#2828=CARTESIAN_POINT('',(-35.1666666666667,20.,1410.));
#2829=CARTESIAN_POINT('',(-35.0833333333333,20.,1410.));
#2830=CARTESIAN_POINT('',(-34.9166666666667,20.,1410.));
#2831=CARTESIAN_POINT('',(-34.8333333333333,20.,1410.));
#2832=CARTESIAN_POINT('',(-34.6666666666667,20.,1410.));
#2833=CARTESIAN_POINT('',(-34.5833333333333,20.,1410.));
#2834=CARTESIAN_POINT('',(-34.4166666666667,20.,1410.));
#2835=CARTESIAN_POINT('',(-34.3333333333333,20.,1410.));
#2836=CARTESIAN_POINT('',(-34.1666666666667,20.,1410.));
#2837=CARTESIAN_POINT('',(-34.0833333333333,20.,1410.));
#2838=CARTESIAN_POINT('',(-33.9166666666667,20.,1410.));
#2839=CARTESIAN_POINT('',(-33.8333333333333,20.,1410.));
#2840=CARTESIAN_POINT('',(-33.6666666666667,20.,1410.));
#2841=CARTESIAN_POINT('',(-33.5833333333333,20.,1410.));
#2842=CARTESIAN_POINT('',(-33.4166666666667,20.,1410.));
#2843=CARTESIAN_POINT('',(-33.3333333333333,20.,1410.));
#2844=CARTESIAN_POINT('',(-33.1666666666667,20.,1410.));
#2845=CARTESIAN_POINT('',(-33.0833333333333,20.,1410.));
#2846=CARTESIAN_POINT('',(-32.9166666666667,20.,1410.));
#2847=CARTESIAN_POINT('',(-32.8333333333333,20.,1410.));
#2848=CARTESIAN_POINT('',(-32.6666666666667,20.,1410.));
#2849=CARTESIAN_POINT('',(-32.5833333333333,20.,1410.));
#2850=CARTESIAN_POINT('',(-32.4166666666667,20.,1410.));
#2851=CARTESIAN_POINT('',(-32.3333333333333,20.,1410.));
#2852=CARTESIAN_POINT('',(-32.1666666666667,20.,1410.));
#2853=CARTESIAN_POINT('',(-32.0833333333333,20.,1410.));
#2854=CARTESIAN_POINT('',(-32.,20.,1410.));
#2855=B_SPLINE_CURVE_WITH_KNOTS('',3,(#2789,#2790,#2791,#2792,#2793,#2794,#2795,#2796,#2797,
#2798,#2799,#2800,#2801,#2802,#2803,#2804,#2805,#2806,#2807,#2808,#2809,#2810,#2811,#2812,#2813,
#2814,#2815,#2816,#2817,#2818,#2819,#2820,#2821,#2822,#2823,#2824,#2825,#2826,#2827,#2828,#2829,
#2830,#2831,#2832,#2833,#2834,#2835,#2836,#2837,#2838,#2839,#2840,#2841,#2842,#2843,#2844,#2845,
#2846,#2847,#2848,#2849,#2850,#2851,#2852,#2853,#2854),.UNSPECIFIED.,.F.,.F.,(4,2,2,2,2,2,2,2,2,
2,2,2,2,2,2,2,2,2,2,2,2,2,2,2,2,2,2,2,2,2,2,2,4),(0.,0.25,0.5,0.750000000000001,1.,1.25,1.5,
1.75,2.,2.25,2.5,2.75,3.,3.25,3.5,3.75,4.,4.25,4.5,4.75,5.,5.25,5.50000000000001,
5.75000000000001,6.00000000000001,6.25000000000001,6.50000000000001,6.75000000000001,
7.00000000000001,7.25000000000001,7.50000000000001,7.75000000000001,8.00000000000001),.UNSPECIFIED.);
#2856=EDGE_CURVE('BSEAM356',#251,#1242,#2855,.T.);
#2857=ORIENTED_EDGE('',*,*,#252,.T.);
#2858=ORIENTED_EDGE('',*,*,#1243,.F.);
#2859=ORIENTED_EDGE('',*,*,#2856,.T.);
#2860=ORIENTED_EDGE('',*,*,#2856,.F.);
#2861=EDGE_LOOP('',(#2857,#2859,#2858,#2860));
#2862=FACE_BOUND('',#2861,.T.);
#2863=ADVANCED_FACE('F356',(#2862),#2788,.F.);
#2864=CARTESIAN_POINT('',(40.,45.,1490.));
#2865=DIRECTION('',(-1.,0.,0.));
#2866=DIRECTION('',(0.,-1.,0.));
#2867=AXIS2_PLACEMENT_3D('',#2864,#2865,#2866);
#2868=CYLINDRICAL_SURFACE('',#2867,25.);
#2869=CARTESIAN_POINT('',(-40.,20.,1490.));
#2870=CARTESIAN_POINT('',(-39.9166666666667,20.,1490.));
#2871=CARTESIAN_POINT('',(-39.8333333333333,20.,1490.));
#2872=CARTESIAN_POINT('',(-39.6666666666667,20.,1490.));
#2873=CARTESIAN_POINT('',(-39.5833333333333,20.,1490.));
#2874=CARTESIAN_POINT('',(-39.4166666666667,20.,1490.));
#2875=CARTESIAN_POINT('',(-39.3333333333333,20.,1490.));
#2876=CARTESIAN_POINT('',(-39.1666666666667,20.,1490.));
#2877=CARTESIAN_POINT('',(-39.0833333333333,20.,1490.));
#2878=CARTESIAN_POINT('',(-38.9166666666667,20.,1490.));
#2879=CARTESIAN_POINT('',(-38.8333333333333,20.,1490.));
#2880=CARTESIAN_POINT('',(-38.6666666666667,20.,1490.));
#2881=CARTESIAN_POINT('',(-38.5833333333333,20.,1490.));
#2882=CARTESIAN_POINT('',(-38.4166666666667,20.,1490.));
#2883=CARTESIAN_POINT('',(-38.3333333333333,20.,1490.));
#2884=CARTESIAN_POINT('',(-38.1666666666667,20.,1490.));
#2885=CARTESIAN_POINT('',(-38.0833333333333,20.,1490.));
#2886=CARTESIAN_POINT('',(-37.9166666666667,20.,1490.));
#2887=CARTESIAN_POINT('',(-37.8333333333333,20.,1490.));
#2888=CARTESIAN_POINT('',(-37.6666666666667,20.,1490.));
#2889=CARTESIAN_POINT('',(-37.5833333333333,20.,1490.));
#2890=CARTESIAN_POINT('',(-37.4166666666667,20.,1490.));
#2891=CARTESIAN_POINT('',(-37.3333333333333,20.,1490.));
#2892=CARTESIAN_POINT('',(-37.1666666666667,20.,1490.));
#2893=CARTESIAN_POINT('',(-37.0833333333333,20.,1490.));
#2894=CARTESIAN_POINT('',(-36.9166666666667,20.,1490.));
#2895=CARTESIAN_POINT('',(-36.8333333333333,20.,1490.));
#2896=CARTESIAN_POINT('',(-36.6666666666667,20.,1490.));
#2897=CARTESIAN_POINT('',(-36.5833333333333,20.,1490.));
#2898=CARTESIAN_POINT('',(-36.4166666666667,20.,1490.));
#2899=CARTESIAN_POINT('',(-36.3333333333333,20.,1490.));
#2900=CARTESIAN_POINT('',(-36.1666666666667,20.,1490.));
#2901=CARTESIAN_POINT('',(-36.0833333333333,20.,1490.));
#2902=CARTESIAN_POINT('',(-35.9166666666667,20.,1490.));
#2903=CARTESIAN_POINT('',(-35.8333333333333,20.,1490.));
#2904=CARTESIAN_POINT('',(-35.6666666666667,20.,1490.));
#2905=CARTESIAN_POINT('',(-35.5833333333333,20.,1490.));
#2906=CARTESIAN_POINT('',(-35.4166666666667,20.,1490.));
#2907=CARTESIAN_POINT('',(-35.3333333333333,20.,1490.));
#2908=CARTESIAN_POINT('',(-35.1666666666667,20.,1490.));
#2909=CARTESIAN_POINT('',(-35.0833333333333,20.,1490.));
#2910=CARTESIAN_POINT('',(-34.9166666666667,20.,1490.));
#2911=CARTESIAN_POINT('',(-34.8333333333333,20.,1490.));
#2912=CARTESIAN_POINT('',(-34.6666666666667,20.,1490.));
#2913=CARTESIAN_POINT('',(-34.5833333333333,20.,1490.));
#2914=CARTESIAN_POINT('',(-34.4166666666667,20.,1490.));
#2915=CARTESIAN_POINT('',(-34.3333333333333,20.,1490.));
#2916=CARTESIAN_POINT('',(-34.1666666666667,20.,1490.));
#2917=CARTESIAN_POINT('',(-34.0833333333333,20.,1490.));
#2918=CARTESIAN_POINT('',(-33.9166666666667,20.,1490.));
#2919=CARTESIAN_POINT('',(-33.8333333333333,20.,1490.));
#2920=CARTESIAN_POINT('',(-33.6666666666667,20.,1490.));
#2921=CARTESIAN_POINT('',(-33.5833333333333,20.,1490.));
#2922=CARTESIAN_POINT('',(-33.4166666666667,20.,1490.));
#2923=CARTESIAN_POINT('',(-33.3333333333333,20.,1490.));
#2924=CARTESIAN_POINT('',(-33.1666666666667,20.,1490.));
#2925=CARTESIAN_POINT('',(-33.0833333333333,20.,1490.));
#2926=CARTESIAN_POINT('',(-32.9166666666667,20.,1490.));
#2927=CARTESIAN_POINT('',(-32.8333333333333,20.,1490.));
#2928=CARTESIAN_POINT('',(-32.6666666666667,20.,1490.));
#2929=CARTESIAN_POINT('',(-32.5833333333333,20.,1490.));
#2930=CARTESIAN_POINT('',(-32.4166666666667,20.,1490.));
#2931=CARTESIAN_POINT('',(-32.3333333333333,20.,1490.));
#2932=CARTESIAN_POINT('',(-32.1666666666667,20.,1490.));
#2933=CARTESIAN_POINT('',(-32.0833333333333,20.,1490.));
#2934=CARTESIAN_POINT('',(-32.,20.,1490.));
#2935=B_SPLINE_CURVE_WITH_KNOTS('',3,(#2869,#2870,#2871,#2872,#2873,#2874,#2875,#2876,#2877,
#2878,#2879,#2880,#2881,#2882,#2883,#2884,#2885,#2886,#2887,#2888,#2889,#2890,#2891,#2892,#2893,
#2894,#2895,#2896,#2897,#2898,#2899,#2900,#2901,#2902,#2903,#2904,#2905,#2906,#2907,#2908,#2909,
#2910,#2911,#2912,#2913,#2914,#2915,#2916,#2917,#2918,#2919,#2920,#2921,#2922,#2923,#2924,#2925,
#2926,#2927,#2928,#2929,#2930,#2931,#2932,#2933,#2934),.UNSPECIFIED.,.F.,.F.,(4,2,2,2,2,2,2,2,2,
2,2,2,2,2,2,2,2,2,2,2,2,2,2,2,2,2,2,2,2,2,2,2,4),(0.,0.25,0.5,0.750000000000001,1.,1.25,1.5,
1.75,2.,2.25,2.5,2.75,3.,3.25,3.5,3.75,4.,4.25,4.5,4.75,5.,5.25,5.50000000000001,
5.75000000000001,6.00000000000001,6.25000000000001,6.50000000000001,6.75000000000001,
7.00000000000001,7.25000000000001,7.50000000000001,7.75000000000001,8.00000000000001),.UNSPECIFIED.);
#2936=EDGE_CURVE('BSEAM360',#262,#1253,#2935,.T.);
#2937=ORIENTED_EDGE('',*,*,#263,.T.);
#2938=ORIENTED_EDGE('',*,*,#1254,.F.);
#2939=ORIENTED_EDGE('',*,*,#2936,.T.);
#2940=ORIENTED_EDGE('',*,*,#2936,.F.);
#2941=EDGE_LOOP('',(#2937,#2939,#2938,#2940));
#2942=FACE_BOUND('',#2941,.T.);
#2943=ADVANCED_FACE('F360',(#2942),#2868,.F.);
#2944=CARTESIAN_POINT('',(40.,45.,1570.));
#2945=DIRECTION('',(-1.,0.,0.));
#2946=DIRECTION('',(0.,-1.,0.));
#2947=AXIS2_PLACEMENT_3D('',#2944,#2945,#2946);
#2948=CYLINDRICAL_SURFACE('',#2947,25.);
#2949=CARTESIAN_POINT('',(-40.,20.,1570.));
#2950=CARTESIAN_POINT('',(-39.9166666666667,20.,1570.));
#2951=CARTESIAN_POINT('',(-39.8333333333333,20.,1570.));
#2952=CARTESIAN_POINT('',(-39.6666666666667,20.,1570.));
#2953=CARTESIAN_POINT('',(-39.5833333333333,20.,1570.));
#2954=CARTESIAN_POINT('',(-39.4166666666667,20.,1570.));
#2955=CARTESIAN_POINT('',(-39.3333333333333,20.,1570.));
#2956=CARTESIAN_POINT('',(-39.1666666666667,20.,1570.));
#2957=CARTESIAN_POINT('',(-39.0833333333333,20.,1570.));
#2958=CARTESIAN_POINT('',(-38.9166666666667,20.,1570.));
#2959=CARTESIAN_POINT('',(-38.8333333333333,20.,1570.));
#2960=CARTESIAN_POINT('',(-38.6666666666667,20.,1570.));
#2961=CARTESIAN_POINT('',(-38.5833333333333,20.,1570.));
#2962=CARTESIAN_POINT('',(-38.4166666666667,20.,1570.));
#2963=CARTESIAN_POINT('',(-38.3333333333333,20.,1570.));
#2964=CARTESIAN_POINT('',(-38.1666666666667,20.,1570.));
#2965=CARTESIAN_POINT('',(-38.0833333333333,20.,1570.));
#2966=CARTESIAN_POINT('',(-37.9166666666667,20.,1570.));
#2967=CARTESIAN_POINT('',(-37.8333333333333,20.,1570.));
#2968=CARTESIAN_POINT('',(-37.6666666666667,20.,1570.));
#2969=CARTESIAN_POINT('',(-37.5833333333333,20.,1570.));
#2970=CARTESIAN_POINT('',(-37.4166666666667,20.,1570.));
#2971=CARTESIAN_POINT('',(-37.3333333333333,20.,1570.));
#2972=CARTESIAN_POINT('',(-37.1666666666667,20.,1570.));
#2973=CARTESIAN_POINT('',(-37.0833333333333,20.,1570.));
#2974=CARTESIAN_POINT('',(-36.9166666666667,20.,1570.));
#2975=CARTESIAN_POINT('',(-36.8333333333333,20.,1570.));
#2976=CARTESIAN_POINT('',(-36.6666666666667,20.,1570.));
#2977=CARTESIAN_POINT('',(-36.5833333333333,20.,1570.));
#2978=CARTESIAN_POINT('',(-36.4166666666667,20.,1570.));
#2979=CARTESIAN_POINT('',(-36.3333333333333,20.,1570.));
#2980=CARTESIAN_POINT('',(-36.1666666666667,20.,1570.));
#2981=CARTESIAN_POINT('',(-36.0833333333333,20.,1570.));
#2982=CARTESIAN_POINT('',(-35.9166666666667,20.,1570.));
#2983=CARTESIAN_POINT('',(-35.8333333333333,20.,1570.));
#2984=CARTESIAN_POINT('',(-35.6666666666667,20.,1570.));
#2985=CARTESIAN_POINT('',(-35.5833333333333,20.,1570.));
#2986=CARTESIAN_POINT('',(-35.4166666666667,20.,1570.));
#2987=CARTESIAN_POINT('',(-35.3333333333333,20.,1570.));
#2988=CARTESIAN_POINT('',(-35.1666666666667,20.,1570.));
#2989=CARTESIAN_POINT('',(-35.0833333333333,20.,1570.));
#2990=CARTESIAN_POINT('',(-34.9166666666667,20.,1570.));
#2991=CARTESIAN_POINT('',(-34.8333333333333,20.,1570.));
#2992=CARTESIAN_POINT('',(-34.6666666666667,20.,1570.));
#2993=CARTESIAN_POINT('',(-34.5833333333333,20.,1570.));
#2994=CARTESIAN_POINT('',(-34.4166666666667,20.,1570.));
#2995=CARTESIAN_POINT('',(-34.3333333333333,20.,1570.));
#2996=CARTESIAN_POINT('',(-34.1666666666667,20.,1570.));
#2997=CARTESIAN_POINT('',(-34.0833333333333,20.,1570.));
#2998=CARTESIAN_POINT('',(-33.9166666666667,20.,1570.));
#2999=CARTESIAN_POINT('',(-33.8333333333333,20.,1570.));
#3000=CARTESIAN_POINT('',(-33.6666666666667,20.,1570.));
#3001=CARTESIAN_POINT('',(-33.5833333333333,20.,1570.));
#3002=CARTESIAN_POINT('',(-33.4166666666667,20.,1570.));
#3003=CARTESIAN_POINT('',(-33.3333333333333,20.,1570.));
#3004=CARTESIAN_POINT('',(-33.1666666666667,20.,1570.));
#3005=CARTESIAN_POINT('',(-33.0833333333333,20.,1570.));
#3006=CARTESIAN_POINT('',(-32.9166666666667,20.,1570.));
#3007=CARTESIAN_POINT('',(-32.8333333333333,20.,1570.));
#3008=CARTESIAN_POINT('',(-32.6666666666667,20.,1570.));
#3009=CARTESIAN_POINT('',(-32.5833333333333,20.,1570.));
#3010=CARTESIAN_POINT('',(-32.4166666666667,20.,1570.));
#3011=CARTESIAN_POINT('',(-32.3333333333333,20.,1570.));
#3012=CARTESIAN_POINT('',(-32.1666666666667,20.,1570.));
#3013=CARTESIAN_POINT('',(-32.0833333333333,20.,1570.));
#3014=CARTESIAN_POINT('',(-32.,20.,1570.));
#3015=B_SPLINE_CURVE_WITH_KNOTS('',3,(#2949,#2950,#2951,#2952,#2953,#2954,#2955,#2956,#2957,
#2958,#2959,#2960,#2961,#2962,#2963,#2964,#2965,#2966,#2967,#2968,#2969,#2970,#2971,#2972,#2973,
#2974,#2975,#2976,#2977,#2978,#2979,#2980,#2981,#2982,#2983,#2984,#2985,#2986,#2987,#2988,#2989,
#2990,#2991,#2992,#2993,#2994,#2995,#2996,#2997,#2998,#2999,#3000,#3001,#3002,#3003,#3004,#3005,
#3006,#3007,#3008,#3009,#3010,#3011,#3012,#3013,#3014),.UNSPECIFIED.,.F.,.F.,(4,2,2,2,2,2,2,2,2,
2,2,2,2,2,2,2,2,2,2,2,2,2,2,2,2,2,2,2,2,2,2,2,4),(0.,0.25,0.5,0.750000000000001,1.,1.25,1.5,
1.75,2.,2.25,2.5,2.75,3.,3.25,3.5,3.75,4.,4.25,4.5,4.75,5.,5.25,5.50000000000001,
5.75000000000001,6.00000000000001,6.25000000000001,6.50000000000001,6.75000000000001,
7.00000000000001,7.25000000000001,7.50000000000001,7.75000000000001,8.00000000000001),.UNSPECIFIED.);
#3016=EDGE_CURVE('BSEAM364',#273,#1264,#3015,.T.);
#3017=ORIENTED_EDGE('',*,*,#274,.T.);
#3018=ORIENTED_EDGE('',*,*,#1265,.F.);
#3019=ORIENTED_EDGE('',*,*,#3016,.T.);
#3020=ORIENTED_EDGE('',*,*,#3016,.F.);
#3021=EDGE_LOOP('',(#3017,#3019,#3018,#3020));
#3022=FACE_BOUND('',#3021,.T.);
#3023=ADVANCED_FACE('F364',(#3022),#2948,.F.);
#3024=CARTESIAN_POINT('',(40.,45.,1650.));
#3025=DIRECTION('',(-1.,0.,0.));
#3026=DIRECTION('',(0.,-1.,0.));
#3027=AXIS2_PLACEMENT_3D('',#3024,#3025,#3026);
#3028=CYLINDRICAL_SURFACE('',#3027,25.);
#3029=CARTESIAN_POINT('',(-40.,20.,1650.));
#3030=CARTESIAN_POINT('',(-39.9166666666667,20.,1650.));
#3031=CARTESIAN_POINT('',(-39.8333333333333,20.,1650.));
#3032=CARTESIAN_POINT('',(-39.6666666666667,20.,1650.));
#3033=CARTESIAN_POINT('',(-39.5833333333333,20.,1650.));
#3034=CARTESIAN_POINT('',(-39.4166666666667,20.,1650.));
#3035=CARTESIAN_POINT('',(-39.3333333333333,20.,1650.));
#3036=CARTESIAN_POINT('',(-39.1666666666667,20.,1650.));
#3037=CARTESIAN_POINT('',(-39.0833333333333,20.,1650.));
#3038=CARTESIAN_POINT('',(-38.9166666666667,20.,1650.));
#3039=CARTESIAN_POINT('',(-38.8333333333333,20.,1650.));
#3040=CARTESIAN_POINT('',(-38.6666666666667,20.,1650.));
#3041=CARTESIAN_POINT('',(-38.5833333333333,20.,1650.));
#3042=CARTESIAN_POINT('',(-38.4166666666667,20.,1650.));
#3043=CARTESIAN_POINT('',(-38.3333333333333,20.,1650.));
#3044=CARTESIAN_POINT('',(-38.1666666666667,20.,1650.));
#3045=CARTESIAN_POINT('',(-38.0833333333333,20.,1650.));
#3046=CARTESIAN_POINT('',(-37.9166666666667,20.,1650.));
#3047=CARTESIAN_POINT('',(-37.8333333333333,20.,1650.));
#3048=CARTESIAN_POINT('',(-37.6666666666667,20.,1650.));
#3049=CARTESIAN_POINT('',(-37.5833333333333,20.,1650.));
#3050=CARTESIAN_POINT('',(-37.4166666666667,20.,1650.));
#3051=CARTESIAN_POINT('',(-37.3333333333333,20.,1650.));
#3052=CARTESIAN_POINT('',(-37.1666666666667,20.,1650.));
#3053=CARTESIAN_POINT('',(-37.0833333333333,20.,1650.));
#3054=CARTESIAN_POINT('',(-36.9166666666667,20.,1650.));
#3055=CARTESIAN_POINT('',(-36.8333333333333,20.,1650.));
#3056=CARTESIAN_POINT('',(-36.6666666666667,20.,1650.));
#3057=CARTESIAN_POINT('',(-36.5833333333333,20.,1650.));
#3058=CARTESIAN_POINT('',(-36.4166666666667,20.,1650.));
#3059=CARTESIAN_POINT('',(-36.3333333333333,20.,1650.));
#3060=CARTESIAN_POINT('',(-36.1666666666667,20.,1650.));
#3061=CARTESIAN_POINT('',(-36.0833333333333,20.,1650.));
#3062=CARTESIAN_POINT('',(-35.9166666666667,20.,1650.));
#3063=CARTESIAN_POINT('',(-35.8333333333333,20.,1650.));
#3064=CARTESIAN_POINT('',(-35.6666666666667,20.,1650.));
#3065=CARTESIAN_POINT('',(-35.5833333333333,20.,1650.));
#3066=CARTESIAN_POINT('',(-35.4166666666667,20.,1650.));
#3067=CARTESIAN_POINT('',(-35.3333333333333,20.,1650.));
#3068=CARTESIAN_POINT('',(-35.1666666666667,20.,1650.));
#3069=CARTESIAN_POINT('',(-35.0833333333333,20.,1650.));
#3070=CARTESIAN_POINT('',(-34.9166666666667,20.,1650.));
#3071=CARTESIAN_POINT('',(-34.8333333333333,20.,1650.));
#3072=CARTESIAN_POINT('',(-34.6666666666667,20.,1650.));
#3073=CARTESIAN_POINT('',(-34.5833333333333,20.,1650.));
#3074=CARTESIAN_POINT('',(-34.4166666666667,20.,1650.));
#3075=CARTESIAN_POINT('',(-34.3333333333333,20.,1650.));
#3076=CARTESIAN_POINT('',(-34.1666666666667,20.,1650.));
#3077=CARTESIAN_POINT('',(-34.0833333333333,20.,1650.));
#3078=CARTESIAN_POINT('',(-33.9166666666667,20.,1650.));
#3079=CARTESIAN_POINT('',(-33.8333333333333,20.,1650.));
#3080=CARTESIAN_POINT('',(-33.6666666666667,20.,1650.));
#3081=CARTESIAN_POINT('',(-33.5833333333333,20.,1650.));
#3082=CARTESIAN_POINT('',(-33.4166666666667,20.,1650.));
#3083=CARTESIAN_POINT('',(-33.3333333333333,20.,1650.));
#3084=CARTESIAN_POINT('',(-33.1666666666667,20.,1650.));
#3085=CARTESIAN_POINT('',(-33.0833333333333,20.,1650.));
#3086=CARTESIAN_POINT('',(-32.9166666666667,20.,1650.));
#3087=CARTESIAN_POINT('',(-32.8333333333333,20.,1650.));
#3088=CARTESIAN_POINT('',(-32.6666666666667,20.,1650.));
#3089=CARTESIAN_POINT('',(-32.5833333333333,20.,1650.));
#3090=CARTESIAN_POINT('',(-32.4166666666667,20.,1650.));
#3091=CARTESIAN_POINT('',(-32.3333333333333,20.,1650.));
#3092=CARTESIAN_POINT('',(-32.1666666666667,20.,1650.));
#3093=CARTESIAN_POINT('',(-32.0833333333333,20.,1650.));
#3094=CARTESIAN_POINT('',(-32.,20.,1650.));
#3095=B_SPLINE_CURVE_WITH_KNOTS('',3,(#3029,#3030,#3031,#3032,#3033,#3034,#3035,#3036,#3037,
#3038,#3039,#3040,#3041,#3042,#3043,#3044,#3045,#3046,#3047,#3048,#3049,#3050,#3051,#3052,#3053,
#3054,#3055,#3056,#3057,#3058,#3059,#3060,#3061,#3062,#3063,#3064,#3065,#3066,#3067,#3068,#3069,
#3070,#3071,#3072,#3073,#3074,#3075,#3076,#3077,#3078,#3079,#3080,#3081,#3082,#3083,#3084,#3085,
#3086,#3087,#3088,#3089,#3090,#3091,#3092,#3093,#3094),.UNSPECIFIED.,.F.,.F.,(4,2,2,2,2,2,2,2,2,
2,2,2,2,2,2,2,2,2,2,2,2,2,2,2,2,2,2,2,2,2,2,2,4),(0.,0.25,0.5,0.750000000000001,1.,1.25,1.5,
1.75,2.,2.25,2.5,2.75,3.,3.25,3.5,3.75,4.,4.25,4.5,4.75,5.,5.25,5.50000000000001,
5.75000000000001,6.00000000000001,6.25000000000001,6.50000000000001,6.75000000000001,
7.00000000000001,7.25000000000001,7.50000000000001,7.75000000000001,8.00000000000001),.UNSPECIFIED.);
#3096=EDGE_CURVE('BSEAM368',#284,#1275,#3095,.T.);
#3097=ORIENTED_EDGE('',*,*,#285,.T.);
#3098=ORIENTED_EDGE('',*,*,#1276,.F.);
#3099=ORIENTED_EDGE('',*,*,#3096,.T.);
#3100=ORIENTED_EDGE('',*,*,#3096,.F.);
#3101=EDGE_LOOP('',(#3097,#3099,#3098,#3100));
#3102=FACE_BOUND('',#3101,.T.);
#3103=ADVANCED_FACE('F368',(#3102),#3028,.F.);
#3104=CARTESIAN_POINT('',(40.,45.,1730.));
#3105=DIRECTION('',(-1.,0.,0.));
#3106=DIRECTION('',(0.,-1.,0.));
#3107=AXIS2_PLACEMENT_3D('',#3104,#3105,#3106);
#3108=CYLINDRICAL_SURFACE('',#3107,25.);
#3109=CARTESIAN_POINT('',(-40.,20.,1730.));
#3110=CARTESIAN_POINT('',(-39.9166666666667,20.,1730.));
#3111=CARTESIAN_POINT('',(-39.8333333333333,20.,1730.));
#3112=CARTESIAN_POINT('',(-39.6666666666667,20.,1730.));
#3113=CARTESIAN_POINT('',(-39.5833333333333,20.,1730.));
#3114=CARTESIAN_POINT('',(-39.4166666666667,20.,1730.));
#3115=CARTESIAN_POINT('',(-39.3333333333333,20.,1730.));
#3116=CARTESIAN_POINT('',(-39.1666666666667,20.,1730.));
#3117=CARTESIAN_POINT('',(-39.0833333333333,20.,1730.));
#3118=CARTESIAN_POINT('',(-38.9166666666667,20.,1730.));
#3119=CARTESIAN_POINT('',(-38.8333333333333,20.,1730.));
#3120=CARTESIAN_POINT('',(-38.6666666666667,20.,1730.));
#3121=CARTESIAN_POINT('',(-38.5833333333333,20.,1730.));
#3122=CARTESIAN_POINT('',(-38.4166666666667,20.,1730.));
#3123=CARTESIAN_POINT('',(-38.3333333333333,20.,1730.));
#3124=CARTESIAN_POINT('',(-38.1666666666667,20.,1730.));
#3125=CARTESIAN_POINT('',(-38.0833333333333,20.,1730.));
#3126=CARTESIAN_POINT('',(-37.9166666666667,20.,1730.));
#3127=CARTESIAN_POINT('',(-37.8333333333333,20.,1730.));
#3128=CARTESIAN_POINT('',(-37.6666666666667,20.,1730.));
#3129=CARTESIAN_POINT('',(-37.5833333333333,20.,1730.));
#3130=CARTESIAN_POINT('',(-37.4166666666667,20.,1730.));
#3131=CARTESIAN_POINT('',(-37.3333333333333,20.,1730.));
#3132=CARTESIAN_POINT('',(-37.1666666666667,20.,1730.));
#3133=CARTESIAN_POINT('',(-37.0833333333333,20.,1730.));
#3134=CARTESIAN_POINT('',(-36.9166666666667,20.,1730.));
#3135=CARTESIAN_POINT('',(-36.8333333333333,20.,1730.));
#3136=CARTESIAN_POINT('',(-36.6666666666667,20.,1730.));
#3137=CARTESIAN_POINT('',(-36.5833333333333,20.,1730.));
#3138=CARTESIAN_POINT('',(-36.4166666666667,20.,1730.));
#3139=CARTESIAN_POINT('',(-36.3333333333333,20.,1730.));
#3140=CARTESIAN_POINT('',(-36.1666666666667,20.,1730.));
#3141=CARTESIAN_POINT('',(-36.0833333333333,20.,1730.));
#3142=CARTESIAN_POINT('',(-35.9166666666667,20.,1730.));
#3143=CARTESIAN_POINT('',(-35.8333333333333,20.,1730.));
#3144=CARTESIAN_POINT('',(-35.6666666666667,20.,1730.));
#3145=CARTESIAN_POINT('',(-35.5833333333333,20.,1730.));
#3146=CARTESIAN_POINT('',(-35.4166666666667,20.,1730.));
#3147=CARTESIAN_POINT('',(-35.3333333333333,20.,1730.));
#3148=CARTESIAN_POINT('',(-35.1666666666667,20.,1730.));
#3149=CARTESIAN_POINT('',(-35.0833333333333,20.,1730.));
#3150=CARTESIAN_POINT('',(-34.9166666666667,20.,1730.));
#3151=CARTESIAN_POINT('',(-34.8333333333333,20.,1730.));
#3152=CARTESIAN_POINT('',(-34.6666666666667,20.,1730.));
#3153=CARTESIAN_POINT('',(-34.5833333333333,20.,1730.));
#3154=CARTESIAN_POINT('',(-34.4166666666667,20.,1730.));
#3155=CARTESIAN_POINT('',(-34.3333333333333,20.,1730.));
#3156=CARTESIAN_POINT('',(-34.1666666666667,20.,1730.));
#3157=CARTESIAN_POINT('',(-34.0833333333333,20.,1730.));
#3158=CARTESIAN_POINT('',(-33.9166666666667,20.,1730.));
#3159=CARTESIAN_POINT('',(-33.8333333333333,20.,1730.));
#3160=CARTESIAN_POINT('',(-33.6666666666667,20.,1730.));
#3161=CARTESIAN_POINT('',(-33.5833333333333,20.,1730.));
#3162=CARTESIAN_POINT('',(-33.4166666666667,20.,1730.));
#3163=CARTESIAN_POINT('',(-33.3333333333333,20.,1730.));
#3164=CARTESIAN_POINT('',(-33.1666666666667,20.,1730.));
#3165=CARTESIAN_POINT('',(-33.0833333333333,20.,1730.));
#3166=CARTESIAN_POINT('',(-32.9166666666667,20.,1730.));
#3167=CARTESIAN_POINT('',(-32.8333333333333,20.,1730.));
#3168=CARTESIAN_POINT('',(-32.6666666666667,20.,1730.));
#3169=CARTESIAN_POINT('',(-32.5833333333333,20.,1730.));
#3170=CARTESIAN_POINT('',(-32.4166666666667,20.,1730.));
#3171=CARTESIAN_POINT('',(-32.3333333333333,20.,1730.));
#3172=CARTESIAN_POINT('',(-32.1666666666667,20.,1730.));
#3173=CARTESIAN_POINT('',(-32.0833333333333,20.,1730.));
#3174=CARTESIAN_POINT('',(-32.,20.,1730.));
#3175=B_SPLINE_CURVE_WITH_KNOTS('',3,(#3109,#3110,#3111,#3112,#3113,#3114,#3115,#3116,#3117,
#3118,#3119,#3120,#3121,#3122,#3123,#3124,#3125,#3126,#3127,#3128,#3129,#3130,#3131,#3132,#3133,
#3134,#3135,#3136,#3137,#3138,#3139,#3140,#3141,#3142,#3143,#3144,#3145,#3146,#3147,#3148,#3149,
#3150,#3151,#3152,#3153,#3154,#3155,#3156,#3157,#3158,#3159,#3160,#3161,#3162,#3163,#3164,#3165,
#3166,#3167,#3168,#3169,#3170,#3171,#3172,#3173,#3174),.UNSPECIFIED.,.F.,.F.,(4,2,2,2,2,2,2,2,2,
2,2,2,2,2,2,2,2,2,2,2,2,2,2,2,2,2,2,2,2,2,2,2,4),(0.,0.25,0.5,0.750000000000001,1.,1.25,1.5,
1.75,2.,2.25,2.5,2.75,3.,3.25,3.5,3.75,4.,4.25,4.5,4.75,5.,5.25,5.50000000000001,
5.75000000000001,6.00000000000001,6.25000000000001,6.50000000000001,6.75000000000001,
7.00000000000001,7.25000000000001,7.50000000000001,7.75000000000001,8.00000000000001),.UNSPECIFIED.);
#3176=EDGE_CURVE('BSEAM372',#295,#1286,#3175,.T.);
#3177=ORIENTED_EDGE('',*,*,#296,.T.);
#3178=ORIENTED_EDGE('',*,*,#1287,.F.);
#3179=ORIENTED_EDGE('',*,*,#3176,.T.);
#3180=ORIENTED_EDGE('',*,*,#3176,.F.);
#3181=EDGE_LOOP('',(#3177,#3179,#3178,#3180));
#3182=FACE_BOUND('',#3181,.T.);
#3183=ADVANCED_FACE('F372',(#3182),#3108,.F.);
#3184=CARTESIAN_POINT('',(40.,45.,1810.));
#3185=DIRECTION('',(-1.,0.,0.));
#3186=DIRECTION('',(0.,-1.,0.));
#3187=AXIS2_PLACEMENT_3D('',#3184,#3185,#3186);
#3188=CYLINDRICAL_SURFACE('',#3187,25.);
#3189=CARTESIAN_POINT('',(-40.,20.,1810.));
#3190=CARTESIAN_POINT('',(-39.9166666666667,20.,1810.));
#3191=CARTESIAN_POINT('',(-39.8333333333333,20.,1810.));
#3192=CARTESIAN_POINT('',(-39.6666666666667,20.,1810.));
#3193=CARTESIAN_POINT('',(-39.5833333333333,20.,1810.));
#3194=CARTESIAN_POINT('',(-39.4166666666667,20.,1810.));
#3195=CARTESIAN_POINT('',(-39.3333333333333,20.,1810.));
#3196=CARTESIAN_POINT('',(-39.1666666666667,20.,1810.));
#3197=CARTESIAN_POINT('',(-39.0833333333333,20.,1810.));
#3198=CARTESIAN_POINT('',(-38.9166666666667,20.,1810.));
#3199=CARTESIAN_POINT('',(-38.8333333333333,20.,1810.));
#3200=CARTESIAN_POINT('',(-38.6666666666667,20.,1810.));
#3201=CARTESIAN_POINT('',(-38.5833333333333,20.,1810.));
#3202=CARTESIAN_POINT('',(-38.4166666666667,20.,1810.));
#3203=CARTESIAN_POINT('',(-38.3333333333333,20.,1810.));
#3204=CARTESIAN_POINT('',(-38.1666666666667,20.,1810.));
#3205=CARTESIAN_POINT('',(-38.0833333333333,20.,1810.));
#3206=CARTESIAN_POINT('',(-37.9166666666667,20.,1810.));
#3207=CARTESIAN_POINT('',(-37.8333333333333,20.,1810.));
#3208=CARTESIAN_POINT('',(-37.6666666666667,20.,1810.));
#3209=CARTESIAN_POINT('',(-37.5833333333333,20.,1810.));
#3210=CARTESIAN_POINT('',(-37.4166666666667,20.,1810.));
#3211=CARTESIAN_POINT('',(-37.3333333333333,20.,1810.));
#3212=CARTESIAN_POINT('',(-37.1666666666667,20.,1810.));
#3213=CARTESIAN_POINT('',(-37.0833333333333,20.,1810.));
#3214=CARTESIAN_POINT('',(-36.9166666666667,20.,1810.));
#3215=CARTESIAN_POINT('',(-36.8333333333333,20.,1810.));
#3216=CARTESIAN_POINT('',(-36.6666666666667,20.,1810.));
#3217=CARTESIAN_POINT('',(-36.5833333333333,20.,1810.));
#3218=CARTESIAN_POINT('',(-36.4166666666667,20.,1810.));
#3219=CARTESIAN_POINT('',(-36.3333333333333,20.,1810.));
#3220=CARTESIAN_POINT('',(-36.1666666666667,20.,1810.));
#3221=CARTESIAN_POINT('',(-36.0833333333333,20.,1810.));
#3222=CARTESIAN_POINT('',(-35.9166666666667,20.,1810.));
#3223=CARTESIAN_POINT('',(-35.8333333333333,20.,1810.));
#3224=CARTESIAN_POINT('',(-35.6666666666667,20.,1810.));
#3225=CARTESIAN_POINT('',(-35.5833333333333,20.,1810.));
#3226=CARTESIAN_POINT('',(-35.4166666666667,20.,1810.));
#3227=CARTESIAN_POINT('',(-35.3333333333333,20.,1810.));
#3228=CARTESIAN_POINT('',(-35.1666666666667,20.,1810.));
#3229=CARTESIAN_POINT('',(-35.0833333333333,20.,1810.));
#3230=CARTESIAN_POINT('',(-34.9166666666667,20.,1810.));
#3231=CARTESIAN_POINT('',(-34.8333333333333,20.,1810.));
#3232=CARTESIAN_POINT('',(-34.6666666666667,20.,1810.));
#3233=CARTESIAN_POINT('',(-34.5833333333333,20.,1810.));
#3234=CARTESIAN_POINT('',(-34.4166666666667,20.,1810.));
#3235=CARTESIAN_POINT('',(-34.3333333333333,20.,1810.));
#3236=CARTESIAN_POINT('',(-34.1666666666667,20.,1810.));
#3237=CARTESIAN_POINT('',(-34.0833333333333,20.,1810.));
#3238=CARTESIAN_POINT('',(-33.9166666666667,20.,1810.));
#3239=CARTESIAN_POINT('',(-33.8333333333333,20.,1810.));
#3240=CARTESIAN_POINT('',(-33.6666666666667,20.,1810.));
#3241=CARTESIAN_POINT('',(-33.5833333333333,20.,1810.));
#3242=CARTESIAN_POINT('',(-33.4166666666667,20.,1810.));
#3243=CARTESIAN_POINT('',(-33.3333333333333,20.,1810.));
#3244=CARTESIAN_POINT('',(-33.1666666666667,20.,1810.));
#3245=CARTESIAN_POINT('',(-33.0833333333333,20.,1810.));
#3246=CARTESIAN_POINT('',(-32.9166666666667,20.,1810.));
#3247=CARTESIAN_POINT('',(-32.8333333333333,20.,1810.));
#3248=CARTESIAN_POINT('',(-32.6666666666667,20.,1810.));
#3249=CARTESIAN_POINT('',(-32.5833333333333,20.,1810.));
#3250=CARTESIAN_POINT('',(-32.4166666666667,20.,1810.));
#3251=CARTESIAN_POINT('',(-32.3333333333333,20.,1810.));
#3252=CARTESIAN_POINT('',(-32.1666666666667,20.,1810.));
#3253=CARTESIAN_POINT('',(-32.0833333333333,20.,1810.));
#3254=CARTESIAN_POINT('',(-32.,20.,1810.));
#3255=B_SPLINE_CURVE_WITH_KNOTS('',3,(#3189,#3190,#3191,#3192,#3193,#3194,#3195,#3196,#3197,
#3198,#3199,#3200,#3201,#3202,#3203,#3204,#3205,#3206,#3207,#3208,#3209,#3210,#3211,#3212,#3213,
#3214,#3215,#3216,#3217,#3218,#3219,#3220,#3221,#3222,#3223,#3224,#3225,#3226,#3227,#3228,#3229,
#3230,#3231,#3232,#3233,#3234,#3235,#3236,#3237,#3238,#3239,#3240,#3241,#3242,#3243,#3244,#3245,
#3246,#3247,#3248,#3249,#3250,#3251,#3252,#3253,#3254),.UNSPECIFIED.,.F.,.F.,(4,2,2,2,2,2,2,2,2,
2,2,2,2,2,2,2,2,2,2,2,2,2,2,2,2,2,2,2,2,2,2,2,4),(0.,0.25,0.5,0.750000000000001,1.,1.25,1.5,
1.75,2.,2.25,2.5,2.75,3.,3.25,3.5,3.75,4.,4.25,4.5,4.75,5.,5.25,5.50000000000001,
5.75000000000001,6.00000000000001,6.25000000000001,6.50000000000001,6.75000000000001,
7.00000000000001,7.25000000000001,7.50000000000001,7.75000000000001,8.00000000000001),.UNSPECIFIED.);
#3256=EDGE_CURVE('BSEAM376',#306,#1297,#3255,.T.);
#3257=ORIENTED_EDGE('',*,*,#307,.T.);
#3258=ORIENTED_EDGE('',*,*,#1298,.F.);
#3259=ORIENTED_EDGE('',*,*,#3256,.T.);
#3260=ORIENTED_EDGE('',*,*,#3256,.F.);
#3261=EDGE_LOOP('',(#3257,#3259,#3258,#3260));
#3262=FACE_BOUND('',#3261,.T.);
#3263=ADVANCED_FACE('F376',(#3262),#3188,.F.);
#3264=CARTESIAN_POINT('',(40.,45.,1890.));
#3265=DIRECTION('',(-1.,0.,0.));
#3266=DIRECTION('',(0.,-1.,0.));
#3267=AXIS2_PLACEMENT_3D('',#3264,#3265,#3266);
#3268=CYLINDRICAL_SURFACE('',#3267,25.);
#3269=CARTESIAN_POINT('',(-40.,20.,1890.));
#3270=CARTESIAN_POINT('',(-39.9166666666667,20.,1890.));
#3271=CARTESIAN_POINT('',(-39.8333333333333,20.,1890.));
#3272=CARTESIAN_POINT('',(-39.6666666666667,20.,1890.));
#3273=CARTESIAN_POINT('',(-39.5833333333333,20.,1890.));
#3274=CARTESIAN_POINT('',(-39.4166666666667,20.,1890.));
#3275=CARTESIAN_POINT('',(-39.3333333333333,20.,1890.));
#3276=CARTESIAN_POINT('',(-39.1666666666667,20.,1890.));
#3277=CARTESIAN_POINT('',(-39.0833333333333,20.,1890.));
#3278=CARTESIAN_POINT('',(-38.9166666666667,20.,1890.));
#3279=CARTESIAN_POINT('',(-38.8333333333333,20.,1890.));
#3280=CARTESIAN_POINT('',(-38.6666666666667,20.,1890.));
#3281=CARTESIAN_POINT('',(-38.5833333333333,20.,1890.));
#3282=CARTESIAN_POINT('',(-38.4166666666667,20.,1890.));
#3283=CARTESIAN_POINT('',(-38.3333333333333,20.,1890.));
#3284=CARTESIAN_POINT('',(-38.1666666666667,20.,1890.));
#3285=CARTESIAN_POINT('',(-38.0833333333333,20.,1890.));
#3286=CARTESIAN_POINT('',(-37.9166666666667,20.,1890.));
#3287=CARTESIAN_POINT('',(-37.8333333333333,20.,1890.));
#3288=CARTESIAN_POINT('',(-37.6666666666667,20.,1890.));
#3289=CARTESIAN_POINT('',(-37.5833333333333,20.,1890.));
#3290=CARTESIAN_POINT('',(-37.4166666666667,20.,1890.));
#3291=CARTESIAN_POINT('',(-37.3333333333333,20.,1890.));
#3292=CARTESIAN_POINT('',(-37.1666666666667,20.,1890.));
#3293=CARTESIAN_POINT('',(-37.0833333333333,20.,1890.));
#3294=CARTESIAN_POINT('',(-36.9166666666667,20.,1890.));
#3295=CARTESIAN_POINT('',(-36.8333333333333,20.,1890.));
#3296=CARTESIAN_POINT('',(-36.6666666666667,20.,1890.));
#3297=CARTESIAN_POINT('',(-36.5833333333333,20.,1890.));
#3298=CARTESIAN_POINT('',(-36.4166666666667,20.,1890.));
#3299=CARTESIAN_POINT('',(-36.3333333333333,20.,1890.));
#3300=CARTESIAN_POINT('',(-36.1666666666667,20.,1890.));
#3301=CARTESIAN_POINT('',(-36.0833333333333,20.,1890.));
#3302=CARTESIAN_POINT('',(-35.9166666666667,20.,1890.));
#3303=CARTESIAN_POINT('',(-35.8333333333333,20.,1890.));
#3304=CARTESIAN_POINT('',(-35.6666666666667,20.,1890.));
#3305=CARTESIAN_POINT('',(-35.5833333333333,20.,1890.));
#3306=CARTESIAN_POINT('',(-35.4166666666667,20.,1890.));
#3307=CARTESIAN_POINT('',(-35.3333333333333,20.,1890.));
#3308=CARTESIAN_POINT('',(-35.1666666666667,20.,1890.));
#3309=CARTESIAN_POINT('',(-35.0833333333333,20.,1890.));
#3310=CARTESIAN_POINT('',(-34.9166666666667,20.,1890.));
#3311=CARTESIAN_POINT('',(-34.8333333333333,20.,1890.));
#3312=CARTESIAN_POINT('',(-34.6666666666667,20.,1890.));
#3313=CARTESIAN_POINT('',(-34.5833333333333,20.,1890.));
#3314=CARTESIAN_POINT('',(-34.4166666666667,20.,1890.));
#3315=CARTESIAN_POINT('',(-34.3333333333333,20.,1890.));
#3316=CARTESIAN_POINT('',(-34.1666666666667,20.,1890.));
#3317=CARTESIAN_POINT('',(-34.0833333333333,20.,1890.));
#3318=CARTESIAN_POINT('',(-33.9166666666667,20.,1890.));
#3319=CARTESIAN_POINT('',(-33.8333333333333,20.,1890.));
#3320=CARTESIAN_POINT('',(-33.6666666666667,20.,1890.));
#3321=CARTESIAN_POINT('',(-33.5833333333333,20.,1890.));
#3322=CARTESIAN_POINT('',(-33.4166666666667,20.,1890.));
#3323=CARTESIAN_POINT('',(-33.3333333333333,20.,1890.));
#3324=CARTESIAN_POINT('',(-33.1666666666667,20.,1890.));
#3325=CARTESIAN_POINT('',(-33.0833333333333,20.,1890.));
#3326=CARTESIAN_POINT('',(-32.9166666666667,20.,1890.));
#3327=CARTESIAN_POINT('',(-32.8333333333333,20.,1890.));
#3328=CARTESIAN_POINT('',(-32.6666666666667,20.,1890.));
#3329=CARTESIAN_POINT('',(-32.5833333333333,20.,1890.));
#3330=CARTESIAN_POINT('',(-32.4166666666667,20.,1890.));
#3331=CARTESIAN_POINT('',(-32.3333333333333,20.,1890.));
#3332=CARTESIAN_POINT('',(-32.1666666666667,20.,1890.));
#3333=CARTESIAN_POINT('',(-32.0833333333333,20.,1890.));
#3334=CARTESIAN_POINT('',(-32.,20.,1890.));
#3335=B_SPLINE_CURVE_WITH_KNOTS('',3,(#3269,#3270,#3271,#3272,#3273,#3274,#3275,#3276,#3277,
#3278,#3279,#3280,#3281,#3282,#3283,#3284,#3285,#3286,#3287,#3288,#3289,#3290,#3291,#3292,#3293,
#3294,#3295,#3296,#3297,#3298,#3299,#3300,#3301,#3302,#3303,#3304,#3305,#3306,#3307,#3308,#3309,
#3310,#3311,#3312,#3313,#3314,#3315,#3316,#3317,#3318,#3319,#3320,#3321,#3322,#3323,#3324,#3325,
#3326,#3327,#3328,#3329,#3330,#3331,#3332,#3333,#3334),.UNSPECIFIED.,.F.,.F.,(4,2,2,2,2,2,2,2,2,
2,2,2,2,2,2,2,2,2,2,2,2,2,2,2,2,2,2,2,2,2,2,2,4),(0.,0.25,0.5,0.750000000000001,1.,1.25,1.5,
1.75,2.,2.25,2.5,2.75,3.,3.25,3.5,3.75,4.,4.25,4.5,4.75,5.,5.25,5.50000000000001,
5.75000000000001,6.00000000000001,6.25000000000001,6.50000000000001,6.75000000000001,
7.00000000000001,7.25000000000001,7.50000000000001,7.75000000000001,8.00000000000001),.UNSPECIFIED.);
#3336=EDGE_CURVE('BSEAM380',#317,#1308,#3335,.T.);
#3337=ORIENTED_EDGE('',*,*,#318,.T.);
#3338=ORIENTED_EDGE('',*,*,#1309,.F.);
#3339=ORIENTED_EDGE('',*,*,#3336,.T.);
#3340=ORIENTED_EDGE('',*,*,#3336,.F.);
#3341=EDGE_LOOP('',(#3337,#3339,#3338,#3340));
#3342=FACE_BOUND('',#3341,.T.);
#3343=ADVANCED_FACE('F380',(#3342),#3268,.F.);
#3344=CARTESIAN_POINT('',(40.,45.,1970.));
#3345=DIRECTION('',(-1.,0.,0.));
#3346=DIRECTION('',(0.,-1.,0.));
#3347=AXIS2_PLACEMENT_3D('',#3344,#3345,#3346);
#3348=CYLINDRICAL_SURFACE('',#3347,25.);
#3349=CARTESIAN_POINT('',(-40.,20.,1970.));
#3350=CARTESIAN_POINT('',(-39.9166666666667,20.,1970.));
#3351=CARTESIAN_POINT('',(-39.8333333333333,20.,1970.));
#3352=CARTESIAN_POINT('',(-39.6666666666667,20.,1970.));
#3353=CARTESIAN_POINT('',(-39.5833333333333,20.,1970.));
#3354=CARTESIAN_POINT('',(-39.4166666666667,20.,1970.));
#3355=CARTESIAN_POINT('',(-39.3333333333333,20.,1970.));
#3356=CARTESIAN_POINT('',(-39.1666666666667,20.,1970.));
#3357=CARTESIAN_POINT('',(-39.0833333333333,20.,1970.));
#3358=CARTESIAN_POINT('',(-38.9166666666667,20.,1970.));
#3359=CARTESIAN_POINT('',(-38.8333333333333,20.,1970.));
#3360=CARTESIAN_POINT('',(-38.6666666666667,20.,1970.));
#3361=CARTESIAN_POINT('',(-38.5833333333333,20.,1970.));
#3362=CARTESIAN_POINT('',(-38.4166666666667,20.,1970.));
#3363=CARTESIAN_POINT('',(-38.3333333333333,20.,1970.));
#3364=CARTESIAN_POINT('',(-38.1666666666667,20.,1970.));
#3365=CARTESIAN_POINT('',(-38.0833333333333,20.,1970.));
#3366=CARTESIAN_POINT('',(-37.9166666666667,20.,1970.));
#3367=CARTESIAN_POINT('',(-37.8333333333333,20.,1970.));
#3368=CARTESIAN_POINT('',(-37.6666666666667,20.,1970.));
#3369=CARTESIAN_POINT('',(-37.5833333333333,20.,1970.));
#3370=CARTESIAN_POINT('',(-37.4166666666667,20.,1970.));
#3371=CARTESIAN_POINT('',(-37.3333333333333,20.,1970.));
#3372=CARTESIAN_POINT('',(-37.1666666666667,20.,1970.));
#3373=CARTESIAN_POINT('',(-37.0833333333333,20.,1970.));
#3374=CARTESIAN_POINT('',(-36.9166666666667,20.,1970.));
#3375=CARTESIAN_POINT('',(-36.8333333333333,20.,1970.));
#3376=CARTESIAN_POINT('',(-36.6666666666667,20.,1970.));
#3377=CARTESIAN_POINT('',(-36.5833333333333,20.,1970.));
#3378=CARTESIAN_POINT('',(-36.4166666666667,20.,1970.));
#3379=CARTESIAN_POINT('',(-36.3333333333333,20.,1970.));
#3380=CARTESIAN_POINT('',(-36.1666666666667,20.,1970.));
#3381=CARTESIAN_POINT('',(-36.0833333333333,20.,1970.));
#3382=CARTESIAN_POINT('',(-35.9166666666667,20.,1970.));
#3383=CARTESIAN_POINT('',(-35.8333333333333,20.,1970.));
#3384=CARTESIAN_POINT('',(-35.6666666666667,20.,1970.));
#3385=CARTESIAN_POINT('',(-35.5833333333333,20.,1970.));
#3386=CARTESIAN_POINT('',(-35.4166666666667,20.,1970.));
#3387=CARTESIAN_POINT('',(-35.3333333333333,20.,1970.));
#3388=CARTESIAN_POINT('',(-35.1666666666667,20.,1970.));
#3389=CARTESIAN_POINT('',(-35.0833333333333,20.,1970.));
#3390=CARTESIAN_POINT('',(-34.9166666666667,20.,1970.));
#3391=CARTESIAN_POINT('',(-34.8333333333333,20.,1970.));
#3392=CARTESIAN_POINT('',(-34.6666666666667,20.,1970.));
#3393=CARTESIAN_POINT('',(-34.5833333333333,20.,1970.));
#3394=CARTESIAN_POINT('',(-34.4166666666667,20.,1970.));
#3395=CARTESIAN_POINT('',(-34.3333333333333,20.,1970.));
#3396=CARTESIAN_POINT('',(-34.1666666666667,20.,1970.));
#3397=CARTESIAN_POINT('',(-34.0833333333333,20.,1970.));
#3398=CARTESIAN_POINT('',(-33.9166666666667,20.,1970.));
#3399=CARTESIAN_POINT('',(-33.8333333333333,20.,1970.));
#3400=CARTESIAN_POINT('',(-33.6666666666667,20.,1970.));
#3401=CARTESIAN_POINT('',(-33.5833333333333,20.,1970.));
#3402=CARTESIAN_POINT('',(-33.4166666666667,20.,1970.));
#3403=CARTESIAN_POINT('',(-33.3333333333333,20.,1970.));
#3404=CARTESIAN_POINT('',(-33.1666666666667,20.,1970.));
#3405=CARTESIAN_POINT('',(-33.0833333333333,20.,1970.));
#3406=CARTESIAN_POINT('',(-32.9166666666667,20.,1970.));
#3407=CARTESIAN_POINT('',(-32.8333333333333,20.,1970.));
#3408=CARTESIAN_POINT('',(-32.6666666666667,20.,1970.));
#3409=CARTESIAN_POINT('',(-32.5833333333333,20.,1970.));
#3410=CARTESIAN_POINT('',(-32.4166666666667,20.,1970.));
#3411=CARTESIAN_POINT('',(-32.3333333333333,20.,1970.));
#3412=CARTESIAN_POINT('',(-32.1666666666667,20.,1970.));
#3413=CARTESIAN_POINT('',(-32.0833333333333,20.,1970.));
#3414=CARTESIAN_POINT('',(-32.,20.,1970.));
#3415=B_SPLINE_CURVE_WITH_KNOTS('',3,(#3349,#3350,#3351,#3352,#3353,#3354,#3355,#3356,#3357,
#3358,#3359,#3360,#3361,#3362,#3363,#3364,#3365,#3366,#3367,#3368,#3369,#3370,#3371,#3372,#3373,
#3374,#3375,#3376,#3377,#3378,#3379,#3380,#3381,#3382,#3383,#3384,#3385,#3386,#3387,#3388,#3389,
#3390,#3391,#3392,#3393,#3394,#3395,#3396,#3397,#3398,#3399,#3400,#3401,#3402,#3403,#3404,#3405,
#3406,#3407,#3408,#3409,#3410,#3411,#3412,#3413,#3414),.UNSPECIFIED.,.F.,.F.,(4,2,2,2,2,2,2,2,2,
2,2,2,2,2,2,2,2,2,2,2,2,2,2,2,2,2,2,2,2,2,2,2,4),(0.,0.25,0.5,0.750000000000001,1.,1.25,1.5,
1.75,2.,2.25,2.5,2.75,3.,3.25,3.5,3.75,4.,4.25,4.5,4.75,5.,5.25,5.50000000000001,
5.75000000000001,6.00000000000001,6.25000000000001,6.50000000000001,6.75000000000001,
7.00000000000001,7.25000000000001,7.50000000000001,7.75000000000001,8.00000000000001),.UNSPECIFIED.);
#3416=EDGE_CURVE('BSEAM383',#328,#1319,#3415,.T.);
#3417=ORIENTED_EDGE('',*,*,#329,.T.);
#3418=ORIENTED_EDGE('',*,*,#1320,.F.);
#3419=ORIENTED_EDGE('',*,*,#3416,.T.);
#3420=ORIENTED_EDGE('',*,*,#3416,.F.);
#3421=EDGE_LOOP('',(#3417,#3419,#3418,#3420));
#3422=FACE_BOUND('',#3421,.T.);
#3423=ADVANCED_FACE('F383',(#3422),#3348,.F.);
#3424=CARTESIAN_POINT('',(40.,45.,2050.));
#3425=DIRECTION('',(-1.,0.,0.));
#3426=DIRECTION('',(0.,-1.,0.));
#3427=AXIS2_PLACEMENT_3D('',#3424,#3425,#3426);
#3428=CYLINDRICAL_SURFACE('',#3427,25.);
#3429=CARTESIAN_POINT('',(-40.,20.,2050.));
#3430=CARTESIAN_POINT('',(-39.9166666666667,20.,2050.));
#3431=CARTESIAN_POINT('',(-39.8333333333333,20.,2050.));
#3432=CARTESIAN_POINT('',(-39.6666666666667,20.,2050.));
#3433=CARTESIAN_POINT('',(-39.5833333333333,20.,2050.));
#3434=CARTESIAN_POINT('',(-39.4166666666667,20.,2050.));
#3435=CARTESIAN_POINT('',(-39.3333333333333,20.,2050.));
#3436=CARTESIAN_POINT('',(-39.1666666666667,20.,2050.));
#3437=CARTESIAN_POINT('',(-39.0833333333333,20.,2050.));
#3438=CARTESIAN_POINT('',(-38.9166666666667,20.,2050.));
#3439=CARTESIAN_POINT('',(-38.8333333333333,20.,2050.));
#3440=CARTESIAN_POINT('',(-38.6666666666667,20.,2050.));
#3441=CARTESIAN_POINT('',(-38.5833333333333,20.,2050.));
#3442=CARTESIAN_POINT('',(-38.4166666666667,20.,2050.));
#3443=CARTESIAN_POINT('',(-38.3333333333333,20.,2050.));
#3444=CARTESIAN_POINT('',(-38.1666666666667,20.,2050.));
#3445=CARTESIAN_POINT('',(-38.0833333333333,20.,2050.));
#3446=CARTESIAN_POINT('',(-37.9166666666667,20.,2050.));
#3447=CARTESIAN_POINT('',(-37.8333333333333,20.,2050.));
#3448=CARTESIAN_POINT('',(-37.6666666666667,20.,2050.));
#3449=CARTESIAN_POINT('',(-37.5833333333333,20.,2050.));
#3450=CARTESIAN_POINT('',(-37.4166666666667,20.,2050.));
#3451=CARTESIAN_POINT('',(-37.3333333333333,20.,2050.));
#3452=CARTESIAN_POINT('',(-37.1666666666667,20.,2050.));
#3453=CARTESIAN_POINT('',(-37.0833333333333,20.,2050.));
#3454=CARTESIAN_POINT('',(-36.9166666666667,20.,2050.));
#3455=CARTESIAN_POINT('',(-36.8333333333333,20.,2050.));
#3456=CARTESIAN_POINT('',(-36.6666666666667,20.,2050.));
#3457=CARTESIAN_POINT('',(-36.5833333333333,20.,2050.));
#3458=CARTESIAN_POINT('',(-36.4166666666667,20.,2050.));
#3459=CARTESIAN_POINT('',(-36.3333333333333,20.,2050.));
#3460=CARTESIAN_POINT('',(-36.1666666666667,20.,2050.));
#3461=CARTESIAN_POINT('',(-36.0833333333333,20.,2050.));
#3462=CARTESIAN_POINT('',(-35.9166666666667,20.,2050.));
#3463=CARTESIAN_POINT('',(-35.8333333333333,20.,2050.));
#3464=CARTESIAN_POINT('',(-35.6666666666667,20.,2050.));
#3465=CARTESIAN_POINT('',(-35.5833333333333,20.,2050.));
#3466=CARTESIAN_POINT('',(-35.4166666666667,20.,2050.));
#3467=CARTESIAN_POINT('',(-35.3333333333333,20.,2050.));
#3468=CARTESIAN_POINT('',(-35.1666666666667,20.,2050.));
#3469=CARTESIAN_POINT('',(-35.0833333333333,20.,2050.));
#3470=CARTESIAN_POINT('',(-34.9166666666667,20.,2050.));
#3471=CARTESIAN_POINT('',(-34.8333333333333,20.,2050.));
#3472=CARTESIAN_POINT('',(-34.6666666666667,20.,2050.));
#3473=CARTESIAN_POINT('',(-34.5833333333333,20.,2050.));
#3474=CARTESIAN_POINT('',(-34.4166666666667,20.,2050.));
#3475=CARTESIAN_POINT('',(-34.3333333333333,20.,2050.));
#3476=CARTESIAN_POINT('',(-34.1666666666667,20.,2050.));
#3477=CARTESIAN_POINT('',(-34.0833333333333,20.,2050.));
#3478=CARTESIAN_POINT('',(-33.9166666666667,20.,2050.));
#3479=CARTESIAN_POINT('',(-33.8333333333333,20.,2050.));
#3480=CARTESIAN_POINT('',(-33.6666666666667,20.,2050.));
#3481=CARTESIAN_POINT('',(-33.5833333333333,20.,2050.));
#3482=CARTESIAN_POINT('',(-33.4166666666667,20.,2050.));
#3483=CARTESIAN_POINT('',(-33.3333333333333,20.,2050.));
#3484=CARTESIAN_POINT('',(-33.1666666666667,20.,2050.));
#3485=CARTESIAN_POINT('',(-33.0833333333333,20.,2050.));
#3486=CARTESIAN_POINT('',(-32.9166666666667,20.,2050.));
#3487=CARTESIAN_POINT('',(-32.8333333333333,20.,2050.));
#3488=CARTESIAN_POINT('',(-32.6666666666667,20.,2050.));
#3489=CARTESIAN_POINT('',(-32.5833333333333,20.,2050.));
#3490=CARTESIAN_POINT('',(-32.4166666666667,20.,2050.));
#3491=CARTESIAN_POINT('',(-32.3333333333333,20.,2050.));
#3492=CARTESIAN_POINT('',(-32.1666666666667,20.,2050.));
#3493=CARTESIAN_POINT('',(-32.0833333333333,20.,2050.));
#3494=CARTESIAN_POINT('',(-32.,20.,2050.));
#3495=B_SPLINE_CURVE_WITH_KNOTS('',3,(#3429,#3430,#3431,#3432,#3433,#3434,#3435,#3436,#3437,
#3438,#3439,#3440,#3441,#3442,#3443,#3444,#3445,#3446,#3447,#3448,#3449,#3450,#3451,#3452,#3453,
#3454,#3455,#3456,#3457,#3458,#3459,#3460,#3461,#3462,#3463,#3464,#3465,#3466,#3467,#3468,#3469,
#3470,#3471,#3472,#3473,#3474,#3475,#3476,#3477,#3478,#3479,#3480,#3481,#3482,#3483,#3484,#3485,
#3486,#3487,#3488,#3489,#3490,#3491,#3492,#3493,#3494),.UNSPECIFIED.,.F.,.F.,(4,2,2,2,2,2,2,2,2,
2,2,2,2,2,2,2,2,2,2,2,2,2,2,2,2,2,2,2,2,2,2,2,4),(0.,0.25,0.5,0.750000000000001,1.,1.25,1.5,
1.75,2.,2.25,2.5,2.75,3.,3.25,3.5,3.75,4.,4.25,4.5,4.75,5.,5.25,5.50000000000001,
5.75000000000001,6.00000000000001,6.25000000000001,6.50000000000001,6.75000000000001,
7.00000000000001,7.25000000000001,7.50000000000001,7.75000000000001,8.00000000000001),.UNSPECIFIED.);
#3496=EDGE_CURVE('BSEAM35',#339,#1330,#3495,.T.);
#3497=ORIENTED_EDGE('',*,*,#340,.T.);
#3498=ORIENTED_EDGE('',*,*,#1331,.F.);
#3499=ORIENTED_EDGE('',*,*,#3496,.T.);
#3500=ORIENTED_EDGE('',*,*,#3496,.F.);
#3501=EDGE_LOOP('',(#3497,#3499,#3498,#3500));
#3502=FACE_BOUND('',#3501,.T.);
#3503=ADVANCED_FACE('F35',(#3502),#3428,.F.);
#3504=CARTESIAN_POINT('',(5.00000000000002,0.,130.));
#3505=DIRECTION('',(0.,1.,0.));
#3506=DIRECTION('',(0.,0.,1.));
#3507=AXIS2_PLACEMENT_3D('',#3504,#3505,#3506);
#3508=CYLINDRICAL_SURFACE('',#3507,25.);
#3509=ORIENTED_EDGE('',*,*,#621,.F.);
#3510=EDGE_LOOP('',(#3509));
#3511=FACE_BOUND('',#3510,.T.);
#3512=ORIENTED_EDGE('',*,*,#969,.T.);
#3513=EDGE_LOOP('',(#3512));
#3514=FACE_BOUND('',#3513,.T.);
#3515=ADVANCED_FACE('F390',(#3511,#3514),#3508,.F.);
#3516=CARTESIAN_POINT('',(5.00000000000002,0.,210.));
#3517=DIRECTION('',(0.,1.,0.));
#3518=DIRECTION('',(0.,0.,1.));
#3519=AXIS2_PLACEMENT_3D('',#3516,#3517,#3518);
#3520=CYLINDRICAL_SURFACE('',#3519,25.);
#3521=ORIENTED_EDGE('',*,*,#610,.F.);
#3522=EDGE_LOOP('',(#3521));
#3523=FACE_BOUND('',#3522,.T.);
#3524=ORIENTED_EDGE('',*,*,#958,.T.);
#3525=EDGE_LOOP('',(#3524));
#3526=FACE_BOUND('',#3525,.T.);
#3527=ADVANCED_FACE('F881',(#3523,#3526),#3520,.F.);
#3528=CARTESIAN_POINT('',(5.00000000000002,0.,290.));
#3529=DIRECTION('',(0.,1.,0.));
#3530=DIRECTION('',(0.,0.,1.));
#3531=AXIS2_PLACEMENT_3D('',#3528,#3529,#3530);
#3532=CYLINDRICAL_SURFACE('',#3531,25.);
#3533=ORIENTED_EDGE('',*,*,#599,.F.);
#3534=EDGE_LOOP('',(#3533));
#3535=FACE_BOUND('',#3534,.T.);
#3536=ORIENTED_EDGE('',*,*,#947,.T.);
#3537=EDGE_LOOP('',(#3536));
#3538=FACE_BOUND('',#3537,.T.);
#3539=ADVANCED_FACE('F890',(#3535,#3538),#3532,.F.);
#3540=CARTESIAN_POINT('',(5.00000000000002,0.,370.));
#3541=DIRECTION('',(0.,1.,0.));
#3542=DIRECTION('',(0.,0.,1.));
#3543=AXIS2_PLACEMENT_3D('',#3540,#3541,#3542);
#3544=CYLINDRICAL_SURFACE('',#3543,25.);
#3545=ORIENTED_EDGE('',*,*,#588,.F.);
#3546=EDGE_LOOP('',(#3545));
#3547=FACE_BOUND('',#3546,.T.);
#3548=ORIENTED_EDGE('',*,*,#936,.T.);
#3549=EDGE_LOOP('',(#3548));
#3550=FACE_BOUND('',#3549,.T.);
#3551=ADVANCED_FACE('F900',(#3547,#3550),#3544,.F.);
#3552=CARTESIAN_POINT('',(5.00000000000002,0.,450.));
#3553=DIRECTION('',(0.,1.,0.));
#3554=DIRECTION('',(0.,0.,1.));
#3555=AXIS2_PLACEMENT_3D('',#3552,#3553,#3554);
#3556=CYLINDRICAL_SURFACE('',#3555,25.);
#3557=ORIENTED_EDGE('',*,*,#577,.F.);
#3558=EDGE_LOOP('',(#3557));
#3559=FACE_BOUND('',#3558,.T.);
#3560=ORIENTED_EDGE('',*,*,#925,.T.);
#3561=EDGE_LOOP('',(#3560));
#3562=FACE_BOUND('',#3561,.T.);
#3563=ADVANCED_FACE('F910',(#3559,#3562),#3556,.F.);
#3564=CARTESIAN_POINT('',(5.00000000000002,0.,530.));
#3565=DIRECTION('',(0.,1.,0.));
#3566=DIRECTION('',(0.,0.,1.));
#3567=AXIS2_PLACEMENT_3D('',#3564,#3565,#3566);
#3568=CYLINDRICAL_SURFACE('',#3567,25.);
#3569=ORIENTED_EDGE('',*,*,#566,.F.);
#3570=EDGE_LOOP('',(#3569));
#3571=FACE_BOUND('',#3570,.T.);
#3572=ORIENTED_EDGE('',*,*,#914,.T.);
#3573=EDGE_LOOP('',(#3572));
#3574=FACE_BOUND('',#3573,.T.);
#3575=ADVANCED_FACE('F920',(#3571,#3574),#3568,.F.);
#3576=CARTESIAN_POINT('',(5.00000000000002,0.,610.));
#3577=DIRECTION('',(0.,1.,0.));
#3578=DIRECTION('',(0.,0.,1.));
#3579=AXIS2_PLACEMENT_3D('',#3576,#3577,#3578);
#3580=CYLINDRICAL_SURFACE('',#3579,25.);
#3581=ORIENTED_EDGE('',*,*,#555,.F.);
#3582=EDGE_LOOP('',(#3581));
#3583=FACE_BOUND('',#3582,.T.);
#3584=ORIENTED_EDGE('',*,*,#903,.T.);
#3585=EDGE_LOOP('',(#3584));
#3586=FACE_BOUND('',#3585,.T.);
#3587=ADVANCED_FACE('F930',(#3583,#3586),#3580,.F.);
#3588=CARTESIAN_POINT('',(5.00000000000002,0.,690.));
#3589=DIRECTION('',(0.,1.,0.));
#3590=DIRECTION('',(0.,0.,1.));
#3591=AXIS2_PLACEMENT_3D('',#3588,#3589,#3590);
#3592=CYLINDRICAL_SURFACE('',#3591,25.);
#3593=ORIENTED_EDGE('',*,*,#544,.F.);
#3594=EDGE_LOOP('',(#3593));
#3595=FACE_BOUND('',#3594,.T.);
#3596=ORIENTED_EDGE('',*,*,#892,.T.);
#3597=EDGE_LOOP('',(#3596));
#3598=FACE_BOUND('',#3597,.T.);
#3599=ADVANCED_FACE('F940',(#3595,#3598),#3592,.F.);
#3600=CARTESIAN_POINT('',(5.00000000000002,0.,770.));
#3601=DIRECTION('',(0.,1.,0.));
#3602=DIRECTION('',(0.,0.,1.));
#3603=AXIS2_PLACEMENT_3D('',#3600,#3601,#3602);
#3604=CYLINDRICAL_SURFACE('',#3603,25.);
#3605=ORIENTED_EDGE('',*,*,#533,.F.);
#3606=EDGE_LOOP('',(#3605));
#3607=FACE_BOUND('',#3606,.T.);
#3608=ORIENTED_EDGE('',*,*,#881,.T.);
#3609=EDGE_LOOP('',(#3608));
#3610=FACE_BOUND('',#3609,.T.);
#3611=ADVANCED_FACE('F950',(#3607,#3610),#3604,.F.);
#3612=CARTESIAN_POINT('',(5.00000000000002,0.,850.));
#3613=DIRECTION('',(0.,1.,0.));
#3614=DIRECTION('',(0.,0.,1.));
#3615=AXIS2_PLACEMENT_3D('',#3612,#3613,#3614);
#3616=CYLINDRICAL_SURFACE('',#3615,25.);
#3617=ORIENTED_EDGE('',*,*,#522,.F.);
#3618=EDGE_LOOP('',(#3617));
#3619=FACE_BOUND('',#3618,.T.);
#3620=ORIENTED_EDGE('',*,*,#870,.T.);
#3621=EDGE_LOOP('',(#3620));
#3622=FACE_BOUND('',#3621,.T.);
#3623=ADVANCED_FACE('F960',(#3619,#3622),#3616,.F.);
#3624=CARTESIAN_POINT('',(5.00000000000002,0.,930.));
#3625=DIRECTION('',(0.,1.,0.));
#3626=DIRECTION('',(0.,0.,1.));
#3627=AXIS2_PLACEMENT_3D('',#3624,#3625,#3626);
#3628=CYLINDRICAL_SURFACE('',#3627,25.);
#3629=ORIENTED_EDGE('',*,*,#511,.F.);
#3630=EDGE_LOOP('',(#3629));
#3631=FACE_BOUND('',#3630,.T.);
#3632=ORIENTED_EDGE('',*,*,#859,.T.);
#3633=EDGE_LOOP('',(#3632));
#3634=FACE_BOUND('',#3633,.T.);
#3635=ADVANCED_FACE('F970',(#3631,#3634),#3628,.F.);
#3636=CARTESIAN_POINT('',(5.00000000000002,0.,1010.));
#3637=DIRECTION('',(0.,1.,0.));
#3638=DIRECTION('',(0.,0.,1.));
#3639=AXIS2_PLACEMENT_3D('',#3636,#3637,#3638);
#3640=CYLINDRICAL_SURFACE('',#3639,25.);
#3641=ORIENTED_EDGE('',*,*,#500,.F.);
#3642=EDGE_LOOP('',(#3641));
#3643=FACE_BOUND('',#3642,.T.);
#3644=ORIENTED_EDGE('',*,*,#848,.T.);
#3645=EDGE_LOOP('',(#3644));
#3646=FACE_BOUND('',#3645,.T.);
#3647=ADVANCED_FACE('F980',(#3643,#3646),#3640,.F.);
#3648=CARTESIAN_POINT('',(5.00000000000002,0.,1090.));
#3649=DIRECTION('',(0.,1.,0.));
#3650=DIRECTION('',(0.,0.,1.));
#3651=AXIS2_PLACEMENT_3D('',#3648,#3649,#3650);
#3652=CYLINDRICAL_SURFACE('',#3651,25.);
#3653=ORIENTED_EDGE('',*,*,#489,.F.);
#3654=EDGE_LOOP('',(#3653));
#3655=FACE_BOUND('',#3654,.T.);
#3656=ORIENTED_EDGE('',*,*,#837,.T.);
#3657=EDGE_LOOP('',(#3656));
#3658=FACE_BOUND('',#3657,.T.);
#3659=ADVANCED_FACE('F990',(#3655,#3658),#3652,.F.);
#3660=CARTESIAN_POINT('',(5.00000000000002,0.,1170.));
#3661=DIRECTION('',(0.,1.,0.));
#3662=DIRECTION('',(0.,0.,1.));
#3663=AXIS2_PLACEMENT_3D('',#3660,#3661,#3662);
#3664=CYLINDRICAL_SURFACE('',#3663,25.);
#3665=ORIENTED_EDGE('',*,*,#478,.F.);
#3666=EDGE_LOOP('',(#3665));
#3667=FACE_BOUND('',#3666,.T.);
#3668=ORIENTED_EDGE('',*,*,#826,.T.);
#3669=EDGE_LOOP('',(#3668));
#3670=FACE_BOUND('',#3669,.T.);
#3671=ADVANCED_FACE('F1000',(#3667,#3670),#3664,.F.);
#3672=CARTESIAN_POINT('',(5.00000000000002,0.,1250.));
#3673=DIRECTION('',(0.,1.,0.));
#3674=DIRECTION('',(0.,0.,1.));
#3675=AXIS2_PLACEMENT_3D('',#3672,#3673,#3674);
#3676=CYLINDRICAL_SURFACE('',#3675,25.);
#3677=ORIENTED_EDGE('',*,*,#467,.F.);
#3678=EDGE_LOOP('',(#3677));
#3679=FACE_BOUND('',#3678,.T.);
#3680=ORIENTED_EDGE('',*,*,#815,.T.);
#3681=EDGE_LOOP('',(#3680));
#3682=FACE_BOUND('',#3681,.T.);
#3683=ADVANCED_FACE('F1010',(#3679,#3682),#3676,.F.);
#3684=CARTESIAN_POINT('',(5.00000000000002,0.,1330.));
#3685=DIRECTION('',(0.,1.,0.));
#3686=DIRECTION('',(0.,0.,1.));
#3687=AXIS2_PLACEMENT_3D('',#3684,#3685,#3686);
#3688=CYLINDRICAL_SURFACE('',#3687,25.);
#3689=ORIENTED_EDGE('',*,*,#456,.F.);
#3690=EDGE_LOOP('',(#3689));
#3691=FACE_BOUND('',#3690,.T.);
#3692=ORIENTED_EDGE('',*,*,#804,.T.);
#3693=EDGE_LOOP('',(#3692));
#3694=FACE_BOUND('',#3693,.T.);
#3695=ADVANCED_FACE('F1020',(#3691,#3694),#3688,.F.);
#3696=CARTESIAN_POINT('',(5.00000000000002,0.,1410.));
#3697=DIRECTION('',(0.,1.,0.));
#3698=DIRECTION('',(0.,0.,1.));
#3699=AXIS2_PLACEMENT_3D('',#3696,#3697,#3698);
#3700=CYLINDRICAL_SURFACE('',#3699,25.);
#3701=ORIENTED_EDGE('',*,*,#445,.F.);
#3702=EDGE_LOOP('',(#3701));
#3703=FACE_BOUND('',#3702,.T.);
#3704=ORIENTED_EDGE('',*,*,#793,.T.);
#3705=EDGE_LOOP('',(#3704));
#3706=FACE_BOUND('',#3705,.T.);
#3707=ADVANCED_FACE('F1030',(#3703,#3706),#3700,.F.);
#3708=CARTESIAN_POINT('',(5.00000000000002,0.,1490.));
#3709=DIRECTION('',(0.,1.,0.));
#3710=DIRECTION('',(0.,0.,1.));
#3711=AXIS2_PLACEMENT_3D('',#3708,#3709,#3710);
#3712=CYLINDRICAL_SURFACE('',#3711,25.);
#3713=ORIENTED_EDGE('',*,*,#434,.F.);
#3714=EDGE_LOOP('',(#3713));
#3715=FACE_BOUND('',#3714,.T.);
#3716=ORIENTED_EDGE('',*,*,#782,.T.);
#3717=EDGE_LOOP('',(#3716));
#3718=FACE_BOUND('',#3717,.T.);
#3719=ADVANCED_FACE('F1040',(#3715,#3718),#3712,.F.);
#3720=CARTESIAN_POINT('',(5.00000000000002,0.,1570.));
#3721=DIRECTION('',(0.,1.,0.));
#3722=DIRECTION('',(0.,0.,1.));
#3723=AXIS2_PLACEMENT_3D('',#3720,#3721,#3722);
#3724=CYLINDRICAL_SURFACE('',#3723,25.);
#3725=ORIENTED_EDGE('',*,*,#423,.F.);
#3726=EDGE_LOOP('',(#3725));
#3727=FACE_BOUND('',#3726,.T.);
#3728=ORIENTED_EDGE('',*,*,#771,.T.);
#3729=EDGE_LOOP('',(#3728));
#3730=FACE_BOUND('',#3729,.T.);
#3731=ADVANCED_FACE('F1050',(#3727,#3730),#3724,.F.);
#3732=CARTESIAN_POINT('',(5.00000000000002,0.,1650.));
#3733=DIRECTION('',(0.,1.,0.));
#3734=DIRECTION('',(0.,0.,1.));
#3735=AXIS2_PLACEMENT_3D('',#3732,#3733,#3734);
#3736=CYLINDRICAL_SURFACE('',#3735,25.);
#3737=ORIENTED_EDGE('',*,*,#412,.F.);
#3738=EDGE_LOOP('',(#3737));
#3739=FACE_BOUND('',#3738,.T.);
#3740=ORIENTED_EDGE('',*,*,#760,.T.);
#3741=EDGE_LOOP('',(#3740));
#3742=FACE_BOUND('',#3741,.T.);
#3743=ADVANCED_FACE('F1060',(#3739,#3742),#3736,.F.);
#3744=CARTESIAN_POINT('',(5.00000000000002,0.,1730.));
#3745=DIRECTION('',(0.,1.,0.));
#3746=DIRECTION('',(0.,0.,1.));
#3747=AXIS2_PLACEMENT_3D('',#3744,#3745,#3746);
#3748=CYLINDRICAL_SURFACE('',#3747,25.);
#3749=ORIENTED_EDGE('',*,*,#401,.F.);
#3750=EDGE_LOOP('',(#3749));
#3751=FACE_BOUND('',#3750,.T.);
#3752=ORIENTED_EDGE('',*,*,#749,.T.);
#3753=EDGE_LOOP('',(#3752));
#3754=FACE_BOUND('',#3753,.T.);
#3755=ADVANCED_FACE('F1070',(#3751,#3754),#3748,.F.);
#3756=CARTESIAN_POINT('',(5.00000000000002,0.,1810.));
#3757=DIRECTION('',(0.,1.,0.));
#3758=DIRECTION('',(0.,0.,1.));
#3759=AXIS2_PLACEMENT_3D('',#3756,#3757,#3758);
#3760=CYLINDRICAL_SURFACE('',#3759,25.);
#3761=ORIENTED_EDGE('',*,*,#390,.F.);
#3762=EDGE_LOOP('',(#3761));
#3763=FACE_BOUND('',#3762,.T.);
#3764=ORIENTED_EDGE('',*,*,#738,.T.);
#3765=EDGE_LOOP('',(#3764));
#3766=FACE_BOUND('',#3765,.T.);
#3767=ADVANCED_FACE('F1080',(#3763,#3766),#3760,.F.);
#3768=CARTESIAN_POINT('',(5.00000000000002,0.,1890.));
#3769=DIRECTION('',(0.,1.,0.));
#3770=DIRECTION('',(0.,0.,1.));
#3771=AXIS2_PLACEMENT_3D('',#3768,#3769,#3770);
#3772=CYLINDRICAL_SURFACE('',#3771,25.);
#3773=ORIENTED_EDGE('',*,*,#379,.F.);
#3774=EDGE_LOOP('',(#3773));
#3775=FACE_BOUND('',#3774,.T.);
#3776=ORIENTED_EDGE('',*,*,#727,.T.);
#3777=EDGE_LOOP('',(#3776));
#3778=FACE_BOUND('',#3777,.T.);
#3779=ADVANCED_FACE('F1090',(#3775,#3778),#3772,.F.);
#3780=CARTESIAN_POINT('',(5.00000000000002,0.,1970.));
#3781=DIRECTION('',(0.,1.,0.));
#3782=DIRECTION('',(0.,0.,1.));
#3783=AXIS2_PLACEMENT_3D('',#3780,#3781,#3782);
#3784=CYLINDRICAL_SURFACE('',#3783,25.);
#3785=ORIENTED_EDGE('',*,*,#368,.F.);
#3786=EDGE_LOOP('',(#3785));
#3787=FACE_BOUND('',#3786,.T.);
#3788=ORIENTED_EDGE('',*,*,#716,.T.);
#3789=EDGE_LOOP('',(#3788));
#3790=FACE_BOUND('',#3789,.T.);
#3791=ADVANCED_FACE('F615',(#3787,#3790),#3784,.F.);
#3792=CARTESIAN_POINT('',(5.00000000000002,0.,2050.));
#3793=DIRECTION('',(0.,1.,0.));
#3794=DIRECTION('',(0.,0.,1.));
#3795=AXIS2_PLACEMENT_3D('',#3792,#3793,#3794);
#3796=CYLINDRICAL_SURFACE('',#3795,25.);
#3797=ORIENTED_EDGE('',*,*,#357,.F.);
#3798=EDGE_LOOP('',(#3797));
#3799=FACE_BOUND('',#3798,.T.);
#3800=ORIENTED_EDGE('',*,*,#705,.T.);
#3801=EDGE_LOOP('',(#3800));
#3802=FACE_BOUND('',#3801,.T.);
#3803=ADVANCED_FACE('F612',(#3799,#3802),#3796,.F.);
#3804=CLOSED_SHELL('',(#344,#661,#692,#1009,#1335,#1357,#1378,#1399,#1411,#1491,#1503,#1583,
#1663,#1743,#1823,#1903,#1983,#2063,#2143,#2223,#2303,#2383,#2463,#2543,#2623,#2703,#2783,#2863,
#2943,#3023,#3103,#3183,#3263,#3343,#3423,#3503,#3515,#3527,#3539,#3551,#3563,#3575,#3587,#3599,
#3611,#3623,#3635,#3647,#3659,#3671,#3683,#3695,#3707,#3719,#3731,#3743,#3755,#3767,#3779,#3791,#3803));
#3805=MANIFOLD_SOLID_BREP('B2',#3804);
#3806=ADVANCED_BREP_SHAPE_REPRESENTATION('',(#18,#3805),#14);
#3807=SHAPE_DEFINITION_REPRESENTATION(#9,#3806);
ENDSEC;
END-ISO-10303-21;
